VERSION 5.7 ;
  NOWIREEXTENSIONATPIN ON ;
  DIVIDERCHAR "/" ;
  BUSBITCHARS "[]" ;
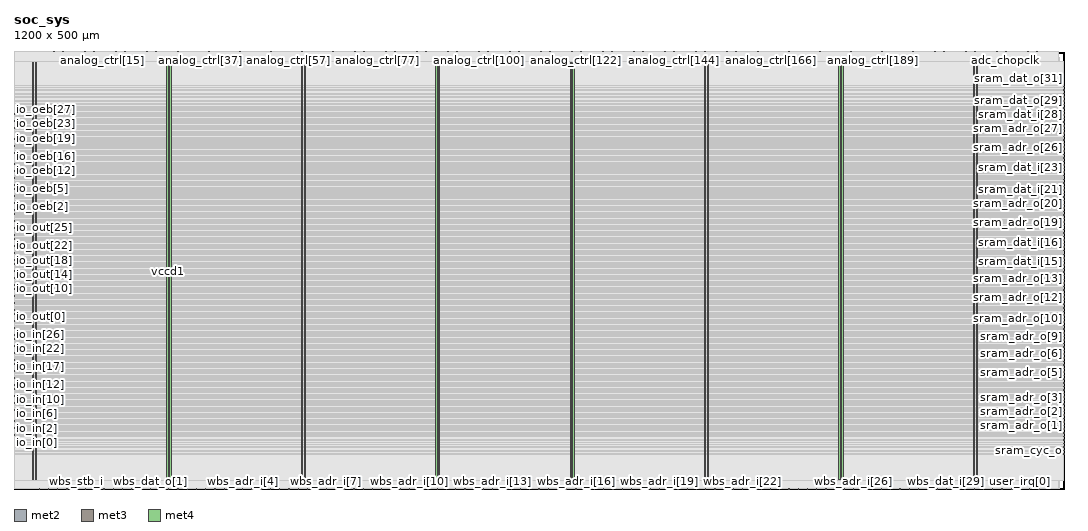
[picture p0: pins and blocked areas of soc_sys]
MACRO soc_sys
  CLASS BLOCK ;
  FOREIGN soc_sys ;
  ORIGIN 0.000 0.000 ;
  SIZE 1200.000 BY 500.000 ;
  PIN adc_chopclk
    DIRECTION INPUT ;
    USE SIGNAL ;
    ANTENNAGATEAREA 0.647700 ;
    ANTENNADIFFAREA 0.434700 ;
    PORT
      LAYER met2 ;
        RECT 1133.530 499.720 1133.810 500.000 ;
    END
  END adc_chopclk
  PIN adc_dout[0]
    DIRECTION INPUT ;
    USE SIGNAL ;
    ANTENNAGATEAREA 0.631200 ;
    ANTENNADIFFAREA 0.434700 ;
    PORT
      LAYER met2 ;
        RECT 1072.810 499.720 1073.090 500.000 ;
    END
  END adc_dout[0]
  PIN adc_dout[1]
    DIRECTION INPUT ;
    USE SIGNAL ;
    ANTENNAGATEAREA 0.593700 ;
    ANTENNADIFFAREA 0.434700 ;
    PORT
      LAYER met2 ;
        RECT 1077.870 499.720 1078.150 500.000 ;
    END
  END adc_dout[1]
  PIN adc_dout[2]
    DIRECTION INPUT ;
    USE SIGNAL ;
    ANTENNAGATEAREA 0.593700 ;
    ANTENNADIFFAREA 0.434700 ;
    PORT
      LAYER met2 ;
        RECT 1082.930 499.720 1083.210 500.000 ;
    END
  END adc_dout[2]
  PIN adc_dout[3]
    DIRECTION INPUT ;
    USE SIGNAL ;
    ANTENNAGATEAREA 0.631200 ;
    ANTENNADIFFAREA 0.434700 ;
    PORT
      LAYER met2 ;
        RECT 1087.990 499.720 1088.270 500.000 ;
    END
  END adc_dout[3]
  PIN adc_dout[4]
    DIRECTION INPUT ;
    USE SIGNAL ;
    ANTENNAGATEAREA 0.631200 ;
    ANTENNADIFFAREA 0.434700 ;
    PORT
      LAYER met2 ;
        RECT 1093.050 499.720 1093.330 500.000 ;
    END
  END adc_dout[4]
  PIN adc_dout[5]
    DIRECTION INPUT ;
    USE SIGNAL ;
    ANTENNAGATEAREA 0.593700 ;
    ANTENNADIFFAREA 0.434700 ;
    PORT
      LAYER met2 ;
        RECT 1098.110 499.720 1098.390 500.000 ;
    END
  END adc_dout[5]
  PIN adc_dout[6]
    DIRECTION INPUT ;
    USE SIGNAL ;
    ANTENNAGATEAREA 0.647700 ;
    ANTENNADIFFAREA 0.434700 ;
    PORT
      LAYER met2 ;
        RECT 1103.170 499.720 1103.450 500.000 ;
    END
  END adc_dout[6]
  PIN adc_dout[7]
    DIRECTION INPUT ;
    USE SIGNAL ;
    ANTENNAGATEAREA 0.647700 ;
    ANTENNADIFFAREA 0.434700 ;
    PORT
      LAYER met2 ;
        RECT 1108.230 499.720 1108.510 500.000 ;
    END
  END adc_dout[7]
  PIN adc_ov_one
    DIRECTION INPUT ;
    USE SIGNAL ;
    ANTENNAGATEAREA 0.631200 ;
    ANTENNADIFFAREA 0.434700 ;
    PORT
      LAYER met2 ;
        RECT 1118.350 499.720 1118.630 500.000 ;
    END
  END adc_ov_one
  PIN adc_ov_zero
    DIRECTION INPUT ;
    USE SIGNAL ;
    ANTENNAGATEAREA 0.647700 ;
    ANTENNADIFFAREA 0.434700 ;
    PORT
      LAYER met2 ;
        RECT 1113.290 499.720 1113.570 500.000 ;
    END
  END adc_ov_zero
  PIN adc_scanout
    DIRECTION INPUT ;
    USE SIGNAL ;
    ANTENNAGATEAREA 0.647700 ;
    ANTENNADIFFAREA 0.434700 ;
    PORT
      LAYER met2 ;
        RECT 1123.410 499.720 1123.690 500.000 ;
    END
  END adc_scanout
  PIN adc_test[0]
    DIRECTION INPUT ;
    USE SIGNAL ;
    ANTENNAGATEAREA 0.647700 ;
    ANTENNADIFFAREA 0.434700 ;
    PORT
      LAYER met2 ;
        RECT 1138.590 499.720 1138.870 500.000 ;
    END
  END adc_test[0]
  PIN adc_test[1]
    DIRECTION INPUT ;
    USE SIGNAL ;
    ANTENNAGATEAREA 0.647700 ;
    ANTENNADIFFAREA 0.434700 ;
    PORT
      LAYER met2 ;
        RECT 1143.650 499.720 1143.930 500.000 ;
    END
  END adc_test[1]
  PIN adc_test[2]
    DIRECTION INPUT ;
    USE SIGNAL ;
    ANTENNAGATEAREA 0.647700 ;
    ANTENNADIFFAREA 0.434700 ;
    PORT
      LAYER met2 ;
        RECT 1148.710 499.720 1148.990 500.000 ;
    END
  END adc_test[2]
  PIN adc_test[3]
    DIRECTION INPUT ;
    USE SIGNAL ;
    ANTENNAGATEAREA 0.647700 ;
    ANTENNADIFFAREA 0.434700 ;
    PORT
      LAYER met2 ;
        RECT 1153.770 499.720 1154.050 500.000 ;
    END
  END adc_test[3]
  PIN adc_test[4]
    DIRECTION INPUT ;
    USE SIGNAL ;
    ANTENNAGATEAREA 0.647700 ;
    ANTENNADIFFAREA 0.434700 ;
    PORT
      LAYER met2 ;
        RECT 1158.830 499.720 1159.110 500.000 ;
    END
  END adc_test[4]
  PIN adc_test[5]
    DIRECTION INPUT ;
    USE SIGNAL ;
    ANTENNAGATEAREA 0.631200 ;
    ANTENNADIFFAREA 0.434700 ;
    PORT
      LAYER met2 ;
        RECT 1163.890 499.720 1164.170 500.000 ;
    END
  END adc_test[5]
  PIN adc_test[6]
    DIRECTION INPUT ;
    USE SIGNAL ;
    ANTENNAGATEAREA 0.631200 ;
    ANTENNADIFFAREA 0.434700 ;
    PORT
      LAYER met2 ;
        RECT 1168.950 499.720 1169.230 500.000 ;
    END
  END adc_test[6]
  PIN adc_test[7]
    DIRECTION INPUT ;
    USE SIGNAL ;
    ANTENNAGATEAREA 0.631200 ;
    ANTENNADIFFAREA 0.434700 ;
    PORT
      LAYER met2 ;
        RECT 1174.010 499.720 1174.290 500.000 ;
    END
  END adc_test[7]
  PIN adc_test_dig
    DIRECTION INPUT ;
    USE SIGNAL ;
    ANTENNAGATEAREA 0.647700 ;
    ANTENNADIFFAREA 0.434700 ;
    PORT
      LAYER met2 ;
        RECT 1128.470 499.720 1128.750 500.000 ;
    END
  END adc_test_dig
  PIN analog_ctrl[0]
    DIRECTION OUTPUT ;
    USE SIGNAL ;
    ANTENNADIFFAREA 2.673000 ;
    PORT
      LAYER met2 ;
        RECT 25.390 499.720 25.670 500.000 ;
    END
  END analog_ctrl[0]
  PIN analog_ctrl[100]
    DIRECTION OUTPUT ;
    USE SIGNAL ;
    ANTENNADIFFAREA 2.673000 ;
    PORT
      LAYER met2 ;
        RECT 531.390 499.720 531.670 500.000 ;
    END
  END analog_ctrl[100]
  PIN analog_ctrl[101]
    DIRECTION OUTPUT ;
    USE SIGNAL ;
    ANTENNADIFFAREA 2.673000 ;
    PORT
      LAYER met2 ;
        RECT 536.450 499.720 536.730 500.000 ;
    END
  END analog_ctrl[101]
  PIN analog_ctrl[102]
    DIRECTION OUTPUT ;
    USE SIGNAL ;
    ANTENNADIFFAREA 2.673000 ;
    PORT
      LAYER met2 ;
        RECT 541.510 499.720 541.790 500.000 ;
    END
  END analog_ctrl[102]
  PIN analog_ctrl[103]
    DIRECTION OUTPUT ;
    USE SIGNAL ;
    ANTENNADIFFAREA 2.673000 ;
    PORT
      LAYER met2 ;
        RECT 546.570 499.720 546.850 500.000 ;
    END
  END analog_ctrl[103]
  PIN analog_ctrl[104]
    DIRECTION OUTPUT ;
    USE SIGNAL ;
    ANTENNADIFFAREA 2.673000 ;
    PORT
      LAYER met2 ;
        RECT 551.630 499.720 551.910 500.000 ;
    END
  END analog_ctrl[104]
  PIN analog_ctrl[105]
    DIRECTION OUTPUT ;
    USE SIGNAL ;
    ANTENNADIFFAREA 2.673000 ;
    PORT
      LAYER met2 ;
        RECT 556.690 499.720 556.970 500.000 ;
    END
  END analog_ctrl[105]
  PIN analog_ctrl[106]
    DIRECTION OUTPUT ;
    USE SIGNAL ;
    ANTENNADIFFAREA 2.673000 ;
    PORT
      LAYER met2 ;
        RECT 561.750 499.720 562.030 500.000 ;
    END
  END analog_ctrl[106]
  PIN analog_ctrl[107]
    DIRECTION OUTPUT ;
    USE SIGNAL ;
    ANTENNADIFFAREA 2.673000 ;
    PORT
      LAYER met2 ;
        RECT 566.810 499.720 567.090 500.000 ;
    END
  END analog_ctrl[107]
  PIN analog_ctrl[108]
    DIRECTION OUTPUT ;
    USE SIGNAL ;
    ANTENNADIFFAREA 2.673000 ;
    PORT
      LAYER met2 ;
        RECT 571.870 499.720 572.150 500.000 ;
    END
  END analog_ctrl[108]
  PIN analog_ctrl[109]
    DIRECTION OUTPUT ;
    USE SIGNAL ;
    ANTENNADIFFAREA 2.673000 ;
    PORT
      LAYER met2 ;
        RECT 576.930 499.720 577.210 500.000 ;
    END
  END analog_ctrl[109]
  PIN analog_ctrl[10]
    DIRECTION OUTPUT ;
    USE SIGNAL ;
    ANTENNADIFFAREA 2.673000 ;
    PORT
      LAYER met2 ;
        RECT 75.990 499.720 76.270 500.000 ;
    END
  END analog_ctrl[10]
  PIN analog_ctrl[110]
    DIRECTION OUTPUT ;
    USE SIGNAL ;
    ANTENNADIFFAREA 2.673000 ;
    PORT
      LAYER met2 ;
        RECT 581.990 499.720 582.270 500.000 ;
    END
  END analog_ctrl[110]
  PIN analog_ctrl[111]
    DIRECTION OUTPUT ;
    USE SIGNAL ;
    ANTENNADIFFAREA 2.673000 ;
    PORT
      LAYER met2 ;
        RECT 587.050 499.720 587.330 500.000 ;
    END
  END analog_ctrl[111]
  PIN analog_ctrl[112]
    DIRECTION OUTPUT ;
    USE SIGNAL ;
    ANTENNADIFFAREA 2.673000 ;
    PORT
      LAYER met2 ;
        RECT 592.110 499.720 592.390 500.000 ;
    END
  END analog_ctrl[112]
  PIN analog_ctrl[113]
    DIRECTION OUTPUT ;
    USE SIGNAL ;
    ANTENNADIFFAREA 2.673000 ;
    PORT
      LAYER met2 ;
        RECT 597.170 499.720 597.450 500.000 ;
    END
  END analog_ctrl[113]
  PIN analog_ctrl[114]
    DIRECTION OUTPUT ;
    USE SIGNAL ;
    ANTENNADIFFAREA 2.673000 ;
    PORT
      LAYER met2 ;
        RECT 602.230 499.720 602.510 500.000 ;
    END
  END analog_ctrl[114]
  PIN analog_ctrl[115]
    DIRECTION OUTPUT ;
    USE SIGNAL ;
    ANTENNADIFFAREA 2.673000 ;
    PORT
      LAYER met2 ;
        RECT 607.290 499.720 607.570 500.000 ;
    END
  END analog_ctrl[115]
  PIN analog_ctrl[116]
    DIRECTION OUTPUT ;
    USE SIGNAL ;
    ANTENNADIFFAREA 2.673000 ;
    PORT
      LAYER met2 ;
        RECT 612.350 499.720 612.630 500.000 ;
    END
  END analog_ctrl[116]
  PIN analog_ctrl[117]
    DIRECTION OUTPUT ;
    USE SIGNAL ;
    ANTENNADIFFAREA 2.673000 ;
    PORT
      LAYER met2 ;
        RECT 617.410 499.720 617.690 500.000 ;
    END
  END analog_ctrl[117]
  PIN analog_ctrl[118]
    DIRECTION OUTPUT ;
    USE SIGNAL ;
    ANTENNADIFFAREA 2.673000 ;
    PORT
      LAYER met2 ;
        RECT 622.470 499.720 622.750 500.000 ;
    END
  END analog_ctrl[118]
  PIN analog_ctrl[119]
    DIRECTION OUTPUT ;
    USE SIGNAL ;
    ANTENNADIFFAREA 2.673000 ;
    PORT
      LAYER met2 ;
        RECT 627.530 499.720 627.810 500.000 ;
    END
  END analog_ctrl[119]
  PIN analog_ctrl[11]
    DIRECTION OUTPUT ;
    USE SIGNAL ;
    ANTENNADIFFAREA 2.673000 ;
    PORT
      LAYER met2 ;
        RECT 81.050 499.720 81.330 500.000 ;
    END
  END analog_ctrl[11]
  PIN analog_ctrl[120]
    DIRECTION OUTPUT ;
    USE SIGNAL ;
    ANTENNADIFFAREA 2.673000 ;
    PORT
      LAYER met2 ;
        RECT 632.590 499.720 632.870 500.000 ;
    END
  END analog_ctrl[120]
  PIN analog_ctrl[121]
    DIRECTION OUTPUT ;
    USE SIGNAL ;
    ANTENNADIFFAREA 2.673000 ;
    PORT
      LAYER met2 ;
        RECT 637.650 499.720 637.930 500.000 ;
    END
  END analog_ctrl[121]
  PIN analog_ctrl[122]
    DIRECTION OUTPUT ;
    USE SIGNAL ;
    ANTENNADIFFAREA 2.673000 ;
    PORT
      LAYER met2 ;
        RECT 642.710 499.720 642.990 500.000 ;
    END
  END analog_ctrl[122]
  PIN analog_ctrl[123]
    DIRECTION OUTPUT ;
    USE SIGNAL ;
    ANTENNADIFFAREA 2.673000 ;
    PORT
      LAYER met2 ;
        RECT 647.770 499.720 648.050 500.000 ;
    END
  END analog_ctrl[123]
  PIN analog_ctrl[124]
    DIRECTION OUTPUT ;
    USE SIGNAL ;
    ANTENNADIFFAREA 2.673000 ;
    PORT
      LAYER met2 ;
        RECT 652.830 499.720 653.110 500.000 ;
    END
  END analog_ctrl[124]
  PIN analog_ctrl[125]
    DIRECTION OUTPUT ;
    USE SIGNAL ;
    ANTENNADIFFAREA 2.673000 ;
    PORT
      LAYER met2 ;
        RECT 657.890 499.720 658.170 500.000 ;
    END
  END analog_ctrl[125]
  PIN analog_ctrl[126]
    DIRECTION OUTPUT ;
    USE SIGNAL ;
    ANTENNADIFFAREA 2.673000 ;
    PORT
      LAYER met2 ;
        RECT 662.950 499.720 663.230 500.000 ;
    END
  END analog_ctrl[126]
  PIN analog_ctrl[127]
    DIRECTION OUTPUT ;
    USE SIGNAL ;
    ANTENNADIFFAREA 2.673000 ;
    PORT
      LAYER met2 ;
        RECT 668.010 499.720 668.290 500.000 ;
    END
  END analog_ctrl[127]
  PIN analog_ctrl[128]
    DIRECTION OUTPUT ;
    USE SIGNAL ;
    ANTENNADIFFAREA 2.673000 ;
    PORT
      LAYER met2 ;
        RECT 673.070 499.720 673.350 500.000 ;
    END
  END analog_ctrl[128]
  PIN analog_ctrl[129]
    DIRECTION OUTPUT ;
    USE SIGNAL ;
    ANTENNADIFFAREA 2.673000 ;
    PORT
      LAYER met2 ;
        RECT 678.130 499.720 678.410 500.000 ;
    END
  END analog_ctrl[129]
  PIN analog_ctrl[12]
    DIRECTION OUTPUT ;
    USE SIGNAL ;
    ANTENNADIFFAREA 2.673000 ;
    PORT
      LAYER met2 ;
        RECT 86.110 499.720 86.390 500.000 ;
    END
  END analog_ctrl[12]
  PIN analog_ctrl[130]
    DIRECTION OUTPUT ;
    USE SIGNAL ;
    ANTENNADIFFAREA 2.673000 ;
    PORT
      LAYER met2 ;
        RECT 683.190 499.720 683.470 500.000 ;
    END
  END analog_ctrl[130]
  PIN analog_ctrl[131]
    DIRECTION OUTPUT ;
    USE SIGNAL ;
    ANTENNADIFFAREA 2.673000 ;
    PORT
      LAYER met2 ;
        RECT 688.250 499.720 688.530 500.000 ;
    END
  END analog_ctrl[131]
  PIN analog_ctrl[132]
    DIRECTION OUTPUT ;
    USE SIGNAL ;
    ANTENNADIFFAREA 2.673000 ;
    PORT
      LAYER met2 ;
        RECT 693.310 499.720 693.590 500.000 ;
    END
  END analog_ctrl[132]
  PIN analog_ctrl[133]
    DIRECTION OUTPUT ;
    USE SIGNAL ;
    ANTENNADIFFAREA 2.673000 ;
    PORT
      LAYER met2 ;
        RECT 698.370 499.720 698.650 500.000 ;
    END
  END analog_ctrl[133]
  PIN analog_ctrl[134]
    DIRECTION OUTPUT ;
    USE SIGNAL ;
    ANTENNADIFFAREA 2.673000 ;
    PORT
      LAYER met2 ;
        RECT 703.430 499.720 703.710 500.000 ;
    END
  END analog_ctrl[134]
  PIN analog_ctrl[135]
    DIRECTION OUTPUT ;
    USE SIGNAL ;
    ANTENNADIFFAREA 2.673000 ;
    PORT
      LAYER met2 ;
        RECT 708.490 499.720 708.770 500.000 ;
    END
  END analog_ctrl[135]
  PIN analog_ctrl[136]
    DIRECTION OUTPUT ;
    USE SIGNAL ;
    ANTENNADIFFAREA 2.673000 ;
    PORT
      LAYER met2 ;
        RECT 713.550 499.720 713.830 500.000 ;
    END
  END analog_ctrl[136]
  PIN analog_ctrl[137]
    DIRECTION OUTPUT ;
    USE SIGNAL ;
    ANTENNADIFFAREA 2.673000 ;
    PORT
      LAYER met2 ;
        RECT 718.610 499.720 718.890 500.000 ;
    END
  END analog_ctrl[137]
  PIN analog_ctrl[138]
    DIRECTION OUTPUT ;
    USE SIGNAL ;
    ANTENNADIFFAREA 2.673000 ;
    PORT
      LAYER met2 ;
        RECT 723.670 499.720 723.950 500.000 ;
    END
  END analog_ctrl[138]
  PIN analog_ctrl[139]
    DIRECTION OUTPUT ;
    USE SIGNAL ;
    ANTENNADIFFAREA 2.673000 ;
    PORT
      LAYER met2 ;
        RECT 728.730 499.720 729.010 500.000 ;
    END
  END analog_ctrl[139]
  PIN analog_ctrl[13]
    DIRECTION OUTPUT ;
    USE SIGNAL ;
    ANTENNADIFFAREA 2.673000 ;
    PORT
      LAYER met2 ;
        RECT 91.170 499.720 91.450 500.000 ;
    END
  END analog_ctrl[13]
  PIN analog_ctrl[140]
    DIRECTION OUTPUT ;
    USE SIGNAL ;
    ANTENNADIFFAREA 2.673000 ;
    PORT
      LAYER met2 ;
        RECT 733.790 499.720 734.070 500.000 ;
    END
  END analog_ctrl[140]
  PIN analog_ctrl[141]
    DIRECTION OUTPUT ;
    USE SIGNAL ;
    ANTENNADIFFAREA 2.673000 ;
    PORT
      LAYER met2 ;
        RECT 738.850 499.720 739.130 500.000 ;
    END
  END analog_ctrl[141]
  PIN analog_ctrl[142]
    DIRECTION OUTPUT ;
    USE SIGNAL ;
    ANTENNADIFFAREA 2.673000 ;
    PORT
      LAYER met2 ;
        RECT 743.910 499.720 744.190 500.000 ;
    END
  END analog_ctrl[142]
  PIN analog_ctrl[143]
    DIRECTION OUTPUT ;
    USE SIGNAL ;
    ANTENNADIFFAREA 2.673000 ;
    PORT
      LAYER met2 ;
        RECT 748.970 499.720 749.250 500.000 ;
    END
  END analog_ctrl[143]
  PIN analog_ctrl[144]
    DIRECTION OUTPUT ;
    USE SIGNAL ;
    ANTENNADIFFAREA 2.673000 ;
    PORT
      LAYER met2 ;
        RECT 754.030 499.720 754.310 500.000 ;
    END
  END analog_ctrl[144]
  PIN analog_ctrl[145]
    DIRECTION OUTPUT ;
    USE SIGNAL ;
    ANTENNADIFFAREA 2.673000 ;
    PORT
      LAYER met2 ;
        RECT 759.090 499.720 759.370 500.000 ;
    END
  END analog_ctrl[145]
  PIN analog_ctrl[146]
    DIRECTION OUTPUT ;
    USE SIGNAL ;
    ANTENNADIFFAREA 2.673000 ;
    PORT
      LAYER met2 ;
        RECT 764.150 499.720 764.430 500.000 ;
    END
  END analog_ctrl[146]
  PIN analog_ctrl[147]
    DIRECTION OUTPUT ;
    USE SIGNAL ;
    ANTENNADIFFAREA 2.673000 ;
    PORT
      LAYER met2 ;
        RECT 769.210 499.720 769.490 500.000 ;
    END
  END analog_ctrl[147]
  PIN analog_ctrl[148]
    DIRECTION OUTPUT ;
    USE SIGNAL ;
    ANTENNADIFFAREA 2.673000 ;
    PORT
      LAYER met2 ;
        RECT 774.270 499.720 774.550 500.000 ;
    END
  END analog_ctrl[148]
  PIN analog_ctrl[149]
    DIRECTION OUTPUT ;
    USE SIGNAL ;
    ANTENNADIFFAREA 2.673000 ;
    PORT
      LAYER met2 ;
        RECT 779.330 499.720 779.610 500.000 ;
    END
  END analog_ctrl[149]
  PIN analog_ctrl[14]
    DIRECTION OUTPUT ;
    USE SIGNAL ;
    ANTENNADIFFAREA 2.673000 ;
    PORT
      LAYER met2 ;
        RECT 96.230 499.720 96.510 500.000 ;
    END
  END analog_ctrl[14]
  PIN analog_ctrl[150]
    DIRECTION OUTPUT ;
    USE SIGNAL ;
    ANTENNADIFFAREA 2.673000 ;
    PORT
      LAYER met2 ;
        RECT 784.390 499.720 784.670 500.000 ;
    END
  END analog_ctrl[150]
  PIN analog_ctrl[151]
    DIRECTION OUTPUT ;
    USE SIGNAL ;
    ANTENNADIFFAREA 2.673000 ;
    PORT
      LAYER met2 ;
        RECT 789.450 499.720 789.730 500.000 ;
    END
  END analog_ctrl[151]
  PIN analog_ctrl[152]
    DIRECTION OUTPUT ;
    USE SIGNAL ;
    ANTENNADIFFAREA 2.673000 ;
    PORT
      LAYER met2 ;
        RECT 794.510 499.720 794.790 500.000 ;
    END
  END analog_ctrl[152]
  PIN analog_ctrl[153]
    DIRECTION OUTPUT ;
    USE SIGNAL ;
    ANTENNADIFFAREA 2.673000 ;
    PORT
      LAYER met2 ;
        RECT 799.570 499.720 799.850 500.000 ;
    END
  END analog_ctrl[153]
  PIN analog_ctrl[154]
    DIRECTION OUTPUT ;
    USE SIGNAL ;
    ANTENNADIFFAREA 2.673000 ;
    PORT
      LAYER met2 ;
        RECT 804.630 499.720 804.910 500.000 ;
    END
  END analog_ctrl[154]
  PIN analog_ctrl[155]
    DIRECTION OUTPUT ;
    USE SIGNAL ;
    ANTENNADIFFAREA 2.673000 ;
    PORT
      LAYER met2 ;
        RECT 809.690 499.720 809.970 500.000 ;
    END
  END analog_ctrl[155]
  PIN analog_ctrl[156]
    DIRECTION OUTPUT ;
    USE SIGNAL ;
    ANTENNADIFFAREA 2.673000 ;
    PORT
      LAYER met2 ;
        RECT 814.750 499.720 815.030 500.000 ;
    END
  END analog_ctrl[156]
  PIN analog_ctrl[157]
    DIRECTION OUTPUT ;
    USE SIGNAL ;
    ANTENNADIFFAREA 2.673000 ;
    PORT
      LAYER met2 ;
        RECT 819.810 499.720 820.090 500.000 ;
    END
  END analog_ctrl[157]
  PIN analog_ctrl[158]
    DIRECTION OUTPUT ;
    USE SIGNAL ;
    ANTENNADIFFAREA 2.673000 ;
    PORT
      LAYER met2 ;
        RECT 824.870 499.720 825.150 500.000 ;
    END
  END analog_ctrl[158]
  PIN analog_ctrl[159]
    DIRECTION OUTPUT ;
    USE SIGNAL ;
    ANTENNADIFFAREA 2.673000 ;
    PORT
      LAYER met2 ;
        RECT 829.930 499.720 830.210 500.000 ;
    END
  END analog_ctrl[159]
  PIN analog_ctrl[15]
    DIRECTION OUTPUT ;
    USE SIGNAL ;
    ANTENNADIFFAREA 2.673000 ;
    PORT
      LAYER met2 ;
        RECT 101.290 499.720 101.570 500.000 ;
    END
  END analog_ctrl[15]
  PIN analog_ctrl[160]
    DIRECTION OUTPUT ;
    USE SIGNAL ;
    ANTENNADIFFAREA 2.673000 ;
    PORT
      LAYER met2 ;
        RECT 834.990 499.720 835.270 500.000 ;
    END
  END analog_ctrl[160]
  PIN analog_ctrl[161]
    DIRECTION OUTPUT ;
    USE SIGNAL ;
    ANTENNADIFFAREA 2.673000 ;
    PORT
      LAYER met2 ;
        RECT 840.050 499.720 840.330 500.000 ;
    END
  END analog_ctrl[161]
  PIN analog_ctrl[162]
    DIRECTION OUTPUT ;
    USE SIGNAL ;
    ANTENNADIFFAREA 2.673000 ;
    PORT
      LAYER met2 ;
        RECT 845.110 499.720 845.390 500.000 ;
    END
  END analog_ctrl[162]
  PIN analog_ctrl[163]
    DIRECTION OUTPUT ;
    USE SIGNAL ;
    ANTENNADIFFAREA 2.673000 ;
    PORT
      LAYER met2 ;
        RECT 850.170 499.720 850.450 500.000 ;
    END
  END analog_ctrl[163]
  PIN analog_ctrl[164]
    DIRECTION OUTPUT ;
    USE SIGNAL ;
    ANTENNADIFFAREA 2.673000 ;
    PORT
      LAYER met2 ;
        RECT 855.230 499.720 855.510 500.000 ;
    END
  END analog_ctrl[164]
  PIN analog_ctrl[165]
    DIRECTION OUTPUT ;
    USE SIGNAL ;
    ANTENNADIFFAREA 2.673000 ;
    PORT
      LAYER met2 ;
        RECT 860.290 499.720 860.570 500.000 ;
    END
  END analog_ctrl[165]
  PIN analog_ctrl[166]
    DIRECTION OUTPUT ;
    USE SIGNAL ;
    ANTENNADIFFAREA 2.673000 ;
    PORT
      LAYER met2 ;
        RECT 865.350 499.720 865.630 500.000 ;
    END
  END analog_ctrl[166]
  PIN analog_ctrl[167]
    DIRECTION OUTPUT ;
    USE SIGNAL ;
    ANTENNADIFFAREA 2.673000 ;
    PORT
      LAYER met2 ;
        RECT 870.410 499.720 870.690 500.000 ;
    END
  END analog_ctrl[167]
  PIN analog_ctrl[168]
    DIRECTION OUTPUT ;
    USE SIGNAL ;
    ANTENNADIFFAREA 2.673000 ;
    PORT
      LAYER met2 ;
        RECT 875.470 499.720 875.750 500.000 ;
    END
  END analog_ctrl[168]
  PIN analog_ctrl[169]
    DIRECTION OUTPUT ;
    USE SIGNAL ;
    ANTENNADIFFAREA 2.673000 ;
    PORT
      LAYER met2 ;
        RECT 880.530 499.720 880.810 500.000 ;
    END
  END analog_ctrl[169]
  PIN analog_ctrl[16]
    DIRECTION OUTPUT ;
    USE SIGNAL ;
    ANTENNADIFFAREA 2.673000 ;
    PORT
      LAYER met2 ;
        RECT 106.350 499.720 106.630 500.000 ;
    END
  END analog_ctrl[16]
  PIN analog_ctrl[170]
    DIRECTION OUTPUT ;
    USE SIGNAL ;
    ANTENNADIFFAREA 2.673000 ;
    PORT
      LAYER met2 ;
        RECT 885.590 499.720 885.870 500.000 ;
    END
  END analog_ctrl[170]
  PIN analog_ctrl[171]
    DIRECTION OUTPUT ;
    USE SIGNAL ;
    ANTENNADIFFAREA 2.673000 ;
    PORT
      LAYER met2 ;
        RECT 890.650 499.720 890.930 500.000 ;
    END
  END analog_ctrl[171]
  PIN analog_ctrl[172]
    DIRECTION OUTPUT ;
    USE SIGNAL ;
    ANTENNADIFFAREA 2.673000 ;
    PORT
      LAYER met2 ;
        RECT 895.710 499.720 895.990 500.000 ;
    END
  END analog_ctrl[172]
  PIN analog_ctrl[173]
    DIRECTION OUTPUT ;
    USE SIGNAL ;
    ANTENNADIFFAREA 2.673000 ;
    PORT
      LAYER met2 ;
        RECT 900.770 499.720 901.050 500.000 ;
    END
  END analog_ctrl[173]
  PIN analog_ctrl[174]
    DIRECTION OUTPUT ;
    USE SIGNAL ;
    ANTENNADIFFAREA 2.673000 ;
    PORT
      LAYER met2 ;
        RECT 905.830 499.720 906.110 500.000 ;
    END
  END analog_ctrl[174]
  PIN analog_ctrl[175]
    DIRECTION OUTPUT ;
    USE SIGNAL ;
    ANTENNADIFFAREA 2.673000 ;
    PORT
      LAYER met2 ;
        RECT 910.890 499.720 911.170 500.000 ;
    END
  END analog_ctrl[175]
  PIN analog_ctrl[176]
    DIRECTION OUTPUT ;
    USE SIGNAL ;
    ANTENNADIFFAREA 2.673000 ;
    PORT
      LAYER met2 ;
        RECT 915.950 499.720 916.230 500.000 ;
    END
  END analog_ctrl[176]
  PIN analog_ctrl[177]
    DIRECTION OUTPUT ;
    USE SIGNAL ;
    ANTENNADIFFAREA 2.673000 ;
    PORT
      LAYER met2 ;
        RECT 921.010 499.720 921.290 500.000 ;
    END
  END analog_ctrl[177]
  PIN analog_ctrl[178]
    DIRECTION OUTPUT ;
    USE SIGNAL ;
    ANTENNADIFFAREA 2.673000 ;
    PORT
      LAYER met2 ;
        RECT 926.070 499.720 926.350 500.000 ;
    END
  END analog_ctrl[178]
  PIN analog_ctrl[179]
    DIRECTION OUTPUT ;
    USE SIGNAL ;
    ANTENNADIFFAREA 2.673000 ;
    PORT
      LAYER met2 ;
        RECT 931.130 499.720 931.410 500.000 ;
    END
  END analog_ctrl[179]
  PIN analog_ctrl[17]
    DIRECTION OUTPUT ;
    USE SIGNAL ;
    ANTENNADIFFAREA 2.673000 ;
    PORT
      LAYER met2 ;
        RECT 111.410 499.720 111.690 500.000 ;
    END
  END analog_ctrl[17]
  PIN analog_ctrl[180]
    DIRECTION OUTPUT ;
    USE SIGNAL ;
    ANTENNADIFFAREA 2.673000 ;
    PORT
      LAYER met2 ;
        RECT 936.190 499.720 936.470 500.000 ;
    END
  END analog_ctrl[180]
  PIN analog_ctrl[181]
    DIRECTION OUTPUT ;
    USE SIGNAL ;
    ANTENNADIFFAREA 2.673000 ;
    PORT
      LAYER met2 ;
        RECT 941.250 499.720 941.530 500.000 ;
    END
  END analog_ctrl[181]
  PIN analog_ctrl[182]
    DIRECTION OUTPUT ;
    USE SIGNAL ;
    ANTENNADIFFAREA 2.673000 ;
    PORT
      LAYER met2 ;
        RECT 946.310 499.720 946.590 500.000 ;
    END
  END analog_ctrl[182]
  PIN analog_ctrl[183]
    DIRECTION OUTPUT ;
    USE SIGNAL ;
    ANTENNADIFFAREA 2.673000 ;
    PORT
      LAYER met2 ;
        RECT 951.370 499.720 951.650 500.000 ;
    END
  END analog_ctrl[183]
  PIN analog_ctrl[184]
    DIRECTION OUTPUT ;
    USE SIGNAL ;
    ANTENNADIFFAREA 2.673000 ;
    PORT
      LAYER met2 ;
        RECT 956.430 499.720 956.710 500.000 ;
    END
  END analog_ctrl[184]
  PIN analog_ctrl[185]
    DIRECTION OUTPUT ;
    USE SIGNAL ;
    ANTENNADIFFAREA 2.673000 ;
    PORT
      LAYER met2 ;
        RECT 961.490 499.720 961.770 500.000 ;
    END
  END analog_ctrl[185]
  PIN analog_ctrl[186]
    DIRECTION OUTPUT ;
    USE SIGNAL ;
    ANTENNADIFFAREA 2.673000 ;
    PORT
      LAYER met2 ;
        RECT 966.550 499.720 966.830 500.000 ;
    END
  END analog_ctrl[186]
  PIN analog_ctrl[187]
    DIRECTION OUTPUT ;
    USE SIGNAL ;
    ANTENNADIFFAREA 2.673000 ;
    PORT
      LAYER met2 ;
        RECT 971.610 499.720 971.890 500.000 ;
    END
  END analog_ctrl[187]
  PIN analog_ctrl[188]
    DIRECTION OUTPUT ;
    USE SIGNAL ;
    ANTENNADIFFAREA 2.673000 ;
    PORT
      LAYER met2 ;
        RECT 976.670 499.720 976.950 500.000 ;
    END
  END analog_ctrl[188]
  PIN analog_ctrl[189]
    DIRECTION OUTPUT ;
    USE SIGNAL ;
    ANTENNADIFFAREA 2.673000 ;
    PORT
      LAYER met2 ;
        RECT 981.730 499.720 982.010 500.000 ;
    END
  END analog_ctrl[189]
  PIN analog_ctrl[18]
    DIRECTION OUTPUT ;
    USE SIGNAL ;
    ANTENNADIFFAREA 2.673000 ;
    PORT
      LAYER met2 ;
        RECT 116.470 499.720 116.750 500.000 ;
    END
  END analog_ctrl[18]
  PIN analog_ctrl[190]
    DIRECTION OUTPUT ;
    USE SIGNAL ;
    ANTENNADIFFAREA 2.673000 ;
    PORT
      LAYER met2 ;
        RECT 986.790 499.720 987.070 500.000 ;
    END
  END analog_ctrl[190]
  PIN analog_ctrl[191]
    DIRECTION OUTPUT ;
    USE SIGNAL ;
    ANTENNADIFFAREA 2.673000 ;
    PORT
      LAYER met2 ;
        RECT 991.850 499.720 992.130 500.000 ;
    END
  END analog_ctrl[191]
  PIN analog_ctrl[192]
    DIRECTION OUTPUT ;
    USE SIGNAL ;
    ANTENNADIFFAREA 2.673000 ;
    PORT
      LAYER met2 ;
        RECT 996.910 499.720 997.190 500.000 ;
    END
  END analog_ctrl[192]
  PIN analog_ctrl[193]
    DIRECTION OUTPUT ;
    USE SIGNAL ;
    ANTENNADIFFAREA 2.673000 ;
    PORT
      LAYER met2 ;
        RECT 1001.970 499.720 1002.250 500.000 ;
    END
  END analog_ctrl[193]
  PIN analog_ctrl[194]
    DIRECTION OUTPUT ;
    USE SIGNAL ;
    ANTENNADIFFAREA 2.673000 ;
    PORT
      LAYER met2 ;
        RECT 1007.030 499.720 1007.310 500.000 ;
    END
  END analog_ctrl[194]
  PIN analog_ctrl[195]
    DIRECTION OUTPUT ;
    USE SIGNAL ;
    ANTENNADIFFAREA 2.673000 ;
    PORT
      LAYER met2 ;
        RECT 1012.090 499.720 1012.370 500.000 ;
    END
  END analog_ctrl[195]
  PIN analog_ctrl[196]
    DIRECTION OUTPUT ;
    USE SIGNAL ;
    ANTENNADIFFAREA 2.673000 ;
    PORT
      LAYER met2 ;
        RECT 1017.150 499.720 1017.430 500.000 ;
    END
  END analog_ctrl[196]
  PIN analog_ctrl[197]
    DIRECTION OUTPUT ;
    USE SIGNAL ;
    ANTENNADIFFAREA 2.673000 ;
    PORT
      LAYER met2 ;
        RECT 1022.210 499.720 1022.490 500.000 ;
    END
  END analog_ctrl[197]
  PIN analog_ctrl[198]
    DIRECTION OUTPUT ;
    USE SIGNAL ;
    ANTENNADIFFAREA 2.673000 ;
    PORT
      LAYER met2 ;
        RECT 1027.270 499.720 1027.550 500.000 ;
    END
  END analog_ctrl[198]
  PIN analog_ctrl[199]
    DIRECTION OUTPUT ;
    USE SIGNAL ;
    ANTENNADIFFAREA 2.673000 ;
    PORT
      LAYER met2 ;
        RECT 1032.330 499.720 1032.610 500.000 ;
    END
  END analog_ctrl[199]
  PIN analog_ctrl[19]
    DIRECTION OUTPUT ;
    USE SIGNAL ;
    ANTENNADIFFAREA 2.673000 ;
    PORT
      LAYER met2 ;
        RECT 121.530 499.720 121.810 500.000 ;
    END
  END analog_ctrl[19]
  PIN analog_ctrl[1]
    DIRECTION OUTPUT ;
    USE SIGNAL ;
    ANTENNADIFFAREA 2.673000 ;
    PORT
      LAYER met2 ;
        RECT 30.450 499.720 30.730 500.000 ;
    END
  END analog_ctrl[1]
  PIN analog_ctrl[200]
    DIRECTION OUTPUT ;
    USE SIGNAL ;
    ANTENNADIFFAREA 2.673000 ;
    PORT
      LAYER met2 ;
        RECT 1037.390 499.720 1037.670 500.000 ;
    END
  END analog_ctrl[200]
  PIN analog_ctrl[201]
    DIRECTION OUTPUT ;
    USE SIGNAL ;
    ANTENNADIFFAREA 2.673000 ;
    PORT
      LAYER met2 ;
        RECT 1042.450 499.720 1042.730 500.000 ;
    END
  END analog_ctrl[201]
  PIN analog_ctrl[202]
    DIRECTION OUTPUT ;
    USE SIGNAL ;
    ANTENNADIFFAREA 2.673000 ;
    PORT
      LAYER met2 ;
        RECT 1047.510 499.720 1047.790 500.000 ;
    END
  END analog_ctrl[202]
  PIN analog_ctrl[203]
    DIRECTION OUTPUT ;
    USE SIGNAL ;
    ANTENNADIFFAREA 2.673000 ;
    PORT
      LAYER met2 ;
        RECT 1052.570 499.720 1052.850 500.000 ;
    END
  END analog_ctrl[203]
  PIN analog_ctrl[204]
    DIRECTION OUTPUT ;
    USE SIGNAL ;
    ANTENNADIFFAREA 2.673000 ;
    PORT
      LAYER met2 ;
        RECT 1057.630 499.720 1057.910 500.000 ;
    END
  END analog_ctrl[204]
  PIN analog_ctrl[205]
    DIRECTION OUTPUT ;
    USE SIGNAL ;
    ANTENNADIFFAREA 2.673000 ;
    PORT
      LAYER met2 ;
        RECT 1062.690 499.720 1062.970 500.000 ;
    END
  END analog_ctrl[205]
  PIN analog_ctrl[206]
    DIRECTION OUTPUT ;
    USE SIGNAL ;
    ANTENNADIFFAREA 2.673000 ;
    PORT
      LAYER met2 ;
        RECT 1067.750 499.720 1068.030 500.000 ;
    END
  END analog_ctrl[206]
  PIN analog_ctrl[20]
    DIRECTION OUTPUT ;
    USE SIGNAL ;
    ANTENNADIFFAREA 2.673000 ;
    PORT
      LAYER met2 ;
        RECT 126.590 499.720 126.870 500.000 ;
    END
  END analog_ctrl[20]
  PIN analog_ctrl[21]
    DIRECTION OUTPUT ;
    USE SIGNAL ;
    ANTENNADIFFAREA 2.673000 ;
    PORT
      LAYER met2 ;
        RECT 131.650 499.720 131.930 500.000 ;
    END
  END analog_ctrl[21]
  PIN analog_ctrl[22]
    DIRECTION OUTPUT ;
    USE SIGNAL ;
    ANTENNADIFFAREA 2.673000 ;
    PORT
      LAYER met2 ;
        RECT 136.710 499.720 136.990 500.000 ;
    END
  END analog_ctrl[22]
  PIN analog_ctrl[23]
    DIRECTION OUTPUT ;
    USE SIGNAL ;
    ANTENNADIFFAREA 2.673000 ;
    PORT
      LAYER met2 ;
        RECT 141.770 499.720 142.050 500.000 ;
    END
  END analog_ctrl[23]
  PIN analog_ctrl[24]
    DIRECTION OUTPUT ;
    USE SIGNAL ;
    ANTENNADIFFAREA 2.673000 ;
    PORT
      LAYER met2 ;
        RECT 146.830 499.720 147.110 500.000 ;
    END
  END analog_ctrl[24]
  PIN analog_ctrl[25]
    DIRECTION OUTPUT ;
    USE SIGNAL ;
    ANTENNADIFFAREA 2.673000 ;
    PORT
      LAYER met2 ;
        RECT 151.890 499.720 152.170 500.000 ;
    END
  END analog_ctrl[25]
  PIN analog_ctrl[26]
    DIRECTION OUTPUT ;
    USE SIGNAL ;
    ANTENNADIFFAREA 2.673000 ;
    PORT
      LAYER met2 ;
        RECT 156.950 499.720 157.230 500.000 ;
    END
  END analog_ctrl[26]
  PIN analog_ctrl[27]
    DIRECTION OUTPUT ;
    USE SIGNAL ;
    ANTENNADIFFAREA 2.673000 ;
    PORT
      LAYER met2 ;
        RECT 162.010 499.720 162.290 500.000 ;
    END
  END analog_ctrl[27]
  PIN analog_ctrl[28]
    DIRECTION OUTPUT ;
    USE SIGNAL ;
    ANTENNADIFFAREA 2.673000 ;
    PORT
      LAYER met2 ;
        RECT 167.070 499.720 167.350 500.000 ;
    END
  END analog_ctrl[28]
  PIN analog_ctrl[29]
    DIRECTION OUTPUT ;
    USE SIGNAL ;
    ANTENNADIFFAREA 2.673000 ;
    PORT
      LAYER met2 ;
        RECT 172.130 499.720 172.410 500.000 ;
    END
  END analog_ctrl[29]
  PIN analog_ctrl[2]
    DIRECTION OUTPUT ;
    USE SIGNAL ;
    ANTENNADIFFAREA 2.673000 ;
    PORT
      LAYER met2 ;
        RECT 35.510 499.720 35.790 500.000 ;
    END
  END analog_ctrl[2]
  PIN analog_ctrl[30]
    DIRECTION OUTPUT ;
    USE SIGNAL ;
    ANTENNADIFFAREA 2.673000 ;
    PORT
      LAYER met2 ;
        RECT 177.190 499.720 177.470 500.000 ;
    END
  END analog_ctrl[30]
  PIN analog_ctrl[31]
    DIRECTION OUTPUT ;
    USE SIGNAL ;
    ANTENNADIFFAREA 2.673000 ;
    PORT
      LAYER met2 ;
        RECT 182.250 499.720 182.530 500.000 ;
    END
  END analog_ctrl[31]
  PIN analog_ctrl[32]
    DIRECTION OUTPUT ;
    USE SIGNAL ;
    ANTENNADIFFAREA 2.673000 ;
    PORT
      LAYER met2 ;
        RECT 187.310 499.720 187.590 500.000 ;
    END
  END analog_ctrl[32]
  PIN analog_ctrl[33]
    DIRECTION OUTPUT ;
    USE SIGNAL ;
    ANTENNADIFFAREA 2.673000 ;
    PORT
      LAYER met2 ;
        RECT 192.370 499.720 192.650 500.000 ;
    END
  END analog_ctrl[33]
  PIN analog_ctrl[34]
    DIRECTION OUTPUT ;
    USE SIGNAL ;
    ANTENNADIFFAREA 2.673000 ;
    PORT
      LAYER met2 ;
        RECT 197.430 499.720 197.710 500.000 ;
    END
  END analog_ctrl[34]
  PIN analog_ctrl[35]
    DIRECTION OUTPUT ;
    USE SIGNAL ;
    ANTENNADIFFAREA 2.673000 ;
    PORT
      LAYER met2 ;
        RECT 202.490 499.720 202.770 500.000 ;
    END
  END analog_ctrl[35]
  PIN analog_ctrl[36]
    DIRECTION OUTPUT ;
    USE SIGNAL ;
    ANTENNADIFFAREA 2.673000 ;
    PORT
      LAYER met2 ;
        RECT 207.550 499.720 207.830 500.000 ;
    END
  END analog_ctrl[36]
  PIN analog_ctrl[37]
    DIRECTION OUTPUT ;
    USE SIGNAL ;
    ANTENNADIFFAREA 2.673000 ;
    PORT
      LAYER met2 ;
        RECT 212.610 499.720 212.890 500.000 ;
    END
  END analog_ctrl[37]
  PIN analog_ctrl[38]
    DIRECTION OUTPUT ;
    USE SIGNAL ;
    ANTENNADIFFAREA 2.673000 ;
    PORT
      LAYER met2 ;
        RECT 217.670 499.720 217.950 500.000 ;
    END
  END analog_ctrl[38]
  PIN analog_ctrl[39]
    DIRECTION OUTPUT ;
    USE SIGNAL ;
    ANTENNADIFFAREA 2.673000 ;
    PORT
      LAYER met2 ;
        RECT 222.730 499.720 223.010 500.000 ;
    END
  END analog_ctrl[39]
  PIN analog_ctrl[3]
    DIRECTION OUTPUT ;
    USE SIGNAL ;
    ANTENNADIFFAREA 2.673000 ;
    PORT
      LAYER met2 ;
        RECT 40.570 499.720 40.850 500.000 ;
    END
  END analog_ctrl[3]
  PIN analog_ctrl[40]
    DIRECTION OUTPUT ;
    USE SIGNAL ;
    ANTENNADIFFAREA 2.673000 ;
    PORT
      LAYER met2 ;
        RECT 227.790 499.720 228.070 500.000 ;
    END
  END analog_ctrl[40]
  PIN analog_ctrl[41]
    DIRECTION OUTPUT ;
    USE SIGNAL ;
    ANTENNADIFFAREA 2.673000 ;
    PORT
      LAYER met2 ;
        RECT 232.850 499.720 233.130 500.000 ;
    END
  END analog_ctrl[41]
  PIN analog_ctrl[42]
    DIRECTION OUTPUT ;
    USE SIGNAL ;
    ANTENNADIFFAREA 2.673000 ;
    PORT
      LAYER met2 ;
        RECT 237.910 499.720 238.190 500.000 ;
    END
  END analog_ctrl[42]
  PIN analog_ctrl[43]
    DIRECTION OUTPUT ;
    USE SIGNAL ;
    ANTENNADIFFAREA 2.673000 ;
    PORT
      LAYER met2 ;
        RECT 242.970 499.720 243.250 500.000 ;
    END
  END analog_ctrl[43]
  PIN analog_ctrl[44]
    DIRECTION OUTPUT ;
    USE SIGNAL ;
    ANTENNADIFFAREA 2.673000 ;
    PORT
      LAYER met2 ;
        RECT 248.030 499.720 248.310 500.000 ;
    END
  END analog_ctrl[44]
  PIN analog_ctrl[45]
    DIRECTION OUTPUT ;
    USE SIGNAL ;
    ANTENNADIFFAREA 2.673000 ;
    PORT
      LAYER met2 ;
        RECT 253.090 499.720 253.370 500.000 ;
    END
  END analog_ctrl[45]
  PIN analog_ctrl[46]
    DIRECTION OUTPUT ;
    USE SIGNAL ;
    ANTENNADIFFAREA 2.673000 ;
    PORT
      LAYER met2 ;
        RECT 258.150 499.720 258.430 500.000 ;
    END
  END analog_ctrl[46]
  PIN analog_ctrl[47]
    DIRECTION OUTPUT ;
    USE SIGNAL ;
    ANTENNADIFFAREA 2.673000 ;
    PORT
      LAYER met2 ;
        RECT 263.210 499.720 263.490 500.000 ;
    END
  END analog_ctrl[47]
  PIN analog_ctrl[48]
    DIRECTION OUTPUT ;
    USE SIGNAL ;
    ANTENNADIFFAREA 2.673000 ;
    PORT
      LAYER met2 ;
        RECT 268.270 499.720 268.550 500.000 ;
    END
  END analog_ctrl[48]
  PIN analog_ctrl[49]
    DIRECTION OUTPUT ;
    USE SIGNAL ;
    ANTENNADIFFAREA 2.673000 ;
    PORT
      LAYER met2 ;
        RECT 273.330 499.720 273.610 500.000 ;
    END
  END analog_ctrl[49]
  PIN analog_ctrl[4]
    DIRECTION OUTPUT ;
    USE SIGNAL ;
    ANTENNADIFFAREA 2.673000 ;
    PORT
      LAYER met2 ;
        RECT 45.630 499.720 45.910 500.000 ;
    END
  END analog_ctrl[4]
  PIN analog_ctrl[50]
    DIRECTION OUTPUT ;
    USE SIGNAL ;
    ANTENNADIFFAREA 2.673000 ;
    PORT
      LAYER met2 ;
        RECT 278.390 499.720 278.670 500.000 ;
    END
  END analog_ctrl[50]
  PIN analog_ctrl[51]
    DIRECTION OUTPUT ;
    USE SIGNAL ;
    ANTENNADIFFAREA 2.673000 ;
    PORT
      LAYER met2 ;
        RECT 283.450 499.720 283.730 500.000 ;
    END
  END analog_ctrl[51]
  PIN analog_ctrl[52]
    DIRECTION OUTPUT ;
    USE SIGNAL ;
    ANTENNADIFFAREA 2.673000 ;
    PORT
      LAYER met2 ;
        RECT 288.510 499.720 288.790 500.000 ;
    END
  END analog_ctrl[52]
  PIN analog_ctrl[53]
    DIRECTION OUTPUT ;
    USE SIGNAL ;
    ANTENNADIFFAREA 2.673000 ;
    PORT
      LAYER met2 ;
        RECT 293.570 499.720 293.850 500.000 ;
    END
  END analog_ctrl[53]
  PIN analog_ctrl[54]
    DIRECTION OUTPUT ;
    USE SIGNAL ;
    ANTENNADIFFAREA 2.673000 ;
    PORT
      LAYER met2 ;
        RECT 298.630 499.720 298.910 500.000 ;
    END
  END analog_ctrl[54]
  PIN analog_ctrl[55]
    DIRECTION OUTPUT ;
    USE SIGNAL ;
    ANTENNADIFFAREA 2.673000 ;
    PORT
      LAYER met2 ;
        RECT 303.690 499.720 303.970 500.000 ;
    END
  END analog_ctrl[55]
  PIN analog_ctrl[56]
    DIRECTION OUTPUT ;
    USE SIGNAL ;
    ANTENNADIFFAREA 2.673000 ;
    PORT
      LAYER met2 ;
        RECT 308.750 499.720 309.030 500.000 ;
    END
  END analog_ctrl[56]
  PIN analog_ctrl[57]
    DIRECTION OUTPUT ;
    USE SIGNAL ;
    ANTENNADIFFAREA 2.673000 ;
    PORT
      LAYER met2 ;
        RECT 313.810 499.720 314.090 500.000 ;
    END
  END analog_ctrl[57]
  PIN analog_ctrl[58]
    DIRECTION OUTPUT ;
    USE SIGNAL ;
    ANTENNADIFFAREA 2.673000 ;
    PORT
      LAYER met2 ;
        RECT 318.870 499.720 319.150 500.000 ;
    END
  END analog_ctrl[58]
  PIN analog_ctrl[59]
    DIRECTION OUTPUT ;
    USE SIGNAL ;
    ANTENNADIFFAREA 2.673000 ;
    PORT
      LAYER met2 ;
        RECT 323.930 499.720 324.210 500.000 ;
    END
  END analog_ctrl[59]
  PIN analog_ctrl[5]
    DIRECTION OUTPUT ;
    USE SIGNAL ;
    ANTENNADIFFAREA 2.673000 ;
    PORT
      LAYER met2 ;
        RECT 50.690 499.720 50.970 500.000 ;
    END
  END analog_ctrl[5]
  PIN analog_ctrl[60]
    DIRECTION OUTPUT ;
    USE SIGNAL ;
    ANTENNADIFFAREA 2.673000 ;
    PORT
      LAYER met2 ;
        RECT 328.990 499.720 329.270 500.000 ;
    END
  END analog_ctrl[60]
  PIN analog_ctrl[61]
    DIRECTION OUTPUT ;
    USE SIGNAL ;
    ANTENNADIFFAREA 2.673000 ;
    PORT
      LAYER met2 ;
        RECT 334.050 499.720 334.330 500.000 ;
    END
  END analog_ctrl[61]
  PIN analog_ctrl[62]
    DIRECTION OUTPUT ;
    USE SIGNAL ;
    ANTENNADIFFAREA 2.673000 ;
    PORT
      LAYER met2 ;
        RECT 339.110 499.720 339.390 500.000 ;
    END
  END analog_ctrl[62]
  PIN analog_ctrl[63]
    DIRECTION OUTPUT ;
    USE SIGNAL ;
    ANTENNADIFFAREA 2.673000 ;
    PORT
      LAYER met2 ;
        RECT 344.170 499.720 344.450 500.000 ;
    END
  END analog_ctrl[63]
  PIN analog_ctrl[64]
    DIRECTION OUTPUT ;
    USE SIGNAL ;
    ANTENNADIFFAREA 2.673000 ;
    PORT
      LAYER met2 ;
        RECT 349.230 499.720 349.510 500.000 ;
    END
  END analog_ctrl[64]
  PIN analog_ctrl[65]
    DIRECTION OUTPUT ;
    USE SIGNAL ;
    ANTENNADIFFAREA 2.673000 ;
    PORT
      LAYER met2 ;
        RECT 354.290 499.720 354.570 500.000 ;
    END
  END analog_ctrl[65]
  PIN analog_ctrl[66]
    DIRECTION OUTPUT ;
    USE SIGNAL ;
    ANTENNADIFFAREA 2.673000 ;
    PORT
      LAYER met2 ;
        RECT 359.350 499.720 359.630 500.000 ;
    END
  END analog_ctrl[66]
  PIN analog_ctrl[67]
    DIRECTION OUTPUT ;
    USE SIGNAL ;
    ANTENNADIFFAREA 2.673000 ;
    PORT
      LAYER met2 ;
        RECT 364.410 499.720 364.690 500.000 ;
    END
  END analog_ctrl[67]
  PIN analog_ctrl[68]
    DIRECTION OUTPUT ;
    USE SIGNAL ;
    ANTENNADIFFAREA 2.673000 ;
    PORT
      LAYER met2 ;
        RECT 369.470 499.720 369.750 500.000 ;
    END
  END analog_ctrl[68]
  PIN analog_ctrl[69]
    DIRECTION OUTPUT ;
    USE SIGNAL ;
    ANTENNADIFFAREA 2.673000 ;
    PORT
      LAYER met2 ;
        RECT 374.530 499.720 374.810 500.000 ;
    END
  END analog_ctrl[69]
  PIN analog_ctrl[6]
    DIRECTION OUTPUT ;
    USE SIGNAL ;
    ANTENNADIFFAREA 2.673000 ;
    PORT
      LAYER met2 ;
        RECT 55.750 499.720 56.030 500.000 ;
    END
  END analog_ctrl[6]
  PIN analog_ctrl[70]
    DIRECTION OUTPUT ;
    USE SIGNAL ;
    ANTENNADIFFAREA 2.673000 ;
    PORT
      LAYER met2 ;
        RECT 379.590 499.720 379.870 500.000 ;
    END
  END analog_ctrl[70]
  PIN analog_ctrl[71]
    DIRECTION OUTPUT ;
    USE SIGNAL ;
    ANTENNADIFFAREA 2.673000 ;
    PORT
      LAYER met2 ;
        RECT 384.650 499.720 384.930 500.000 ;
    END
  END analog_ctrl[71]
  PIN analog_ctrl[72]
    DIRECTION OUTPUT ;
    USE SIGNAL ;
    ANTENNADIFFAREA 2.673000 ;
    PORT
      LAYER met2 ;
        RECT 389.710 499.720 389.990 500.000 ;
    END
  END analog_ctrl[72]
  PIN analog_ctrl[73]
    DIRECTION OUTPUT ;
    USE SIGNAL ;
    ANTENNADIFFAREA 2.673000 ;
    PORT
      LAYER met2 ;
        RECT 394.770 499.720 395.050 500.000 ;
    END
  END analog_ctrl[73]
  PIN analog_ctrl[74]
    DIRECTION OUTPUT ;
    USE SIGNAL ;
    ANTENNADIFFAREA 2.673000 ;
    PORT
      LAYER met2 ;
        RECT 399.830 499.720 400.110 500.000 ;
    END
  END analog_ctrl[74]
  PIN analog_ctrl[75]
    DIRECTION OUTPUT ;
    USE SIGNAL ;
    ANTENNADIFFAREA 2.673000 ;
    PORT
      LAYER met2 ;
        RECT 404.890 499.720 405.170 500.000 ;
    END
  END analog_ctrl[75]
  PIN analog_ctrl[76]
    DIRECTION OUTPUT ;
    USE SIGNAL ;
    ANTENNADIFFAREA 2.673000 ;
    PORT
      LAYER met2 ;
        RECT 409.950 499.720 410.230 500.000 ;
    END
  END analog_ctrl[76]
  PIN analog_ctrl[77]
    DIRECTION OUTPUT ;
    USE SIGNAL ;
    ANTENNADIFFAREA 2.673000 ;
    PORT
      LAYER met2 ;
        RECT 415.010 499.720 415.290 500.000 ;
    END
  END analog_ctrl[77]
  PIN analog_ctrl[78]
    DIRECTION OUTPUT ;
    USE SIGNAL ;
    ANTENNADIFFAREA 2.673000 ;
    PORT
      LAYER met2 ;
        RECT 420.070 499.720 420.350 500.000 ;
    END
  END analog_ctrl[78]
  PIN analog_ctrl[79]
    DIRECTION OUTPUT ;
    USE SIGNAL ;
    ANTENNADIFFAREA 2.673000 ;
    PORT
      LAYER met2 ;
        RECT 425.130 499.720 425.410 500.000 ;
    END
  END analog_ctrl[79]
  PIN analog_ctrl[7]
    DIRECTION OUTPUT ;
    USE SIGNAL ;
    ANTENNADIFFAREA 2.673000 ;
    PORT
      LAYER met2 ;
        RECT 60.810 499.720 61.090 500.000 ;
    END
  END analog_ctrl[7]
  PIN analog_ctrl[80]
    DIRECTION OUTPUT ;
    USE SIGNAL ;
    ANTENNADIFFAREA 2.673000 ;
    PORT
      LAYER met2 ;
        RECT 430.190 499.720 430.470 500.000 ;
    END
  END analog_ctrl[80]
  PIN analog_ctrl[81]
    DIRECTION OUTPUT ;
    USE SIGNAL ;
    ANTENNADIFFAREA 2.673000 ;
    PORT
      LAYER met2 ;
        RECT 435.250 499.720 435.530 500.000 ;
    END
  END analog_ctrl[81]
  PIN analog_ctrl[82]
    DIRECTION OUTPUT ;
    USE SIGNAL ;
    ANTENNADIFFAREA 2.673000 ;
    PORT
      LAYER met2 ;
        RECT 440.310 499.720 440.590 500.000 ;
    END
  END analog_ctrl[82]
  PIN analog_ctrl[83]
    DIRECTION OUTPUT ;
    USE SIGNAL ;
    ANTENNADIFFAREA 2.673000 ;
    PORT
      LAYER met2 ;
        RECT 445.370 499.720 445.650 500.000 ;
    END
  END analog_ctrl[83]
  PIN analog_ctrl[84]
    DIRECTION OUTPUT ;
    USE SIGNAL ;
    ANTENNADIFFAREA 2.673000 ;
    PORT
      LAYER met2 ;
        RECT 450.430 499.720 450.710 500.000 ;
    END
  END analog_ctrl[84]
  PIN analog_ctrl[85]
    DIRECTION OUTPUT ;
    USE SIGNAL ;
    ANTENNADIFFAREA 2.673000 ;
    PORT
      LAYER met2 ;
        RECT 455.490 499.720 455.770 500.000 ;
    END
  END analog_ctrl[85]
  PIN analog_ctrl[86]
    DIRECTION OUTPUT ;
    USE SIGNAL ;
    ANTENNADIFFAREA 2.673000 ;
    PORT
      LAYER met2 ;
        RECT 460.550 499.720 460.830 500.000 ;
    END
  END analog_ctrl[86]
  PIN analog_ctrl[87]
    DIRECTION OUTPUT ;
    USE SIGNAL ;
    ANTENNADIFFAREA 2.673000 ;
    PORT
      LAYER met2 ;
        RECT 465.610 499.720 465.890 500.000 ;
    END
  END analog_ctrl[87]
  PIN analog_ctrl[88]
    DIRECTION OUTPUT ;
    USE SIGNAL ;
    ANTENNADIFFAREA 2.673000 ;
    PORT
      LAYER met2 ;
        RECT 470.670 499.720 470.950 500.000 ;
    END
  END analog_ctrl[88]
  PIN analog_ctrl[89]
    DIRECTION OUTPUT ;
    USE SIGNAL ;
    ANTENNADIFFAREA 2.673000 ;
    PORT
      LAYER met2 ;
        RECT 475.730 499.720 476.010 500.000 ;
    END
  END analog_ctrl[89]
  PIN analog_ctrl[8]
    DIRECTION OUTPUT ;
    USE SIGNAL ;
    ANTENNADIFFAREA 2.673000 ;
    PORT
      LAYER met2 ;
        RECT 65.870 499.720 66.150 500.000 ;
    END
  END analog_ctrl[8]
  PIN analog_ctrl[90]
    DIRECTION OUTPUT ;
    USE SIGNAL ;
    ANTENNADIFFAREA 2.673000 ;
    PORT
      LAYER met2 ;
        RECT 480.790 499.720 481.070 500.000 ;
    END
  END analog_ctrl[90]
  PIN analog_ctrl[91]
    DIRECTION OUTPUT ;
    USE SIGNAL ;
    ANTENNADIFFAREA 2.673000 ;
    PORT
      LAYER met2 ;
        RECT 485.850 499.720 486.130 500.000 ;
    END
  END analog_ctrl[91]
  PIN analog_ctrl[92]
    DIRECTION OUTPUT ;
    USE SIGNAL ;
    ANTENNADIFFAREA 2.673000 ;
    PORT
      LAYER met2 ;
        RECT 490.910 499.720 491.190 500.000 ;
    END
  END analog_ctrl[92]
  PIN analog_ctrl[93]
    DIRECTION OUTPUT ;
    USE SIGNAL ;
    ANTENNADIFFAREA 2.673000 ;
    PORT
      LAYER met2 ;
        RECT 495.970 499.720 496.250 500.000 ;
    END
  END analog_ctrl[93]
  PIN analog_ctrl[94]
    DIRECTION OUTPUT ;
    USE SIGNAL ;
    ANTENNADIFFAREA 2.673000 ;
    PORT
      LAYER met2 ;
        RECT 501.030 499.720 501.310 500.000 ;
    END
  END analog_ctrl[94]
  PIN analog_ctrl[95]
    DIRECTION OUTPUT ;
    USE SIGNAL ;
    ANTENNADIFFAREA 2.673000 ;
    PORT
      LAYER met2 ;
        RECT 506.090 499.720 506.370 500.000 ;
    END
  END analog_ctrl[95]
  PIN analog_ctrl[96]
    DIRECTION OUTPUT ;
    USE SIGNAL ;
    ANTENNADIFFAREA 2.673000 ;
    PORT
      LAYER met2 ;
        RECT 511.150 499.720 511.430 500.000 ;
    END
  END analog_ctrl[96]
  PIN analog_ctrl[97]
    DIRECTION OUTPUT ;
    USE SIGNAL ;
    ANTENNADIFFAREA 2.673000 ;
    PORT
      LAYER met2 ;
        RECT 516.210 499.720 516.490 500.000 ;
    END
  END analog_ctrl[97]
  PIN analog_ctrl[98]
    DIRECTION OUTPUT ;
    USE SIGNAL ;
    ANTENNADIFFAREA 2.673000 ;
    PORT
      LAYER met2 ;
        RECT 521.270 499.720 521.550 500.000 ;
    END
  END analog_ctrl[98]
  PIN analog_ctrl[99]
    DIRECTION OUTPUT ;
    USE SIGNAL ;
    ANTENNADIFFAREA 2.673000 ;
    PORT
      LAYER met2 ;
        RECT 526.330 499.720 526.610 500.000 ;
    END
  END analog_ctrl[99]
  PIN analog_ctrl[9]
    DIRECTION OUTPUT ;
    USE SIGNAL ;
    ANTENNADIFFAREA 2.673000 ;
    PORT
      LAYER met2 ;
        RECT 70.930 499.720 71.210 500.000 ;
    END
  END analog_ctrl[9]
  PIN io_in[0]
    DIRECTION INPUT ;
    USE SIGNAL ;
    PORT
      LAYER met3 ;
        RECT 0.000 61.240 0.600 61.840 ;
    END
  END io_in[0]
  PIN io_in[10]
    DIRECTION INPUT ;
    USE SIGNAL ;
    PORT
      LAYER met3 ;
        RECT 0.000 102.040 0.600 102.640 ;
    END
  END io_in[10]
  PIN io_in[11]
    DIRECTION INPUT ;
    USE SIGNAL ;
    PORT
      LAYER met3 ;
        RECT 0.000 106.120 0.600 106.720 ;
    END
  END io_in[11]
  PIN io_in[12]
    DIRECTION INPUT ;
    USE SIGNAL ;
    PORT
      LAYER met3 ;
        RECT 0.000 110.200 0.600 110.800 ;
    END
  END io_in[12]
  PIN io_in[13]
    DIRECTION INPUT ;
    USE SIGNAL ;
    ANTENNAGATEAREA 0.631200 ;
    ANTENNADIFFAREA 0.434700 ;
    PORT
      LAYER met3 ;
        RECT 0.000 114.280 0.600 114.880 ;
    END
  END io_in[13]
  PIN io_in[14]
    DIRECTION INPUT ;
    USE SIGNAL ;
    ANTENNAGATEAREA 0.631200 ;
    ANTENNADIFFAREA 0.434700 ;
    PORT
      LAYER met3 ;
        RECT 0.000 118.360 0.600 118.960 ;
    END
  END io_in[14]
  PIN io_in[15]
    DIRECTION INPUT ;
    USE SIGNAL ;
    PORT
      LAYER met3 ;
        RECT 0.000 122.440 0.600 123.040 ;
    END
  END io_in[15]
  PIN io_in[16]
    DIRECTION INPUT ;
    USE SIGNAL ;
    ANTENNAGATEAREA 0.647700 ;
    ANTENNADIFFAREA 0.434700 ;
    PORT
      LAYER met3 ;
        RECT 0.000 126.520 0.600 127.120 ;
    END
  END io_in[16]
  PIN io_in[17]
    DIRECTION INPUT ;
    USE SIGNAL ;
    PORT
      LAYER met3 ;
        RECT 0.000 130.600 0.600 131.200 ;
    END
  END io_in[17]
  PIN io_in[18]
    DIRECTION INPUT ;
    USE SIGNAL ;
    PORT
      LAYER met3 ;
        RECT 0.000 134.680 0.600 135.280 ;
    END
  END io_in[18]
  PIN io_in[19]
    DIRECTION INPUT ;
    USE SIGNAL ;
    PORT
      LAYER met3 ;
        RECT 0.000 138.760 0.600 139.360 ;
    END
  END io_in[19]
  PIN io_in[1]
    DIRECTION INPUT ;
    USE SIGNAL ;
    PORT
      LAYER met3 ;
        RECT 0.000 65.320 0.600 65.920 ;
    END
  END io_in[1]
  PIN io_in[20]
    DIRECTION INPUT ;
    USE SIGNAL ;
    PORT
      LAYER met3 ;
        RECT 0.000 142.840 0.600 143.440 ;
    END
  END io_in[20]
  PIN io_in[21]
    DIRECTION INPUT ;
    USE SIGNAL ;
    PORT
      LAYER met3 ;
        RECT 0.000 146.920 0.600 147.520 ;
    END
  END io_in[21]
  PIN io_in[22]
    DIRECTION INPUT ;
    USE SIGNAL ;
    PORT
      LAYER met3 ;
        RECT 0.000 151.000 0.600 151.600 ;
    END
  END io_in[22]
  PIN io_in[23]
    DIRECTION INPUT ;
    USE SIGNAL ;
    PORT
      LAYER met3 ;
        RECT 0.000 155.080 0.600 155.680 ;
    END
  END io_in[23]
  PIN io_in[24]
    DIRECTION INPUT ;
    USE SIGNAL ;
    PORT
      LAYER met3 ;
        RECT 0.000 159.160 0.600 159.760 ;
    END
  END io_in[24]
  PIN io_in[25]
    DIRECTION INPUT ;
    USE SIGNAL ;
    PORT
      LAYER met3 ;
        RECT 0.000 163.240 0.600 163.840 ;
    END
  END io_in[25]
  PIN io_in[26]
    DIRECTION INPUT ;
    USE SIGNAL ;
    PORT
      LAYER met3 ;
        RECT 0.000 167.320 0.600 167.920 ;
    END
  END io_in[26]
  PIN io_in[27]
    DIRECTION INPUT ;
    USE SIGNAL ;
    PORT
      LAYER met3 ;
        RECT 0.000 171.400 0.600 172.000 ;
    END
  END io_in[27]
  PIN io_in[28]
    DIRECTION INPUT ;
    USE SIGNAL ;
    ANTENNAGATEAREA 0.647700 ;
    ANTENNADIFFAREA 0.434700 ;
    PORT
      LAYER met3 ;
        RECT 0.000 175.480 0.600 176.080 ;
    END
  END io_in[28]
  PIN io_in[29]
    DIRECTION INPUT ;
    USE SIGNAL ;
    ANTENNAGATEAREA 0.593700 ;
    ANTENNADIFFAREA 0.434700 ;
    PORT
      LAYER met3 ;
        RECT 0.000 179.560 0.600 180.160 ;
    END
  END io_in[29]
  PIN io_in[2]
    DIRECTION INPUT ;
    USE SIGNAL ;
    PORT
      LAYER met3 ;
        RECT 0.000 69.400 0.600 70.000 ;
    END
  END io_in[2]
  PIN io_in[30]
    DIRECTION INPUT ;
    USE SIGNAL ;
    ANTENNAGATEAREA 0.593700 ;
    ANTENNADIFFAREA 0.434700 ;
    PORT
      LAYER met3 ;
        RECT 0.000 183.640 0.600 184.240 ;
    END
  END io_in[30]
  PIN io_in[3]
    DIRECTION INPUT ;
    USE SIGNAL ;
    PORT
      LAYER met3 ;
        RECT 0.000 73.480 0.600 74.080 ;
    END
  END io_in[3]
  PIN io_in[4]
    DIRECTION INPUT ;
    USE SIGNAL ;
    PORT
      LAYER met3 ;
        RECT 0.000 77.560 0.600 78.160 ;
    END
  END io_in[4]
  PIN io_in[5]
    DIRECTION INPUT ;
    USE SIGNAL ;
    PORT
      LAYER met3 ;
        RECT 0.000 81.640 0.600 82.240 ;
    END
  END io_in[5]
  PIN io_in[6]
    DIRECTION INPUT ;
    USE SIGNAL ;
    PORT
      LAYER met3 ;
        RECT 0.000 85.720 0.600 86.320 ;
    END
  END io_in[6]
  PIN io_in[7]
    DIRECTION INPUT ;
    USE SIGNAL ;
    PORT
      LAYER met3 ;
        RECT 0.000 89.800 0.600 90.400 ;
    END
  END io_in[7]
  PIN io_in[8]
    DIRECTION INPUT ;
    USE SIGNAL ;
    PORT
      LAYER met3 ;
        RECT 0.000 93.880 0.600 94.480 ;
    END
  END io_in[8]
  PIN io_in[9]
    DIRECTION INPUT ;
    USE SIGNAL ;
    PORT
      LAYER met3 ;
        RECT 0.000 97.960 0.600 98.560 ;
    END
  END io_in[9]
  PIN io_oeb[0]
    DIRECTION OUTPUT ;
    USE SIGNAL ;
    PORT
      LAYER met3 ;
        RECT 0.000 314.200 0.600 314.800 ;
    END
  END io_oeb[0]
  PIN io_oeb[10]
    DIRECTION OUTPUT ;
    USE SIGNAL ;
    PORT
      LAYER met3 ;
        RECT 0.000 355.000 0.600 355.600 ;
    END
  END io_oeb[10]
  PIN io_oeb[11]
    DIRECTION OUTPUT ;
    USE SIGNAL ;
    PORT
      LAYER met3 ;
        RECT 0.000 359.080 0.600 359.680 ;
    END
  END io_oeb[11]
  PIN io_oeb[12]
    DIRECTION OUTPUT ;
    USE SIGNAL ;
    PORT
      LAYER met3 ;
        RECT 0.000 363.160 0.600 363.760 ;
    END
  END io_oeb[12]
  PIN io_oeb[13]
    DIRECTION OUTPUT ;
    USE SIGNAL ;
    ANTENNADIFFAREA 2.673000 ;
    PORT
      LAYER met3 ;
        RECT 0.000 367.240 0.600 367.840 ;
    END
  END io_oeb[13]
  PIN io_oeb[14]
    DIRECTION OUTPUT ;
    USE SIGNAL ;
    ANTENNADIFFAREA 2.673000 ;
    PORT
      LAYER met3 ;
        RECT 0.000 371.320 0.600 371.920 ;
    END
  END io_oeb[14]
  PIN io_oeb[15]
    DIRECTION OUTPUT ;
    USE SIGNAL ;
    PORT
      LAYER met3 ;
        RECT 0.000 375.400 0.600 376.000 ;
    END
  END io_oeb[15]
  PIN io_oeb[16]
    DIRECTION OUTPUT ;
    USE SIGNAL ;
    PORT
      LAYER met3 ;
        RECT 0.000 379.480 0.600 380.080 ;
    END
  END io_oeb[16]
  PIN io_oeb[17]
    DIRECTION OUTPUT ;
    USE SIGNAL ;
    PORT
      LAYER met3 ;
        RECT 0.000 383.560 0.600 384.160 ;
    END
  END io_oeb[17]
  PIN io_oeb[18]
    DIRECTION OUTPUT ;
    USE SIGNAL ;
    PORT
      LAYER met3 ;
        RECT 0.000 387.640 0.600 388.240 ;
    END
  END io_oeb[18]
  PIN io_oeb[19]
    DIRECTION OUTPUT ;
    USE SIGNAL ;
    PORT
      LAYER met3 ;
        RECT 0.000 391.720 0.600 392.320 ;
    END
  END io_oeb[19]
  PIN io_oeb[1]
    DIRECTION OUTPUT ;
    USE SIGNAL ;
    PORT
      LAYER met3 ;
        RECT 0.000 318.280 0.600 318.880 ;
    END
  END io_oeb[1]
  PIN io_oeb[20]
    DIRECTION OUTPUT ;
    USE SIGNAL ;
    PORT
      LAYER met3 ;
        RECT 0.000 395.800 0.600 396.400 ;
    END
  END io_oeb[20]
  PIN io_oeb[21]
    DIRECTION OUTPUT ;
    USE SIGNAL ;
    PORT
      LAYER met3 ;
        RECT 0.000 399.880 0.600 400.480 ;
    END
  END io_oeb[21]
  PIN io_oeb[22]
    DIRECTION OUTPUT ;
    USE SIGNAL ;
    PORT
      LAYER met3 ;
        RECT 0.000 403.960 0.600 404.560 ;
    END
  END io_oeb[22]
  PIN io_oeb[23]
    DIRECTION OUTPUT ;
    USE SIGNAL ;
    PORT
      LAYER met3 ;
        RECT 0.000 408.040 0.600 408.640 ;
    END
  END io_oeb[23]
  PIN io_oeb[24]
    DIRECTION OUTPUT ;
    USE SIGNAL ;
    PORT
      LAYER met3 ;
        RECT 0.000 412.120 0.600 412.720 ;
    END
  END io_oeb[24]
  PIN io_oeb[25]
    DIRECTION OUTPUT ;
    USE SIGNAL ;
    PORT
      LAYER met3 ;
        RECT 0.000 416.200 0.600 416.800 ;
    END
  END io_oeb[25]
  PIN io_oeb[26]
    DIRECTION OUTPUT ;
    USE SIGNAL ;
    PORT
      LAYER met3 ;
        RECT 0.000 420.280 0.600 420.880 ;
    END
  END io_oeb[26]
  PIN io_oeb[27]
    DIRECTION OUTPUT ;
    USE SIGNAL ;
    PORT
      LAYER met3 ;
        RECT 0.000 424.360 0.600 424.960 ;
    END
  END io_oeb[27]
  PIN io_oeb[28]
    DIRECTION OUTPUT ;
    USE SIGNAL ;
    ANTENNADIFFAREA 2.673000 ;
    PORT
      LAYER met3 ;
        RECT 0.000 428.440 0.600 429.040 ;
    END
  END io_oeb[28]
  PIN io_oeb[29]
    DIRECTION OUTPUT ;
    USE SIGNAL ;
    ANTENNADIFFAREA 2.673000 ;
    PORT
      LAYER met3 ;
        RECT 0.000 432.520 0.600 433.120 ;
    END
  END io_oeb[29]
  PIN io_oeb[2]
    DIRECTION OUTPUT ;
    USE SIGNAL ;
    PORT
      LAYER met3 ;
        RECT 0.000 322.360 0.600 322.960 ;
    END
  END io_oeb[2]
  PIN io_oeb[30]
    DIRECTION OUTPUT ;
    USE SIGNAL ;
    ANTENNADIFFAREA 2.673000 ;
    PORT
      LAYER met3 ;
        RECT 0.000 436.600 0.600 437.200 ;
    END
  END io_oeb[30]
  PIN io_oeb[3]
    DIRECTION OUTPUT ;
    USE SIGNAL ;
    PORT
      LAYER met3 ;
        RECT 0.000 326.440 0.600 327.040 ;
    END
  END io_oeb[3]
  PIN io_oeb[4]
    DIRECTION OUTPUT ;
    USE SIGNAL ;
    PORT
      LAYER met3 ;
        RECT 0.000 330.520 0.600 331.120 ;
    END
  END io_oeb[4]
  PIN io_oeb[5]
    DIRECTION OUTPUT ;
    USE SIGNAL ;
    PORT
      LAYER met3 ;
        RECT 0.000 334.600 0.600 335.200 ;
    END
  END io_oeb[5]
  PIN io_oeb[6]
    DIRECTION OUTPUT ;
    USE SIGNAL ;
    PORT
      LAYER met3 ;
        RECT 0.000 338.680 0.600 339.280 ;
    END
  END io_oeb[6]
  PIN io_oeb[7]
    DIRECTION OUTPUT ;
    USE SIGNAL ;
    PORT
      LAYER met3 ;
        RECT 0.000 342.760 0.600 343.360 ;
    END
  END io_oeb[7]
  PIN io_oeb[8]
    DIRECTION OUTPUT ;
    USE SIGNAL ;
    PORT
      LAYER met3 ;
        RECT 0.000 346.840 0.600 347.440 ;
    END
  END io_oeb[8]
  PIN io_oeb[9]
    DIRECTION OUTPUT ;
    USE SIGNAL ;
    PORT
      LAYER met3 ;
        RECT 0.000 350.920 0.600 351.520 ;
    END
  END io_oeb[9]
  PIN io_out[0]
    DIRECTION OUTPUT ;
    USE SIGNAL ;
    PORT
      LAYER met3 ;
        RECT 0.000 187.720 0.600 188.320 ;
    END
  END io_out[0]
  PIN io_out[10]
    DIRECTION OUTPUT ;
    USE SIGNAL ;
    ANTENNADIFFAREA 2.673000 ;
    PORT
      LAYER met3 ;
        RECT 0.000 228.520 0.600 229.120 ;
    END
  END io_out[10]
  PIN io_out[11]
    DIRECTION OUTPUT ;
    USE SIGNAL ;
    PORT
      LAYER met3 ;
        RECT 0.000 232.600 0.600 233.200 ;
    END
  END io_out[11]
  PIN io_out[12]
    DIRECTION OUTPUT ;
    USE SIGNAL ;
    ANTENNADIFFAREA 2.673000 ;
    PORT
      LAYER met3 ;
        RECT 0.000 236.680 0.600 237.280 ;
    END
  END io_out[12]
  PIN io_out[13]
    DIRECTION OUTPUT ;
    USE SIGNAL ;
    ANTENNADIFFAREA 2.673000 ;
    PORT
      LAYER met3 ;
        RECT 0.000 240.760 0.600 241.360 ;
    END
  END io_out[13]
  PIN io_out[14]
    DIRECTION OUTPUT ;
    USE SIGNAL ;
    ANTENNADIFFAREA 2.673000 ;
    PORT
      LAYER met3 ;
        RECT 0.000 244.840 0.600 245.440 ;
    END
  END io_out[14]
  PIN io_out[15]
    DIRECTION OUTPUT ;
    USE SIGNAL ;
    ANTENNADIFFAREA 2.673000 ;
    PORT
      LAYER met3 ;
        RECT 0.000 248.920 0.600 249.520 ;
    END
  END io_out[15]
  PIN io_out[16]
    DIRECTION OUTPUT ;
    USE SIGNAL ;
    PORT
      LAYER met3 ;
        RECT 0.000 253.000 0.600 253.600 ;
    END
  END io_out[16]
  PIN io_out[17]
    DIRECTION OUTPUT ;
    USE SIGNAL ;
    ANTENNADIFFAREA 2.673000 ;
    PORT
      LAYER met3 ;
        RECT 0.000 257.080 0.600 257.680 ;
    END
  END io_out[17]
  PIN io_out[18]
    DIRECTION OUTPUT ;
    USE SIGNAL ;
    ANTENNADIFFAREA 2.673000 ;
    PORT
      LAYER met3 ;
        RECT 0.000 261.160 0.600 261.760 ;
    END
  END io_out[18]
  PIN io_out[19]
    DIRECTION OUTPUT ;
    USE SIGNAL ;
    ANTENNADIFFAREA 2.673000 ;
    PORT
      LAYER met3 ;
        RECT 0.000 265.240 0.600 265.840 ;
    END
  END io_out[19]
  PIN io_out[1]
    DIRECTION OUTPUT ;
    USE SIGNAL ;
    PORT
      LAYER met3 ;
        RECT 0.000 191.800 0.600 192.400 ;
    END
  END io_out[1]
  PIN io_out[20]
    DIRECTION OUTPUT ;
    USE SIGNAL ;
    PORT
      LAYER met3 ;
        RECT 0.000 269.320 0.600 269.920 ;
    END
  END io_out[20]
  PIN io_out[21]
    DIRECTION OUTPUT ;
    USE SIGNAL ;
    PORT
      LAYER met3 ;
        RECT 0.000 273.400 0.600 274.000 ;
    END
  END io_out[21]
  PIN io_out[22]
    DIRECTION OUTPUT ;
    USE SIGNAL ;
    PORT
      LAYER met3 ;
        RECT 0.000 277.480 0.600 278.080 ;
    END
  END io_out[22]
  PIN io_out[23]
    DIRECTION OUTPUT ;
    USE SIGNAL ;
    ANTENNADIFFAREA 2.673000 ;
    PORT
      LAYER met3 ;
        RECT 0.000 281.560 0.600 282.160 ;
    END
  END io_out[23]
  PIN io_out[24]
    DIRECTION OUTPUT ;
    USE SIGNAL ;
    PORT
      LAYER met3 ;
        RECT 0.000 285.640 0.600 286.240 ;
    END
  END io_out[24]
  PIN io_out[25]
    DIRECTION OUTPUT ;
    USE SIGNAL ;
    PORT
      LAYER met3 ;
        RECT 0.000 289.720 0.600 290.320 ;
    END
  END io_out[25]
  PIN io_out[26]
    DIRECTION OUTPUT ;
    USE SIGNAL ;
    PORT
      LAYER met3 ;
        RECT 0.000 293.800 0.600 294.400 ;
    END
  END io_out[26]
  PIN io_out[27]
    DIRECTION OUTPUT ;
    USE SIGNAL ;
    PORT
      LAYER met3 ;
        RECT 0.000 297.880 0.600 298.480 ;
    END
  END io_out[27]
  PIN io_out[28]
    DIRECTION OUTPUT ;
    USE SIGNAL ;
    ANTENNADIFFAREA 2.673000 ;
    PORT
      LAYER met3 ;
        RECT 0.000 301.960 0.600 302.560 ;
    END
  END io_out[28]
  PIN io_out[29]
    DIRECTION OUTPUT ;
    USE SIGNAL ;
    ANTENNADIFFAREA 2.673000 ;
    PORT
      LAYER met3 ;
        RECT 0.000 306.040 0.600 306.640 ;
    END
  END io_out[29]
  PIN io_out[2]
    DIRECTION OUTPUT ;
    USE SIGNAL ;
    PORT
      LAYER met3 ;
        RECT 0.000 195.880 0.600 196.480 ;
    END
  END io_out[2]
  PIN io_out[30]
    DIRECTION OUTPUT ;
    USE SIGNAL ;
    ANTENNADIFFAREA 2.673000 ;
    PORT
      LAYER met3 ;
        RECT 0.000 310.120 0.600 310.720 ;
    END
  END io_out[30]
  PIN io_out[3]
    DIRECTION OUTPUT ;
    USE SIGNAL ;
    PORT
      LAYER met3 ;
        RECT 0.000 199.960 0.600 200.560 ;
    END
  END io_out[3]
  PIN io_out[4]
    DIRECTION OUTPUT ;
    USE SIGNAL ;
    PORT
      LAYER met3 ;
        RECT 0.000 204.040 0.600 204.640 ;
    END
  END io_out[4]
  PIN io_out[5]
    DIRECTION OUTPUT ;
    USE SIGNAL ;
    PORT
      LAYER met3 ;
        RECT 0.000 208.120 0.600 208.720 ;
    END
  END io_out[5]
  PIN io_out[6]
    DIRECTION OUTPUT ;
    USE SIGNAL ;
    PORT
      LAYER met3 ;
        RECT 0.000 212.200 0.600 212.800 ;
    END
  END io_out[6]
  PIN io_out[7]
    DIRECTION OUTPUT ;
    USE SIGNAL ;
    PORT
      LAYER met3 ;
        RECT 0.000 216.280 0.600 216.880 ;
    END
  END io_out[7]
  PIN io_out[8]
    DIRECTION OUTPUT ;
    USE SIGNAL ;
    PORT
      LAYER met3 ;
        RECT 0.000 220.360 0.600 220.960 ;
    END
  END io_out[8]
  PIN io_out[9]
    DIRECTION OUTPUT ;
    USE SIGNAL ;
    ANTENNADIFFAREA 2.673000 ;
    PORT
      LAYER met3 ;
        RECT 0.000 224.440 0.600 225.040 ;
    END
  END io_out[9]
  PIN sram_ack_i
    DIRECTION INPUT ;
    USE SIGNAL ;
    ANTENNAGATEAREA 0.647700 ;
    ANTENNADIFFAREA 0.434700 ;
    PORT
      LAYER met3 ;
        RECT 1199.400 39.480 1200.000 40.080 ;
    END
  END sram_ack_i
  PIN sram_adr_o[0]
    DIRECTION OUTPUT ;
    USE SIGNAL ;
    ANTENNADIFFAREA 2.673000 ;
    PORT
      LAYER met3 ;
        RECT 1199.400 55.800 1200.000 56.400 ;
    END
  END sram_adr_o[0]
  PIN sram_adr_o[10]
    DIRECTION OUTPUT ;
    USE SIGNAL ;
    ANTENNADIFFAREA 2.673000 ;
    PORT
      LAYER met3 ;
        RECT 1199.400 194.520 1200.000 195.120 ;
    END
  END sram_adr_o[10]
  PIN sram_adr_o[11]
    DIRECTION OUTPUT ;
    USE SIGNAL ;
    ANTENNADIFFAREA 2.673000 ;
    PORT
      LAYER met3 ;
        RECT 1199.400 206.760 1200.000 207.360 ;
    END
  END sram_adr_o[11]
  PIN sram_adr_o[12]
    DIRECTION OUTPUT ;
    USE SIGNAL ;
    ANTENNADIFFAREA 2.673000 ;
    PORT
      LAYER met3 ;
        RECT 1199.400 219.000 1200.000 219.600 ;
    END
  END sram_adr_o[12]
  PIN sram_adr_o[13]
    DIRECTION OUTPUT ;
    USE SIGNAL ;
    ANTENNADIFFAREA 2.673000 ;
    PORT
      LAYER met3 ;
        RECT 1199.400 231.240 1200.000 231.840 ;
    END
  END sram_adr_o[13]
  PIN sram_adr_o[14]
    DIRECTION OUTPUT ;
    USE SIGNAL ;
    ANTENNADIFFAREA 2.673000 ;
    PORT
      LAYER met3 ;
        RECT 1199.400 243.480 1200.000 244.080 ;
    END
  END sram_adr_o[14]
  PIN sram_adr_o[15]
    DIRECTION OUTPUT ;
    USE SIGNAL ;
    ANTENNADIFFAREA 2.673000 ;
    PORT
      LAYER met3 ;
        RECT 1199.400 255.720 1200.000 256.320 ;
    END
  END sram_adr_o[15]
  PIN sram_adr_o[16]
    DIRECTION OUTPUT ;
    USE SIGNAL ;
    ANTENNADIFFAREA 2.673000 ;
    PORT
      LAYER met3 ;
        RECT 1199.400 267.960 1200.000 268.560 ;
    END
  END sram_adr_o[16]
  PIN sram_adr_o[17]
    DIRECTION OUTPUT ;
    USE SIGNAL ;
    ANTENNADIFFAREA 2.673000 ;
    PORT
      LAYER met3 ;
        RECT 1199.400 280.200 1200.000 280.800 ;
    END
  END sram_adr_o[17]
  PIN sram_adr_o[18]
    DIRECTION OUTPUT ;
    USE SIGNAL ;
    ANTENNADIFFAREA 2.673000 ;
    PORT
      LAYER met3 ;
        RECT 1199.400 292.440 1200.000 293.040 ;
    END
  END sram_adr_o[18]
  PIN sram_adr_o[19]
    DIRECTION OUTPUT ;
    USE SIGNAL ;
    ANTENNADIFFAREA 2.673000 ;
    PORT
      LAYER met3 ;
        RECT 1199.400 304.680 1200.000 305.280 ;
    END
  END sram_adr_o[19]
  PIN sram_adr_o[1]
    DIRECTION OUTPUT ;
    USE SIGNAL ;
    ANTENNADIFFAREA 2.673000 ;
    PORT
      LAYER met3 ;
        RECT 1199.400 72.120 1200.000 72.720 ;
    END
  END sram_adr_o[1]
  PIN sram_adr_o[20]
    DIRECTION OUTPUT ;
    USE SIGNAL ;
    ANTENNADIFFAREA 2.673000 ;
    PORT
      LAYER met3 ;
        RECT 1199.400 316.920 1200.000 317.520 ;
    END
  END sram_adr_o[20]
  PIN sram_adr_o[21]
    DIRECTION OUTPUT ;
    USE SIGNAL ;
    ANTENNADIFFAREA 2.673000 ;
    PORT
      LAYER met3 ;
        RECT 1199.400 329.160 1200.000 329.760 ;
    END
  END sram_adr_o[21]
  PIN sram_adr_o[22]
    DIRECTION OUTPUT ;
    USE SIGNAL ;
    ANTENNADIFFAREA 2.673000 ;
    PORT
      LAYER met3 ;
        RECT 1199.400 341.400 1200.000 342.000 ;
    END
  END sram_adr_o[22]
  PIN sram_adr_o[23]
    DIRECTION OUTPUT ;
    USE SIGNAL ;
    ANTENNADIFFAREA 2.673000 ;
    PORT
      LAYER met3 ;
        RECT 1199.400 353.640 1200.000 354.240 ;
    END
  END sram_adr_o[23]
  PIN sram_adr_o[24]
    DIRECTION OUTPUT ;
    USE SIGNAL ;
    ANTENNADIFFAREA 2.673000 ;
    PORT
      LAYER met3 ;
        RECT 1199.400 365.880 1200.000 366.480 ;
    END
  END sram_adr_o[24]
  PIN sram_adr_o[25]
    DIRECTION OUTPUT ;
    USE SIGNAL ;
    ANTENNADIFFAREA 2.673000 ;
    PORT
      LAYER met3 ;
        RECT 1199.400 378.120 1200.000 378.720 ;
    END
  END sram_adr_o[25]
  PIN sram_adr_o[26]
    DIRECTION OUTPUT ;
    USE SIGNAL ;
    ANTENNADIFFAREA 2.673000 ;
    PORT
      LAYER met3 ;
        RECT 1199.400 390.360 1200.000 390.960 ;
    END
  END sram_adr_o[26]
  PIN sram_adr_o[27]
    DIRECTION OUTPUT ;
    USE SIGNAL ;
    ANTENNADIFFAREA 2.673000 ;
    PORT
      LAYER met3 ;
        RECT 1199.400 402.600 1200.000 403.200 ;
    END
  END sram_adr_o[27]
  PIN sram_adr_o[28]
    DIRECTION OUTPUT ;
    USE SIGNAL ;
    ANTENNADIFFAREA 2.673000 ;
    PORT
      LAYER met3 ;
        RECT 1199.400 414.840 1200.000 415.440 ;
    END
  END sram_adr_o[28]
  PIN sram_adr_o[29]
    DIRECTION OUTPUT ;
    USE SIGNAL ;
    ANTENNADIFFAREA 2.673000 ;
    PORT
      LAYER met3 ;
        RECT 1199.400 427.080 1200.000 427.680 ;
    END
  END sram_adr_o[29]
  PIN sram_adr_o[2]
    DIRECTION OUTPUT ;
    USE SIGNAL ;
    ANTENNADIFFAREA 2.673000 ;
    PORT
      LAYER met3 ;
        RECT 1199.400 88.440 1200.000 89.040 ;
    END
  END sram_adr_o[2]
  PIN sram_adr_o[30]
    DIRECTION OUTPUT ;
    USE SIGNAL ;
    ANTENNADIFFAREA 2.673000 ;
    PORT
      LAYER met3 ;
        RECT 1199.400 439.320 1200.000 439.920 ;
    END
  END sram_adr_o[30]
  PIN sram_adr_o[31]
    DIRECTION OUTPUT ;
    USE SIGNAL ;
    ANTENNADIFFAREA 2.673000 ;
    PORT
      LAYER met3 ;
        RECT 1199.400 451.560 1200.000 452.160 ;
    END
  END sram_adr_o[31]
  PIN sram_adr_o[3]
    DIRECTION OUTPUT ;
    USE SIGNAL ;
    ANTENNADIFFAREA 2.673000 ;
    PORT
      LAYER met3 ;
        RECT 1199.400 104.760 1200.000 105.360 ;
    END
  END sram_adr_o[3]
  PIN sram_adr_o[4]
    DIRECTION OUTPUT ;
    USE SIGNAL ;
    ANTENNADIFFAREA 2.673000 ;
    PORT
      LAYER met3 ;
        RECT 1199.400 121.080 1200.000 121.680 ;
    END
  END sram_adr_o[4]
  PIN sram_adr_o[5]
    DIRECTION OUTPUT ;
    USE SIGNAL ;
    ANTENNADIFFAREA 2.673000 ;
    PORT
      LAYER met3 ;
        RECT 1199.400 133.320 1200.000 133.920 ;
    END
  END sram_adr_o[5]
  PIN sram_adr_o[6]
    DIRECTION OUTPUT ;
    USE SIGNAL ;
    ANTENNADIFFAREA 2.673000 ;
    PORT
      LAYER met3 ;
        RECT 1199.400 145.560 1200.000 146.160 ;
    END
  END sram_adr_o[6]
  PIN sram_adr_o[7]
    DIRECTION OUTPUT ;
    USE SIGNAL ;
    ANTENNADIFFAREA 2.673000 ;
    PORT
      LAYER met3 ;
        RECT 1199.400 157.800 1200.000 158.400 ;
    END
  END sram_adr_o[7]
  PIN sram_adr_o[8]
    DIRECTION OUTPUT ;
    USE SIGNAL ;
    ANTENNADIFFAREA 2.673000 ;
    PORT
      LAYER met3 ;
        RECT 1199.400 170.040 1200.000 170.640 ;
    END
  END sram_adr_o[8]
  PIN sram_adr_o[9]
    DIRECTION OUTPUT ;
    USE SIGNAL ;
    ANTENNADIFFAREA 2.673000 ;
    PORT
      LAYER met3 ;
        RECT 1199.400 182.280 1200.000 182.880 ;
    END
  END sram_adr_o[9]
  PIN sram_cyc_o
    DIRECTION OUTPUT ;
    USE SIGNAL ;
    ANTENNADIFFAREA 2.673000 ;
    PORT
      LAYER met3 ;
        RECT 1199.400 43.560 1200.000 44.160 ;
    END
  END sram_cyc_o
  PIN sram_dat_i[0]
    DIRECTION INPUT ;
    USE SIGNAL ;
    ANTENNAGATEAREA 0.647700 ;
    ANTENNADIFFAREA 0.434700 ;
    PORT
      LAYER met3 ;
        RECT 1199.400 59.880 1200.000 60.480 ;
    END
  END sram_dat_i[0]
  PIN sram_dat_i[10]
    DIRECTION INPUT ;
    USE SIGNAL ;
    ANTENNAGATEAREA 0.647700 ;
    ANTENNADIFFAREA 0.434700 ;
    PORT
      LAYER met3 ;
        RECT 1199.400 198.600 1200.000 199.200 ;
    END
  END sram_dat_i[10]
  PIN sram_dat_i[11]
    DIRECTION INPUT ;
    USE SIGNAL ;
    ANTENNAGATEAREA 0.647700 ;
    ANTENNADIFFAREA 0.434700 ;
    PORT
      LAYER met3 ;
        RECT 1199.400 210.840 1200.000 211.440 ;
    END
  END sram_dat_i[11]
  PIN sram_dat_i[12]
    DIRECTION INPUT ;
    USE SIGNAL ;
    ANTENNAGATEAREA 0.647700 ;
    ANTENNADIFFAREA 0.434700 ;
    PORT
      LAYER met3 ;
        RECT 1199.400 223.080 1200.000 223.680 ;
    END
  END sram_dat_i[12]
  PIN sram_dat_i[13]
    DIRECTION INPUT ;
    USE SIGNAL ;
    ANTENNAGATEAREA 0.647700 ;
    ANTENNADIFFAREA 0.434700 ;
    PORT
      LAYER met3 ;
        RECT 1199.400 235.320 1200.000 235.920 ;
    END
  END sram_dat_i[13]
  PIN sram_dat_i[14]
    DIRECTION INPUT ;
    USE SIGNAL ;
    ANTENNAGATEAREA 0.647700 ;
    ANTENNADIFFAREA 0.434700 ;
    PORT
      LAYER met3 ;
        RECT 1199.400 247.560 1200.000 248.160 ;
    END
  END sram_dat_i[14]
  PIN sram_dat_i[15]
    DIRECTION INPUT ;
    USE SIGNAL ;
    ANTENNAGATEAREA 0.647700 ;
    ANTENNADIFFAREA 0.434700 ;
    PORT
      LAYER met3 ;
        RECT 1199.400 259.800 1200.000 260.400 ;
    END
  END sram_dat_i[15]
  PIN sram_dat_i[16]
    DIRECTION INPUT ;
    USE SIGNAL ;
    ANTENNAGATEAREA 0.647700 ;
    ANTENNADIFFAREA 0.434700 ;
    PORT
      LAYER met3 ;
        RECT 1199.400 272.040 1200.000 272.640 ;
    END
  END sram_dat_i[16]
  PIN sram_dat_i[17]
    DIRECTION INPUT ;
    USE SIGNAL ;
    ANTENNAGATEAREA 0.647700 ;
    ANTENNADIFFAREA 0.434700 ;
    PORT
      LAYER met3 ;
        RECT 1199.400 284.280 1200.000 284.880 ;
    END
  END sram_dat_i[17]
  PIN sram_dat_i[18]
    DIRECTION INPUT ;
    USE SIGNAL ;
    ANTENNAGATEAREA 0.647700 ;
    ANTENNADIFFAREA 0.434700 ;
    PORT
      LAYER met3 ;
        RECT 1199.400 296.520 1200.000 297.120 ;
    END
  END sram_dat_i[18]
  PIN sram_dat_i[19]
    DIRECTION INPUT ;
    USE SIGNAL ;
    ANTENNAGATEAREA 0.647700 ;
    ANTENNADIFFAREA 0.434700 ;
    PORT
      LAYER met3 ;
        RECT 1199.400 308.760 1200.000 309.360 ;
    END
  END sram_dat_i[19]
  PIN sram_dat_i[1]
    DIRECTION INPUT ;
    USE SIGNAL ;
    ANTENNAGATEAREA 0.647700 ;
    ANTENNADIFFAREA 0.434700 ;
    PORT
      LAYER met3 ;
        RECT 1199.400 76.200 1200.000 76.800 ;
    END
  END sram_dat_i[1]
  PIN sram_dat_i[20]
    DIRECTION INPUT ;
    USE SIGNAL ;
    ANTENNAGATEAREA 0.647700 ;
    ANTENNADIFFAREA 0.434700 ;
    PORT
      LAYER met3 ;
        RECT 1199.400 321.000 1200.000 321.600 ;
    END
  END sram_dat_i[20]
  PIN sram_dat_i[21]
    DIRECTION INPUT ;
    USE SIGNAL ;
    ANTENNAGATEAREA 0.647700 ;
    ANTENNADIFFAREA 0.434700 ;
    PORT
      LAYER met3 ;
        RECT 1199.400 333.240 1200.000 333.840 ;
    END
  END sram_dat_i[21]
  PIN sram_dat_i[22]
    DIRECTION INPUT ;
    USE SIGNAL ;
    ANTENNAGATEAREA 0.647700 ;
    ANTENNADIFFAREA 0.434700 ;
    PORT
      LAYER met3 ;
        RECT 1199.400 345.480 1200.000 346.080 ;
    END
  END sram_dat_i[22]
  PIN sram_dat_i[23]
    DIRECTION INPUT ;
    USE SIGNAL ;
    ANTENNAGATEAREA 0.647700 ;
    ANTENNADIFFAREA 0.434700 ;
    PORT
      LAYER met3 ;
        RECT 1199.400 357.720 1200.000 358.320 ;
    END
  END sram_dat_i[23]
  PIN sram_dat_i[24]
    DIRECTION INPUT ;
    USE SIGNAL ;
    ANTENNAGATEAREA 0.647700 ;
    ANTENNADIFFAREA 0.434700 ;
    PORT
      LAYER met3 ;
        RECT 1199.400 369.960 1200.000 370.560 ;
    END
  END sram_dat_i[24]
  PIN sram_dat_i[25]
    DIRECTION INPUT ;
    USE SIGNAL ;
    ANTENNAGATEAREA 0.647700 ;
    ANTENNADIFFAREA 0.434700 ;
    PORT
      LAYER met3 ;
        RECT 1199.400 382.200 1200.000 382.800 ;
    END
  END sram_dat_i[25]
  PIN sram_dat_i[26]
    DIRECTION INPUT ;
    USE SIGNAL ;
    ANTENNAGATEAREA 0.647700 ;
    ANTENNADIFFAREA 0.434700 ;
    PORT
      LAYER met3 ;
        RECT 1199.400 394.440 1200.000 395.040 ;
    END
  END sram_dat_i[26]
  PIN sram_dat_i[27]
    DIRECTION INPUT ;
    USE SIGNAL ;
    ANTENNAGATEAREA 0.647700 ;
    ANTENNADIFFAREA 0.434700 ;
    PORT
      LAYER met3 ;
        RECT 1199.400 406.680 1200.000 407.280 ;
    END
  END sram_dat_i[27]
  PIN sram_dat_i[28]
    DIRECTION INPUT ;
    USE SIGNAL ;
    ANTENNAGATEAREA 0.647700 ;
    ANTENNADIFFAREA 0.434700 ;
    PORT
      LAYER met3 ;
        RECT 1199.400 418.920 1200.000 419.520 ;
    END
  END sram_dat_i[28]
  PIN sram_dat_i[29]
    DIRECTION INPUT ;
    USE SIGNAL ;
    ANTENNAGATEAREA 0.647700 ;
    ANTENNADIFFAREA 0.434700 ;
    PORT
      LAYER met3 ;
        RECT 1199.400 431.160 1200.000 431.760 ;
    END
  END sram_dat_i[29]
  PIN sram_dat_i[2]
    DIRECTION INPUT ;
    USE SIGNAL ;
    ANTENNAGATEAREA 0.647700 ;
    ANTENNADIFFAREA 0.434700 ;
    PORT
      LAYER met3 ;
        RECT 1199.400 92.520 1200.000 93.120 ;
    END
  END sram_dat_i[2]
  PIN sram_dat_i[30]
    DIRECTION INPUT ;
    USE SIGNAL ;
    ANTENNAGATEAREA 0.647700 ;
    ANTENNADIFFAREA 0.434700 ;
    PORT
      LAYER met3 ;
        RECT 1199.400 443.400 1200.000 444.000 ;
    END
  END sram_dat_i[30]
  PIN sram_dat_i[31]
    DIRECTION INPUT ;
    USE SIGNAL ;
    ANTENNAGATEAREA 0.647700 ;
    ANTENNADIFFAREA 0.434700 ;
    PORT
      LAYER met3 ;
        RECT 1199.400 455.640 1200.000 456.240 ;
    END
  END sram_dat_i[31]
  PIN sram_dat_i[3]
    DIRECTION INPUT ;
    USE SIGNAL ;
    ANTENNAGATEAREA 0.647700 ;
    ANTENNADIFFAREA 0.434700 ;
    PORT
      LAYER met3 ;
        RECT 1199.400 108.840 1200.000 109.440 ;
    END
  END sram_dat_i[3]
  PIN sram_dat_i[4]
    DIRECTION INPUT ;
    USE SIGNAL ;
    ANTENNAGATEAREA 0.647700 ;
    ANTENNADIFFAREA 0.434700 ;
    PORT
      LAYER met3 ;
        RECT 1199.400 125.160 1200.000 125.760 ;
    END
  END sram_dat_i[4]
  PIN sram_dat_i[5]
    DIRECTION INPUT ;
    USE SIGNAL ;
    ANTENNAGATEAREA 0.647700 ;
    ANTENNADIFFAREA 0.434700 ;
    PORT
      LAYER met3 ;
        RECT 1199.400 137.400 1200.000 138.000 ;
    END
  END sram_dat_i[5]
  PIN sram_dat_i[6]
    DIRECTION INPUT ;
    USE SIGNAL ;
    ANTENNAGATEAREA 0.647700 ;
    ANTENNADIFFAREA 0.434700 ;
    PORT
      LAYER met3 ;
        RECT 1199.400 149.640 1200.000 150.240 ;
    END
  END sram_dat_i[6]
  PIN sram_dat_i[7]
    DIRECTION INPUT ;
    USE SIGNAL ;
    ANTENNAGATEAREA 0.647700 ;
    ANTENNADIFFAREA 0.434700 ;
    PORT
      LAYER met3 ;
        RECT 1199.400 161.880 1200.000 162.480 ;
    END
  END sram_dat_i[7]
  PIN sram_dat_i[8]
    DIRECTION INPUT ;
    USE SIGNAL ;
    ANTENNAGATEAREA 0.647700 ;
    ANTENNADIFFAREA 0.434700 ;
    PORT
      LAYER met3 ;
        RECT 1199.400 174.120 1200.000 174.720 ;
    END
  END sram_dat_i[8]
  PIN sram_dat_i[9]
    DIRECTION INPUT ;
    USE SIGNAL ;
    ANTENNAGATEAREA 0.647700 ;
    ANTENNADIFFAREA 0.434700 ;
    PORT
      LAYER met3 ;
        RECT 1199.400 186.360 1200.000 186.960 ;
    END
  END sram_dat_i[9]
  PIN sram_dat_o[0]
    DIRECTION OUTPUT ;
    USE SIGNAL ;
    ANTENNADIFFAREA 2.673000 ;
    PORT
      LAYER met3 ;
        RECT 1199.400 63.960 1200.000 64.560 ;
    END
  END sram_dat_o[0]
  PIN sram_dat_o[10]
    DIRECTION OUTPUT ;
    USE SIGNAL ;
    ANTENNADIFFAREA 2.673000 ;
    PORT
      LAYER met3 ;
        RECT 1199.400 202.680 1200.000 203.280 ;
    END
  END sram_dat_o[10]
  PIN sram_dat_o[11]
    DIRECTION OUTPUT ;
    USE SIGNAL ;
    ANTENNADIFFAREA 2.673000 ;
    PORT
      LAYER met3 ;
        RECT 1199.400 214.920 1200.000 215.520 ;
    END
  END sram_dat_o[11]
  PIN sram_dat_o[12]
    DIRECTION OUTPUT ;
    USE SIGNAL ;
    ANTENNADIFFAREA 2.673000 ;
    PORT
      LAYER met3 ;
        RECT 1199.400 227.160 1200.000 227.760 ;
    END
  END sram_dat_o[12]
  PIN sram_dat_o[13]
    DIRECTION OUTPUT ;
    USE SIGNAL ;
    ANTENNADIFFAREA 2.673000 ;
    PORT
      LAYER met3 ;
        RECT 1199.400 239.400 1200.000 240.000 ;
    END
  END sram_dat_o[13]
  PIN sram_dat_o[14]
    DIRECTION OUTPUT ;
    USE SIGNAL ;
    ANTENNADIFFAREA 2.673000 ;
    PORT
      LAYER met3 ;
        RECT 1199.400 251.640 1200.000 252.240 ;
    END
  END sram_dat_o[14]
  PIN sram_dat_o[15]
    DIRECTION OUTPUT ;
    USE SIGNAL ;
    ANTENNADIFFAREA 2.673000 ;
    PORT
      LAYER met3 ;
        RECT 1199.400 263.880 1200.000 264.480 ;
    END
  END sram_dat_o[15]
  PIN sram_dat_o[16]
    DIRECTION OUTPUT ;
    USE SIGNAL ;
    ANTENNADIFFAREA 2.673000 ;
    PORT
      LAYER met3 ;
        RECT 1199.400 276.120 1200.000 276.720 ;
    END
  END sram_dat_o[16]
  PIN sram_dat_o[17]
    DIRECTION OUTPUT ;
    USE SIGNAL ;
    ANTENNADIFFAREA 2.673000 ;
    PORT
      LAYER met3 ;
        RECT 1199.400 288.360 1200.000 288.960 ;
    END
  END sram_dat_o[17]
  PIN sram_dat_o[18]
    DIRECTION OUTPUT ;
    USE SIGNAL ;
    ANTENNADIFFAREA 2.673000 ;
    PORT
      LAYER met3 ;
        RECT 1199.400 300.600 1200.000 301.200 ;
    END
  END sram_dat_o[18]
  PIN sram_dat_o[19]
    DIRECTION OUTPUT ;
    USE SIGNAL ;
    ANTENNADIFFAREA 2.673000 ;
    PORT
      LAYER met3 ;
        RECT 1199.400 312.840 1200.000 313.440 ;
    END
  END sram_dat_o[19]
  PIN sram_dat_o[1]
    DIRECTION OUTPUT ;
    USE SIGNAL ;
    ANTENNADIFFAREA 2.673000 ;
    PORT
      LAYER met3 ;
        RECT 1199.400 80.280 1200.000 80.880 ;
    END
  END sram_dat_o[1]
  PIN sram_dat_o[20]
    DIRECTION OUTPUT ;
    USE SIGNAL ;
    ANTENNADIFFAREA 2.673000 ;
    PORT
      LAYER met3 ;
        RECT 1199.400 325.080 1200.000 325.680 ;
    END
  END sram_dat_o[20]
  PIN sram_dat_o[21]
    DIRECTION OUTPUT ;
    USE SIGNAL ;
    ANTENNADIFFAREA 2.673000 ;
    PORT
      LAYER met3 ;
        RECT 1199.400 337.320 1200.000 337.920 ;
    END
  END sram_dat_o[21]
  PIN sram_dat_o[22]
    DIRECTION OUTPUT ;
    USE SIGNAL ;
    ANTENNADIFFAREA 2.673000 ;
    PORT
      LAYER met3 ;
        RECT 1199.400 349.560 1200.000 350.160 ;
    END
  END sram_dat_o[22]
  PIN sram_dat_o[23]
    DIRECTION OUTPUT ;
    USE SIGNAL ;
    ANTENNADIFFAREA 2.673000 ;
    PORT
      LAYER met3 ;
        RECT 1199.400 361.800 1200.000 362.400 ;
    END
  END sram_dat_o[23]
  PIN sram_dat_o[24]
    DIRECTION OUTPUT ;
    USE SIGNAL ;
    ANTENNADIFFAREA 2.673000 ;
    PORT
      LAYER met3 ;
        RECT 1199.400 374.040 1200.000 374.640 ;
    END
  END sram_dat_o[24]
  PIN sram_dat_o[25]
    DIRECTION OUTPUT ;
    USE SIGNAL ;
    ANTENNADIFFAREA 2.673000 ;
    PORT
      LAYER met3 ;
        RECT 1199.400 386.280 1200.000 386.880 ;
    END
  END sram_dat_o[25]
  PIN sram_dat_o[26]
    DIRECTION OUTPUT ;
    USE SIGNAL ;
    ANTENNADIFFAREA 2.673000 ;
    PORT
      LAYER met3 ;
        RECT 1199.400 398.520 1200.000 399.120 ;
    END
  END sram_dat_o[26]
  PIN sram_dat_o[27]
    DIRECTION OUTPUT ;
    USE SIGNAL ;
    ANTENNADIFFAREA 2.673000 ;
    PORT
      LAYER met3 ;
        RECT 1199.400 410.760 1200.000 411.360 ;
    END
  END sram_dat_o[27]
  PIN sram_dat_o[28]
    DIRECTION OUTPUT ;
    USE SIGNAL ;
    ANTENNADIFFAREA 2.673000 ;
    PORT
      LAYER met3 ;
        RECT 1199.400 423.000 1200.000 423.600 ;
    END
  END sram_dat_o[28]
  PIN sram_dat_o[29]
    DIRECTION OUTPUT ;
    USE SIGNAL ;
    ANTENNADIFFAREA 2.673000 ;
    PORT
      LAYER met3 ;
        RECT 1199.400 435.240 1200.000 435.840 ;
    END
  END sram_dat_o[29]
  PIN sram_dat_o[2]
    DIRECTION OUTPUT ;
    USE SIGNAL ;
    ANTENNADIFFAREA 2.673000 ;
    PORT
      LAYER met3 ;
        RECT 1199.400 96.600 1200.000 97.200 ;
    END
  END sram_dat_o[2]
  PIN sram_dat_o[30]
    DIRECTION OUTPUT ;
    USE SIGNAL ;
    ANTENNADIFFAREA 2.673000 ;
    PORT
      LAYER met3 ;
        RECT 1199.400 447.480 1200.000 448.080 ;
    END
  END sram_dat_o[30]
  PIN sram_dat_o[31]
    DIRECTION OUTPUT ;
    USE SIGNAL ;
    ANTENNADIFFAREA 2.673000 ;
    PORT
      LAYER met3 ;
        RECT 1199.400 459.720 1200.000 460.320 ;
    END
  END sram_dat_o[31]
  PIN sram_dat_o[3]
    DIRECTION OUTPUT ;
    USE SIGNAL ;
    ANTENNADIFFAREA 2.673000 ;
    PORT
      LAYER met3 ;
        RECT 1199.400 112.920 1200.000 113.520 ;
    END
  END sram_dat_o[3]
  PIN sram_dat_o[4]
    DIRECTION OUTPUT ;
    USE SIGNAL ;
    ANTENNADIFFAREA 2.673000 ;
    PORT
      LAYER met3 ;
        RECT 1199.400 129.240 1200.000 129.840 ;
    END
  END sram_dat_o[4]
  PIN sram_dat_o[5]
    DIRECTION OUTPUT ;
    USE SIGNAL ;
    ANTENNADIFFAREA 2.673000 ;
    PORT
      LAYER met3 ;
        RECT 1199.400 141.480 1200.000 142.080 ;
    END
  END sram_dat_o[5]
  PIN sram_dat_o[6]
    DIRECTION OUTPUT ;
    USE SIGNAL ;
    ANTENNADIFFAREA 2.673000 ;
    PORT
      LAYER met3 ;
        RECT 1199.400 153.720 1200.000 154.320 ;
    END
  END sram_dat_o[6]
  PIN sram_dat_o[7]
    DIRECTION OUTPUT ;
    USE SIGNAL ;
    ANTENNADIFFAREA 2.673000 ;
    PORT
      LAYER met3 ;
        RECT 1199.400 165.960 1200.000 166.560 ;
    END
  END sram_dat_o[7]
  PIN sram_dat_o[8]
    DIRECTION OUTPUT ;
    USE SIGNAL ;
    ANTENNADIFFAREA 2.673000 ;
    PORT
      LAYER met3 ;
        RECT 1199.400 178.200 1200.000 178.800 ;
    END
  END sram_dat_o[8]
  PIN sram_dat_o[9]
    DIRECTION OUTPUT ;
    USE SIGNAL ;
    ANTENNADIFFAREA 2.673000 ;
    PORT
      LAYER met3 ;
        RECT 1199.400 190.440 1200.000 191.040 ;
    END
  END sram_dat_o[9]
  PIN sram_sel_o[0]
    DIRECTION OUTPUT ;
    USE SIGNAL ;
    PORT
      LAYER met3 ;
        RECT 1199.400 68.040 1200.000 68.640 ;
    END
  END sram_sel_o[0]
  PIN sram_sel_o[1]
    DIRECTION OUTPUT ;
    USE SIGNAL ;
    PORT
      LAYER met3 ;
        RECT 1199.400 84.360 1200.000 84.960 ;
    END
  END sram_sel_o[1]
  PIN sram_sel_o[2]
    DIRECTION OUTPUT ;
    USE SIGNAL ;
    PORT
      LAYER met3 ;
        RECT 1199.400 100.680 1200.000 101.280 ;
    END
  END sram_sel_o[2]
  PIN sram_sel_o[3]
    DIRECTION OUTPUT ;
    USE SIGNAL ;
    PORT
      LAYER met3 ;
        RECT 1199.400 117.000 1200.000 117.600 ;
    END
  END sram_sel_o[3]
  PIN sram_stb_o
    DIRECTION OUTPUT ;
    USE SIGNAL ;
    ANTENNADIFFAREA 2.673000 ;
    PORT
      LAYER met3 ;
        RECT 1199.400 47.640 1200.000 48.240 ;
    END
  END sram_stb_o
  PIN sram_we_o
    DIRECTION OUTPUT ;
    USE SIGNAL ;
    ANTENNADIFFAREA 2.673000 ;
    PORT
      LAYER met3 ;
        RECT 1199.400 51.720 1200.000 52.320 ;
    END
  END sram_we_o
  PIN user_irq[0]
    DIRECTION OUTPUT ;
    USE SIGNAL ;
    ANTENNADIFFAREA 2.673000 ;
    PORT
      LAYER met2 ;
        RECT 1150.090 0.000 1150.370 0.280 ;
    END
  END user_irq[0]
  PIN user_irq[1]
    DIRECTION OUTPUT ;
    USE SIGNAL ;
    ANTENNADIFFAREA 2.673000 ;
    PORT
      LAYER met2 ;
        RECT 1160.670 0.000 1160.950 0.280 ;
    END
  END user_irq[1]
  PIN user_irq[2]
    DIRECTION OUTPUT ;
    USE SIGNAL ;
    ANTENNADIFFAREA 2.673000 ;
    PORT
      LAYER met2 ;
        RECT 1171.250 0.000 1171.530 0.280 ;
    END
  END user_irq[2]
  PIN vccd1
    DIRECTION INOUT ;
    USE POWER ;
    PORT
      LAYER met4 ;
        RECT 21.040 10.640 22.640 487.120 ;
    END
    PORT
      LAYER met4 ;
        RECT 174.640 10.640 176.240 487.120 ;
    END
    PORT
      LAYER met4 ;
        RECT 328.240 10.640 329.840 487.120 ;
    END
    PORT
      LAYER met4 ;
        RECT 481.840 10.640 483.440 487.120 ;
    END
    PORT
      LAYER met4 ;
        RECT 635.440 10.640 637.040 487.120 ;
    END
    PORT
      LAYER met4 ;
        RECT 789.040 10.640 790.640 487.120 ;
    END
    PORT
      LAYER met4 ;
        RECT 942.640 10.640 944.240 487.120 ;
    END
    PORT
      LAYER met4 ;
        RECT 1096.240 10.640 1097.840 487.120 ;
    END
  END vccd1
  PIN vssd1
    DIRECTION INOUT ;
    USE GROUND ;
    PORT
      LAYER met4 ;
        RECT 24.340 10.640 25.940 487.120 ;
    END
    PORT
      LAYER met4 ;
        RECT 177.940 10.640 179.540 487.120 ;
    END
    PORT
      LAYER met4 ;
        RECT 331.540 10.640 333.140 487.120 ;
    END
    PORT
      LAYER met4 ;
        RECT 485.140 10.640 486.740 487.120 ;
    END
    PORT
      LAYER met4 ;
        RECT 638.740 10.640 640.340 487.120 ;
    END
    PORT
      LAYER met4 ;
        RECT 792.340 10.640 793.940 487.120 ;
    END
    PORT
      LAYER met4 ;
        RECT 945.940 10.640 947.540 487.120 ;
    END
    PORT
      LAYER met4 ;
        RECT 1099.540 10.640 1101.140 487.120 ;
    END
  END vssd1
  PIN wb_clk_i
    DIRECTION INPUT ;
    USE SIGNAL ;
    ANTENNAGATEAREA 1.286700 ;
    ANTENNADIFFAREA 0.434700 ;
    PORT
      LAYER met2 ;
        RECT 28.610 0.000 28.890 0.280 ;
    END
  END wb_clk_i
  PIN wb_rst_i
    DIRECTION INPUT ;
    USE SIGNAL ;
    ANTENNAGATEAREA 0.647700 ;
    ANTENNADIFFAREA 0.434700 ;
    PORT
      LAYER met2 ;
        RECT 39.190 0.000 39.470 0.280 ;
    END
  END wb_rst_i
  PIN wbs_ack_o
    DIRECTION OUTPUT ;
    USE SIGNAL ;
    ANTENNADIFFAREA 2.673000 ;
    PORT
      LAYER met2 ;
        RECT 49.770 0.000 50.050 0.280 ;
    END
  END wbs_ack_o
  PIN wbs_adr_i[0]
    DIRECTION INPUT ;
    USE SIGNAL ;
    ANTENNAGATEAREA 0.593700 ;
    ANTENNADIFFAREA 0.434700 ;
    PORT
      LAYER met2 ;
        RECT 92.090 0.000 92.370 0.280 ;
    END
  END wbs_adr_i[0]
  PIN wbs_adr_i[10]
    DIRECTION INPUT ;
    USE SIGNAL ;
    ANTENNAGATEAREA 0.631200 ;
    ANTENNADIFFAREA 0.434700 ;
    PORT
      LAYER met2 ;
        RECT 451.810 0.000 452.090 0.280 ;
    END
  END wbs_adr_i[10]
  PIN wbs_adr_i[11]
    DIRECTION INPUT ;
    USE SIGNAL ;
    ANTENNAGATEAREA 0.631200 ;
    ANTENNADIFFAREA 0.434700 ;
    PORT
      LAYER met2 ;
        RECT 483.550 0.000 483.830 0.280 ;
    END
  END wbs_adr_i[11]
  PIN wbs_adr_i[12]
    DIRECTION INPUT ;
    USE SIGNAL ;
    ANTENNAGATEAREA 0.560700 ;
    ANTENNADIFFAREA 0.434700 ;
    PORT
      LAYER met2 ;
        RECT 515.290 0.000 515.570 0.280 ;
    END
  END wbs_adr_i[12]
  PIN wbs_adr_i[13]
    DIRECTION INPUT ;
    USE SIGNAL ;
    ANTENNAGATEAREA 0.560700 ;
    ANTENNADIFFAREA 0.434700 ;
    PORT
      LAYER met2 ;
        RECT 547.030 0.000 547.310 0.280 ;
    END
  END wbs_adr_i[13]
  PIN wbs_adr_i[14]
    DIRECTION INPUT ;
    USE SIGNAL ;
    ANTENNAGATEAREA 0.560700 ;
    ANTENNADIFFAREA 0.434700 ;
    PORT
      LAYER met2 ;
        RECT 578.770 0.000 579.050 0.280 ;
    END
  END wbs_adr_i[14]
  PIN wbs_adr_i[15]
    DIRECTION INPUT ;
    USE SIGNAL ;
    ANTENNAGATEAREA 0.560700 ;
    ANTENNADIFFAREA 0.434700 ;
    PORT
      LAYER met2 ;
        RECT 610.510 0.000 610.790 0.280 ;
    END
  END wbs_adr_i[15]
  PIN wbs_adr_i[16]
    DIRECTION INPUT ;
    USE SIGNAL ;
    ANTENNAGATEAREA 0.560700 ;
    ANTENNADIFFAREA 0.434700 ;
    PORT
      LAYER met2 ;
        RECT 642.250 0.000 642.530 0.280 ;
    END
  END wbs_adr_i[16]
  PIN wbs_adr_i[17]
    DIRECTION INPUT ;
    USE SIGNAL ;
    ANTENNAGATEAREA 0.631200 ;
    ANTENNADIFFAREA 0.434700 ;
    PORT
      LAYER met2 ;
        RECT 673.990 0.000 674.270 0.280 ;
    END
  END wbs_adr_i[17]
  PIN wbs_adr_i[18]
    DIRECTION INPUT ;
    USE SIGNAL ;
    ANTENNAGATEAREA 0.560700 ;
    ANTENNADIFFAREA 0.434700 ;
    PORT
      LAYER met2 ;
        RECT 705.730 0.000 706.010 0.280 ;
    END
  END wbs_adr_i[18]
  PIN wbs_adr_i[19]
    DIRECTION INPUT ;
    USE SIGNAL ;
    ANTENNAGATEAREA 0.631200 ;
    ANTENNADIFFAREA 0.434700 ;
    PORT
      LAYER met2 ;
        RECT 737.470 0.000 737.750 0.280 ;
    END
  END wbs_adr_i[19]
  PIN wbs_adr_i[1]
    DIRECTION INPUT ;
    USE SIGNAL ;
    ANTENNAGATEAREA 0.560700 ;
    ANTENNADIFFAREA 0.434700 ;
    PORT
      LAYER met2 ;
        RECT 134.410 0.000 134.690 0.280 ;
    END
  END wbs_adr_i[1]
  PIN wbs_adr_i[20]
    DIRECTION INPUT ;
    USE SIGNAL ;
    ANTENNAGATEAREA 0.560700 ;
    ANTENNADIFFAREA 0.434700 ;
    PORT
      LAYER met2 ;
        RECT 769.210 0.000 769.490 0.280 ;
    END
  END wbs_adr_i[20]
  PIN wbs_adr_i[21]
    DIRECTION INPUT ;
    USE SIGNAL ;
    ANTENNAGATEAREA 0.631200 ;
    ANTENNADIFFAREA 0.434700 ;
    PORT
      LAYER met2 ;
        RECT 800.950 0.000 801.230 0.280 ;
    END
  END wbs_adr_i[21]
  PIN wbs_adr_i[22]
    DIRECTION INPUT ;
    USE SIGNAL ;
    ANTENNAGATEAREA 0.631200 ;
    ANTENNADIFFAREA 0.434700 ;
    PORT
      LAYER met2 ;
        RECT 832.690 0.000 832.970 0.280 ;
    END
  END wbs_adr_i[22]
  PIN wbs_adr_i[23]
    DIRECTION INPUT ;
    USE SIGNAL ;
    ANTENNAGATEAREA 0.560700 ;
    ANTENNADIFFAREA 0.434700 ;
    PORT
      LAYER met2 ;
        RECT 864.430 0.000 864.710 0.280 ;
    END
  END wbs_adr_i[23]
  PIN wbs_adr_i[24]
    DIRECTION INPUT ;
    USE SIGNAL ;
    ANTENNAGATEAREA 0.631200 ;
    ANTENNADIFFAREA 0.434700 ;
    PORT
      LAYER met2 ;
        RECT 896.170 0.000 896.450 0.280 ;
    END
  END wbs_adr_i[24]
  PIN wbs_adr_i[25]
    DIRECTION INPUT ;
    USE SIGNAL ;
    ANTENNAGATEAREA 0.631200 ;
    ANTENNADIFFAREA 0.434700 ;
    PORT
      LAYER met2 ;
        RECT 927.910 0.000 928.190 0.280 ;
    END
  END wbs_adr_i[25]
  PIN wbs_adr_i[26]
    DIRECTION INPUT ;
    USE SIGNAL ;
    ANTENNAGATEAREA 0.560700 ;
    ANTENNADIFFAREA 0.434700 ;
    PORT
      LAYER met2 ;
        RECT 959.650 0.000 959.930 0.280 ;
    END
  END wbs_adr_i[26]
  PIN wbs_adr_i[27]
    DIRECTION INPUT ;
    USE SIGNAL ;
    ANTENNAGATEAREA 0.560700 ;
    ANTENNADIFFAREA 0.434700 ;
    PORT
      LAYER met2 ;
        RECT 991.390 0.000 991.670 0.280 ;
    END
  END wbs_adr_i[27]
  PIN wbs_adr_i[28]
    DIRECTION INPUT ;
    USE SIGNAL ;
    ANTENNAGATEAREA 0.647700 ;
    ANTENNADIFFAREA 0.434700 ;
    PORT
      LAYER met2 ;
        RECT 1023.130 0.000 1023.410 0.280 ;
    END
  END wbs_adr_i[28]
  PIN wbs_adr_i[29]
    DIRECTION INPUT ;
    USE SIGNAL ;
    ANTENNAGATEAREA 0.647700 ;
    ANTENNADIFFAREA 0.434700 ;
    PORT
      LAYER met2 ;
        RECT 1054.870 0.000 1055.150 0.280 ;
    END
  END wbs_adr_i[29]
  PIN wbs_adr_i[2]
    DIRECTION INPUT ;
    USE SIGNAL ;
    ANTENNAGATEAREA 0.560700 ;
    ANTENNADIFFAREA 0.434700 ;
    PORT
      LAYER met2 ;
        RECT 176.730 0.000 177.010 0.280 ;
    END
  END wbs_adr_i[2]
  PIN wbs_adr_i[30]
    DIRECTION INPUT ;
    USE SIGNAL ;
    ANTENNAGATEAREA 0.647700 ;
    ANTENNADIFFAREA 0.434700 ;
    PORT
      LAYER met2 ;
        RECT 1086.610 0.000 1086.890 0.280 ;
    END
  END wbs_adr_i[30]
  PIN wbs_adr_i[31]
    DIRECTION INPUT ;
    USE SIGNAL ;
    ANTENNAGATEAREA 0.647700 ;
    ANTENNADIFFAREA 0.434700 ;
    PORT
      LAYER met2 ;
        RECT 1118.350 0.000 1118.630 0.280 ;
    END
  END wbs_adr_i[31]
  PIN wbs_adr_i[3]
    DIRECTION INPUT ;
    USE SIGNAL ;
    ANTENNAGATEAREA 0.560700 ;
    ANTENNADIFFAREA 0.434700 ;
    PORT
      LAYER met2 ;
        RECT 219.050 0.000 219.330 0.280 ;
    END
  END wbs_adr_i[3]
  PIN wbs_adr_i[4]
    DIRECTION INPUT ;
    USE SIGNAL ;
    ANTENNAGATEAREA 0.560700 ;
    ANTENNADIFFAREA 0.434700 ;
    PORT
      LAYER met2 ;
        RECT 261.370 0.000 261.650 0.280 ;
    END
  END wbs_adr_i[4]
  PIN wbs_adr_i[5]
    DIRECTION INPUT ;
    USE SIGNAL ;
    ANTENNAGATEAREA 0.560700 ;
    ANTENNADIFFAREA 0.434700 ;
    PORT
      LAYER met2 ;
        RECT 293.110 0.000 293.390 0.280 ;
    END
  END wbs_adr_i[5]
  PIN wbs_adr_i[6]
    DIRECTION INPUT ;
    USE SIGNAL ;
    ANTENNAGATEAREA 0.631200 ;
    ANTENNADIFFAREA 0.434700 ;
    PORT
      LAYER met2 ;
        RECT 324.850 0.000 325.130 0.280 ;
    END
  END wbs_adr_i[6]
  PIN wbs_adr_i[7]
    DIRECTION INPUT ;
    USE SIGNAL ;
    ANTENNAGATEAREA 0.631200 ;
    ANTENNADIFFAREA 0.434700 ;
    PORT
      LAYER met2 ;
        RECT 356.590 0.000 356.870 0.280 ;
    END
  END wbs_adr_i[7]
  PIN wbs_adr_i[8]
    DIRECTION INPUT ;
    USE SIGNAL ;
    ANTENNAGATEAREA 0.631200 ;
    ANTENNADIFFAREA 0.434700 ;
    PORT
      LAYER met2 ;
        RECT 388.330 0.000 388.610 0.280 ;
    END
  END wbs_adr_i[8]
  PIN wbs_adr_i[9]
    DIRECTION INPUT ;
    USE SIGNAL ;
    ANTENNAGATEAREA 0.631200 ;
    ANTENNADIFFAREA 0.434700 ;
    PORT
      LAYER met2 ;
        RECT 420.070 0.000 420.350 0.280 ;
    END
  END wbs_adr_i[9]
  PIN wbs_cyc_i
    DIRECTION INPUT ;
    USE SIGNAL ;
    ANTENNAGATEAREA 0.560700 ;
    ANTENNADIFFAREA 0.434700 ;
    PORT
      LAYER met2 ;
        RECT 60.350 0.000 60.630 0.280 ;
    END
  END wbs_cyc_i
  PIN wbs_dat_i[0]
    DIRECTION INPUT ;
    USE SIGNAL ;
    ANTENNAGATEAREA 0.560700 ;
    ANTENNADIFFAREA 0.434700 ;
    PORT
      LAYER met2 ;
        RECT 102.670 0.000 102.950 0.280 ;
    END
  END wbs_dat_i[0]
  PIN wbs_dat_i[10]
    DIRECTION INPUT ;
    USE SIGNAL ;
    ANTENNAGATEAREA 0.560700 ;
    ANTENNADIFFAREA 0.434700 ;
    PORT
      LAYER met2 ;
        RECT 462.390 0.000 462.670 0.280 ;
    END
  END wbs_dat_i[10]
  PIN wbs_dat_i[11]
    DIRECTION INPUT ;
    USE SIGNAL ;
    ANTENNAGATEAREA 0.560700 ;
    ANTENNADIFFAREA 0.434700 ;
    PORT
      LAYER met2 ;
        RECT 494.130 0.000 494.410 0.280 ;
    END
  END wbs_dat_i[11]
  PIN wbs_dat_i[12]
    DIRECTION INPUT ;
    USE SIGNAL ;
    ANTENNAGATEAREA 0.560700 ;
    ANTENNADIFFAREA 0.434700 ;
    PORT
      LAYER met2 ;
        RECT 525.870 0.000 526.150 0.280 ;
    END
  END wbs_dat_i[12]
  PIN wbs_dat_i[13]
    DIRECTION INPUT ;
    USE SIGNAL ;
    ANTENNAGATEAREA 0.560700 ;
    ANTENNADIFFAREA 0.434700 ;
    PORT
      LAYER met2 ;
        RECT 557.610 0.000 557.890 0.280 ;
    END
  END wbs_dat_i[13]
  PIN wbs_dat_i[14]
    DIRECTION INPUT ;
    USE SIGNAL ;
    ANTENNAGATEAREA 0.560700 ;
    ANTENNADIFFAREA 0.434700 ;
    PORT
      LAYER met2 ;
        RECT 589.350 0.000 589.630 0.280 ;
    END
  END wbs_dat_i[14]
  PIN wbs_dat_i[15]
    DIRECTION INPUT ;
    USE SIGNAL ;
    ANTENNAGATEAREA 0.560700 ;
    ANTENNADIFFAREA 0.434700 ;
    PORT
      LAYER met2 ;
        RECT 621.090 0.000 621.370 0.280 ;
    END
  END wbs_dat_i[15]
  PIN wbs_dat_i[16]
    DIRECTION INPUT ;
    USE SIGNAL ;
    ANTENNAGATEAREA 0.560700 ;
    ANTENNADIFFAREA 0.434700 ;
    PORT
      LAYER met2 ;
        RECT 652.830 0.000 653.110 0.280 ;
    END
  END wbs_dat_i[16]
  PIN wbs_dat_i[17]
    DIRECTION INPUT ;
    USE SIGNAL ;
    ANTENNAGATEAREA 0.560700 ;
    ANTENNADIFFAREA 0.434700 ;
    PORT
      LAYER met2 ;
        RECT 684.570 0.000 684.850 0.280 ;
    END
  END wbs_dat_i[17]
  PIN wbs_dat_i[18]
    DIRECTION INPUT ;
    USE SIGNAL ;
    ANTENNAGATEAREA 0.560700 ;
    ANTENNADIFFAREA 0.434700 ;
    PORT
      LAYER met2 ;
        RECT 716.310 0.000 716.590 0.280 ;
    END
  END wbs_dat_i[18]
  PIN wbs_dat_i[19]
    DIRECTION INPUT ;
    USE SIGNAL ;
    ANTENNAGATEAREA 0.560700 ;
    ANTENNADIFFAREA 0.434700 ;
    PORT
      LAYER met2 ;
        RECT 748.050 0.000 748.330 0.280 ;
    END
  END wbs_dat_i[19]
  PIN wbs_dat_i[1]
    DIRECTION INPUT ;
    USE SIGNAL ;
    ANTENNAGATEAREA 0.560700 ;
    ANTENNADIFFAREA 0.434700 ;
    PORT
      LAYER met2 ;
        RECT 144.990 0.000 145.270 0.280 ;
    END
  END wbs_dat_i[1]
  PIN wbs_dat_i[20]
    DIRECTION INPUT ;
    USE SIGNAL ;
    ANTENNAGATEAREA 0.560700 ;
    ANTENNADIFFAREA 0.434700 ;
    PORT
      LAYER met2 ;
        RECT 779.790 0.000 780.070 0.280 ;
    END
  END wbs_dat_i[20]
  PIN wbs_dat_i[21]
    DIRECTION INPUT ;
    USE SIGNAL ;
    ANTENNAGATEAREA 0.560700 ;
    ANTENNADIFFAREA 0.434700 ;
    PORT
      LAYER met2 ;
        RECT 811.530 0.000 811.810 0.280 ;
    END
  END wbs_dat_i[21]
  PIN wbs_dat_i[22]
    DIRECTION INPUT ;
    USE SIGNAL ;
    ANTENNAGATEAREA 0.560700 ;
    ANTENNADIFFAREA 0.434700 ;
    PORT
      LAYER met2 ;
        RECT 843.270 0.000 843.550 0.280 ;
    END
  END wbs_dat_i[22]
  PIN wbs_dat_i[23]
    DIRECTION INPUT ;
    USE SIGNAL ;
    ANTENNAGATEAREA 0.560700 ;
    ANTENNADIFFAREA 0.434700 ;
    PORT
      LAYER met2 ;
        RECT 875.010 0.000 875.290 0.280 ;
    END
  END wbs_dat_i[23]
  PIN wbs_dat_i[24]
    DIRECTION INPUT ;
    USE SIGNAL ;
    ANTENNAGATEAREA 0.560700 ;
    ANTENNADIFFAREA 0.434700 ;
    PORT
      LAYER met2 ;
        RECT 906.750 0.000 907.030 0.280 ;
    END
  END wbs_dat_i[24]
  PIN wbs_dat_i[25]
    DIRECTION INPUT ;
    USE SIGNAL ;
    ANTENNAGATEAREA 0.560700 ;
    ANTENNADIFFAREA 0.434700 ;
    PORT
      LAYER met2 ;
        RECT 938.490 0.000 938.770 0.280 ;
    END
  END wbs_dat_i[25]
  PIN wbs_dat_i[26]
    DIRECTION INPUT ;
    USE SIGNAL ;
    ANTENNAGATEAREA 0.560700 ;
    ANTENNADIFFAREA 0.434700 ;
    PORT
      LAYER met2 ;
        RECT 970.230 0.000 970.510 0.280 ;
    END
  END wbs_dat_i[26]
  PIN wbs_dat_i[27]
    DIRECTION INPUT ;
    USE SIGNAL ;
    ANTENNAGATEAREA 0.560700 ;
    ANTENNADIFFAREA 0.434700 ;
    PORT
      LAYER met2 ;
        RECT 1001.970 0.000 1002.250 0.280 ;
    END
  END wbs_dat_i[27]
  PIN wbs_dat_i[28]
    DIRECTION INPUT ;
    USE SIGNAL ;
    ANTENNAGATEAREA 0.560700 ;
    ANTENNADIFFAREA 0.434700 ;
    PORT
      LAYER met2 ;
        RECT 1033.710 0.000 1033.990 0.280 ;
    END
  END wbs_dat_i[28]
  PIN wbs_dat_i[29]
    DIRECTION INPUT ;
    USE SIGNAL ;
    ANTENNAGATEAREA 0.560700 ;
    ANTENNADIFFAREA 0.434700 ;
    PORT
      LAYER met2 ;
        RECT 1065.450 0.000 1065.730 0.280 ;
    END
  END wbs_dat_i[29]
  PIN wbs_dat_i[2]
    DIRECTION INPUT ;
    USE SIGNAL ;
    ANTENNAGATEAREA 0.560700 ;
    ANTENNADIFFAREA 0.434700 ;
    PORT
      LAYER met2 ;
        RECT 187.310 0.000 187.590 0.280 ;
    END
  END wbs_dat_i[2]
  PIN wbs_dat_i[30]
    DIRECTION INPUT ;
    USE SIGNAL ;
    ANTENNAGATEAREA 0.560700 ;
    ANTENNADIFFAREA 0.434700 ;
    PORT
      LAYER met2 ;
        RECT 1097.190 0.000 1097.470 0.280 ;
    END
  END wbs_dat_i[30]
  PIN wbs_dat_i[31]
    DIRECTION INPUT ;
    USE SIGNAL ;
    ANTENNAGATEAREA 0.560700 ;
    ANTENNADIFFAREA 0.434700 ;
    PORT
      LAYER met2 ;
        RECT 1128.930 0.000 1129.210 0.280 ;
    END
  END wbs_dat_i[31]
  PIN wbs_dat_i[3]
    DIRECTION INPUT ;
    USE SIGNAL ;
    ANTENNAGATEAREA 0.560700 ;
    ANTENNADIFFAREA 0.434700 ;
    PORT
      LAYER met2 ;
        RECT 229.630 0.000 229.910 0.280 ;
    END
  END wbs_dat_i[3]
  PIN wbs_dat_i[4]
    DIRECTION INPUT ;
    USE SIGNAL ;
    ANTENNAGATEAREA 0.560700 ;
    ANTENNADIFFAREA 0.434700 ;
    PORT
      LAYER met2 ;
        RECT 271.950 0.000 272.230 0.280 ;
    END
  END wbs_dat_i[4]
  PIN wbs_dat_i[5]
    DIRECTION INPUT ;
    USE SIGNAL ;
    ANTENNAGATEAREA 0.560700 ;
    ANTENNADIFFAREA 0.434700 ;
    PORT
      LAYER met2 ;
        RECT 303.690 0.000 303.970 0.280 ;
    END
  END wbs_dat_i[5]
  PIN wbs_dat_i[6]
    DIRECTION INPUT ;
    USE SIGNAL ;
    ANTENNAGATEAREA 0.560700 ;
    ANTENNADIFFAREA 0.434700 ;
    PORT
      LAYER met2 ;
        RECT 335.430 0.000 335.710 0.280 ;
    END
  END wbs_dat_i[6]
  PIN wbs_dat_i[7]
    DIRECTION INPUT ;
    USE SIGNAL ;
    ANTENNAGATEAREA 0.560700 ;
    ANTENNADIFFAREA 0.434700 ;
    PORT
      LAYER met2 ;
        RECT 367.170 0.000 367.450 0.280 ;
    END
  END wbs_dat_i[7]
  PIN wbs_dat_i[8]
    DIRECTION INPUT ;
    USE SIGNAL ;
    ANTENNAGATEAREA 0.560700 ;
    ANTENNADIFFAREA 0.434700 ;
    PORT
      LAYER met2 ;
        RECT 398.910 0.000 399.190 0.280 ;
    END
  END wbs_dat_i[8]
  PIN wbs_dat_i[9]
    DIRECTION INPUT ;
    USE SIGNAL ;
    ANTENNAGATEAREA 0.560700 ;
    ANTENNADIFFAREA 0.434700 ;
    PORT
      LAYER met2 ;
        RECT 430.650 0.000 430.930 0.280 ;
    END
  END wbs_dat_i[9]
  PIN wbs_dat_o[0]
    DIRECTION OUTPUT ;
    USE SIGNAL ;
    ANTENNADIFFAREA 2.673000 ;
    PORT
      LAYER met2 ;
        RECT 113.250 0.000 113.530 0.280 ;
    END
  END wbs_dat_o[0]
  PIN wbs_dat_o[10]
    DIRECTION OUTPUT ;
    USE SIGNAL ;
    ANTENNADIFFAREA 2.673000 ;
    PORT
      LAYER met2 ;
        RECT 472.970 0.000 473.250 0.280 ;
    END
  END wbs_dat_o[10]
  PIN wbs_dat_o[11]
    DIRECTION OUTPUT ;
    USE SIGNAL ;
    ANTENNADIFFAREA 2.673000 ;
    PORT
      LAYER met2 ;
        RECT 504.710 0.000 504.990 0.280 ;
    END
  END wbs_dat_o[11]
  PIN wbs_dat_o[12]
    DIRECTION OUTPUT ;
    USE SIGNAL ;
    ANTENNADIFFAREA 2.673000 ;
    PORT
      LAYER met2 ;
        RECT 536.450 0.000 536.730 0.280 ;
    END
  END wbs_dat_o[12]
  PIN wbs_dat_o[13]
    DIRECTION OUTPUT ;
    USE SIGNAL ;
    ANTENNADIFFAREA 2.673000 ;
    PORT
      LAYER met2 ;
        RECT 568.190 0.000 568.470 0.280 ;
    END
  END wbs_dat_o[13]
  PIN wbs_dat_o[14]
    DIRECTION OUTPUT ;
    USE SIGNAL ;
    ANTENNADIFFAREA 2.673000 ;
    PORT
      LAYER met2 ;
        RECT 599.930 0.000 600.210 0.280 ;
    END
  END wbs_dat_o[14]
  PIN wbs_dat_o[15]
    DIRECTION OUTPUT ;
    USE SIGNAL ;
    ANTENNADIFFAREA 2.673000 ;
    PORT
      LAYER met2 ;
        RECT 631.670 0.000 631.950 0.280 ;
    END
  END wbs_dat_o[15]
  PIN wbs_dat_o[16]
    DIRECTION OUTPUT ;
    USE SIGNAL ;
    ANTENNADIFFAREA 2.673000 ;
    PORT
      LAYER met2 ;
        RECT 663.410 0.000 663.690 0.280 ;
    END
  END wbs_dat_o[16]
  PIN wbs_dat_o[17]
    DIRECTION OUTPUT ;
    USE SIGNAL ;
    ANTENNADIFFAREA 2.673000 ;
    PORT
      LAYER met2 ;
        RECT 695.150 0.000 695.430 0.280 ;
    END
  END wbs_dat_o[17]
  PIN wbs_dat_o[18]
    DIRECTION OUTPUT ;
    USE SIGNAL ;
    ANTENNADIFFAREA 2.673000 ;
    PORT
      LAYER met2 ;
        RECT 726.890 0.000 727.170 0.280 ;
    END
  END wbs_dat_o[18]
  PIN wbs_dat_o[19]
    DIRECTION OUTPUT ;
    USE SIGNAL ;
    ANTENNADIFFAREA 2.673000 ;
    PORT
      LAYER met2 ;
        RECT 758.630 0.000 758.910 0.280 ;
    END
  END wbs_dat_o[19]
  PIN wbs_dat_o[1]
    DIRECTION OUTPUT ;
    USE SIGNAL ;
    ANTENNADIFFAREA 2.673000 ;
    PORT
      LAYER met2 ;
        RECT 155.570 0.000 155.850 0.280 ;
    END
  END wbs_dat_o[1]
  PIN wbs_dat_o[20]
    DIRECTION OUTPUT ;
    USE SIGNAL ;
    ANTENNADIFFAREA 2.673000 ;
    PORT
      LAYER met2 ;
        RECT 790.370 0.000 790.650 0.280 ;
    END
  END wbs_dat_o[20]
  PIN wbs_dat_o[21]
    DIRECTION OUTPUT ;
    USE SIGNAL ;
    ANTENNADIFFAREA 2.673000 ;
    PORT
      LAYER met2 ;
        RECT 822.110 0.000 822.390 0.280 ;
    END
  END wbs_dat_o[21]
  PIN wbs_dat_o[22]
    DIRECTION OUTPUT ;
    USE SIGNAL ;
    ANTENNADIFFAREA 2.673000 ;
    PORT
      LAYER met2 ;
        RECT 853.850 0.000 854.130 0.280 ;
    END
  END wbs_dat_o[22]
  PIN wbs_dat_o[23]
    DIRECTION OUTPUT ;
    USE SIGNAL ;
    ANTENNADIFFAREA 2.673000 ;
    PORT
      LAYER met2 ;
        RECT 885.590 0.000 885.870 0.280 ;
    END
  END wbs_dat_o[23]
  PIN wbs_dat_o[24]
    DIRECTION OUTPUT ;
    USE SIGNAL ;
    ANTENNADIFFAREA 2.673000 ;
    PORT
      LAYER met2 ;
        RECT 917.330 0.000 917.610 0.280 ;
    END
  END wbs_dat_o[24]
  PIN wbs_dat_o[25]
    DIRECTION OUTPUT ;
    USE SIGNAL ;
    ANTENNADIFFAREA 2.673000 ;
    PORT
      LAYER met2 ;
        RECT 949.070 0.000 949.350 0.280 ;
    END
  END wbs_dat_o[25]
  PIN wbs_dat_o[26]
    DIRECTION OUTPUT ;
    USE SIGNAL ;
    ANTENNADIFFAREA 2.673000 ;
    PORT
      LAYER met2 ;
        RECT 980.810 0.000 981.090 0.280 ;
    END
  END wbs_dat_o[26]
  PIN wbs_dat_o[27]
    DIRECTION OUTPUT ;
    USE SIGNAL ;
    ANTENNADIFFAREA 2.673000 ;
    PORT
      LAYER met2 ;
        RECT 1012.550 0.000 1012.830 0.280 ;
    END
  END wbs_dat_o[27]
  PIN wbs_dat_o[28]
    DIRECTION OUTPUT ;
    USE SIGNAL ;
    ANTENNADIFFAREA 2.673000 ;
    PORT
      LAYER met2 ;
        RECT 1044.290 0.000 1044.570 0.280 ;
    END
  END wbs_dat_o[28]
  PIN wbs_dat_o[29]
    DIRECTION OUTPUT ;
    USE SIGNAL ;
    ANTENNADIFFAREA 2.673000 ;
    PORT
      LAYER met2 ;
        RECT 1076.030 0.000 1076.310 0.280 ;
    END
  END wbs_dat_o[29]
  PIN wbs_dat_o[2]
    DIRECTION OUTPUT ;
    USE SIGNAL ;
    ANTENNADIFFAREA 2.673000 ;
    PORT
      LAYER met2 ;
        RECT 197.890 0.000 198.170 0.280 ;
    END
  END wbs_dat_o[2]
  PIN wbs_dat_o[30]
    DIRECTION OUTPUT ;
    USE SIGNAL ;
    ANTENNADIFFAREA 2.673000 ;
    PORT
      LAYER met2 ;
        RECT 1107.770 0.000 1108.050 0.280 ;
    END
  END wbs_dat_o[30]
  PIN wbs_dat_o[31]
    DIRECTION OUTPUT ;
    USE SIGNAL ;
    ANTENNADIFFAREA 2.673000 ;
    PORT
      LAYER met2 ;
        RECT 1139.510 0.000 1139.790 0.280 ;
    END
  END wbs_dat_o[31]
  PIN wbs_dat_o[3]
    DIRECTION OUTPUT ;
    USE SIGNAL ;
    ANTENNADIFFAREA 2.673000 ;
    PORT
      LAYER met2 ;
        RECT 240.210 0.000 240.490 0.280 ;
    END
  END wbs_dat_o[3]
  PIN wbs_dat_o[4]
    DIRECTION OUTPUT ;
    USE SIGNAL ;
    ANTENNADIFFAREA 2.673000 ;
    PORT
      LAYER met2 ;
        RECT 282.530 0.000 282.810 0.280 ;
    END
  END wbs_dat_o[4]
  PIN wbs_dat_o[5]
    DIRECTION OUTPUT ;
    USE SIGNAL ;
    ANTENNADIFFAREA 2.673000 ;
    PORT
      LAYER met2 ;
        RECT 314.270 0.000 314.550 0.280 ;
    END
  END wbs_dat_o[5]
  PIN wbs_dat_o[6]
    DIRECTION OUTPUT ;
    USE SIGNAL ;
    ANTENNADIFFAREA 2.673000 ;
    PORT
      LAYER met2 ;
        RECT 346.010 0.000 346.290 0.280 ;
    END
  END wbs_dat_o[6]
  PIN wbs_dat_o[7]
    DIRECTION OUTPUT ;
    USE SIGNAL ;
    ANTENNADIFFAREA 2.673000 ;
    PORT
      LAYER met2 ;
        RECT 377.750 0.000 378.030 0.280 ;
    END
  END wbs_dat_o[7]
  PIN wbs_dat_o[8]
    DIRECTION OUTPUT ;
    USE SIGNAL ;
    ANTENNADIFFAREA 2.673000 ;
    PORT
      LAYER met2 ;
        RECT 409.490 0.000 409.770 0.280 ;
    END
  END wbs_dat_o[8]
  PIN wbs_dat_o[9]
    DIRECTION OUTPUT ;
    USE SIGNAL ;
    ANTENNADIFFAREA 2.673000 ;
    PORT
      LAYER met2 ;
        RECT 441.230 0.000 441.510 0.280 ;
    END
  END wbs_dat_o[9]
  PIN wbs_sel_i[0]
    DIRECTION INPUT ;
    USE SIGNAL ;
    ANTENNAGATEAREA 0.560700 ;
    ANTENNADIFFAREA 0.434700 ;
    PORT
      LAYER met2 ;
        RECT 123.830 0.000 124.110 0.280 ;
    END
  END wbs_sel_i[0]
  PIN wbs_sel_i[1]
    DIRECTION INPUT ;
    USE SIGNAL ;
    ANTENNAGATEAREA 0.560700 ;
    ANTENNADIFFAREA 0.434700 ;
    PORT
      LAYER met2 ;
        RECT 166.150 0.000 166.430 0.280 ;
    END
  END wbs_sel_i[1]
  PIN wbs_sel_i[2]
    DIRECTION INPUT ;
    USE SIGNAL ;
    PORT
      LAYER met2 ;
        RECT 208.470 0.000 208.750 0.280 ;
    END
  END wbs_sel_i[2]
  PIN wbs_sel_i[3]
    DIRECTION INPUT ;
    USE SIGNAL ;
    PORT
      LAYER met2 ;
        RECT 250.790 0.000 251.070 0.280 ;
    END
  END wbs_sel_i[3]
  PIN wbs_stb_i
    DIRECTION INPUT ;
    USE SIGNAL ;
    ANTENNAGATEAREA 0.593700 ;
    ANTENNADIFFAREA 0.434700 ;
    PORT
      LAYER met2 ;
        RECT 70.930 0.000 71.210 0.280 ;
    END
  END wbs_stb_i
  PIN wbs_we_i
    DIRECTION INPUT ;
    USE SIGNAL ;
    ANTENNAGATEAREA 0.560700 ;
    ANTENNADIFFAREA 0.434700 ;
    PORT
      LAYER met2 ;
        RECT 81.510 0.000 81.790 0.280 ;
    END
  END wbs_we_i
  OBS
      LAYER nwell ;
        RECT 5.330 10.760 1194.350 487.070 ;
      LAYER li1 ;
        RECT 5.520 10.795 1194.160 486.965 ;
      LAYER met1 ;
        RECT 0.990 0.040 1194.460 492.620 ;
      LAYER met2 ;
        RECT 1.010 499.440 25.110 499.930 ;
        RECT 25.950 499.440 30.170 499.930 ;
        RECT 31.010 499.440 35.230 499.930 ;
        RECT 36.070 499.440 40.290 499.930 ;
        RECT 41.130 499.440 45.350 499.930 ;
        RECT 46.190 499.440 50.410 499.930 ;
        RECT 51.250 499.440 55.470 499.930 ;
        RECT 56.310 499.440 60.530 499.930 ;
        RECT 61.370 499.440 65.590 499.930 ;
        RECT 66.430 499.440 70.650 499.930 ;
        RECT 71.490 499.440 75.710 499.930 ;
        RECT 76.550 499.440 80.770 499.930 ;
        RECT 81.610 499.440 85.830 499.930 ;
        RECT 86.670 499.440 90.890 499.930 ;
        RECT 91.730 499.440 95.950 499.930 ;
        RECT 96.790 499.440 101.010 499.930 ;
        RECT 101.850 499.440 106.070 499.930 ;
        RECT 106.910 499.440 111.130 499.930 ;
        RECT 111.970 499.440 116.190 499.930 ;
        RECT 117.030 499.440 121.250 499.930 ;
        RECT 122.090 499.440 126.310 499.930 ;
        RECT 127.150 499.440 131.370 499.930 ;
        RECT 132.210 499.440 136.430 499.930 ;
        RECT 137.270 499.440 141.490 499.930 ;
        RECT 142.330 499.440 146.550 499.930 ;
        RECT 147.390 499.440 151.610 499.930 ;
        RECT 152.450 499.440 156.670 499.930 ;
        RECT 157.510 499.440 161.730 499.930 ;
        RECT 162.570 499.440 166.790 499.930 ;
        RECT 167.630 499.440 171.850 499.930 ;
        RECT 172.690 499.440 176.910 499.930 ;
        RECT 177.750 499.440 181.970 499.930 ;
        RECT 182.810 499.440 187.030 499.930 ;
        RECT 187.870 499.440 192.090 499.930 ;
        RECT 192.930 499.440 197.150 499.930 ;
        RECT 197.990 499.440 202.210 499.930 ;
        RECT 203.050 499.440 207.270 499.930 ;
        RECT 208.110 499.440 212.330 499.930 ;
        RECT 213.170 499.440 217.390 499.930 ;
        RECT 218.230 499.440 222.450 499.930 ;
        RECT 223.290 499.440 227.510 499.930 ;
        RECT 228.350 499.440 232.570 499.930 ;
        RECT 233.410 499.440 237.630 499.930 ;
        RECT 238.470 499.440 242.690 499.930 ;
        RECT 243.530 499.440 247.750 499.930 ;
        RECT 248.590 499.440 252.810 499.930 ;
        RECT 253.650 499.440 257.870 499.930 ;
        RECT 258.710 499.440 262.930 499.930 ;
        RECT 263.770 499.440 267.990 499.930 ;
        RECT 268.830 499.440 273.050 499.930 ;
        RECT 273.890 499.440 278.110 499.930 ;
        RECT 278.950 499.440 283.170 499.930 ;
        RECT 284.010 499.440 288.230 499.930 ;
        RECT 289.070 499.440 293.290 499.930 ;
        RECT 294.130 499.440 298.350 499.930 ;
        RECT 299.190 499.440 303.410 499.930 ;
        RECT 304.250 499.440 308.470 499.930 ;
        RECT 309.310 499.440 313.530 499.930 ;
        RECT 314.370 499.440 318.590 499.930 ;
        RECT 319.430 499.440 323.650 499.930 ;
        RECT 324.490 499.440 328.710 499.930 ;
        RECT 329.550 499.440 333.770 499.930 ;
        RECT 334.610 499.440 338.830 499.930 ;
        RECT 339.670 499.440 343.890 499.930 ;
        RECT 344.730 499.440 348.950 499.930 ;
        RECT 349.790 499.440 354.010 499.930 ;
        RECT 354.850 499.440 359.070 499.930 ;
        RECT 359.910 499.440 364.130 499.930 ;
        RECT 364.970 499.440 369.190 499.930 ;
        RECT 370.030 499.440 374.250 499.930 ;
        RECT 375.090 499.440 379.310 499.930 ;
        RECT 380.150 499.440 384.370 499.930 ;
        RECT 385.210 499.440 389.430 499.930 ;
        RECT 390.270 499.440 394.490 499.930 ;
        RECT 395.330 499.440 399.550 499.930 ;
        RECT 400.390 499.440 404.610 499.930 ;
        RECT 405.450 499.440 409.670 499.930 ;
        RECT 410.510 499.440 414.730 499.930 ;
        RECT 415.570 499.440 419.790 499.930 ;
        RECT 420.630 499.440 424.850 499.930 ;
        RECT 425.690 499.440 429.910 499.930 ;
        RECT 430.750 499.440 434.970 499.930 ;
        RECT 435.810 499.440 440.030 499.930 ;
        RECT 440.870 499.440 445.090 499.930 ;
        RECT 445.930 499.440 450.150 499.930 ;
        RECT 450.990 499.440 455.210 499.930 ;
        RECT 456.050 499.440 460.270 499.930 ;
        RECT 461.110 499.440 465.330 499.930 ;
        RECT 466.170 499.440 470.390 499.930 ;
        RECT 471.230 499.440 475.450 499.930 ;
        RECT 476.290 499.440 480.510 499.930 ;
        RECT 481.350 499.440 485.570 499.930 ;
        RECT 486.410 499.440 490.630 499.930 ;
        RECT 491.470 499.440 495.690 499.930 ;
        RECT 496.530 499.440 500.750 499.930 ;
        RECT 501.590 499.440 505.810 499.930 ;
        RECT 506.650 499.440 510.870 499.930 ;
        RECT 511.710 499.440 515.930 499.930 ;
        RECT 516.770 499.440 520.990 499.930 ;
        RECT 521.830 499.440 526.050 499.930 ;
        RECT 526.890 499.440 531.110 499.930 ;
        RECT 531.950 499.440 536.170 499.930 ;
        RECT 537.010 499.440 541.230 499.930 ;
        RECT 542.070 499.440 546.290 499.930 ;
        RECT 547.130 499.440 551.350 499.930 ;
        RECT 552.190 499.440 556.410 499.930 ;
        RECT 557.250 499.440 561.470 499.930 ;
        RECT 562.310 499.440 566.530 499.930 ;
        RECT 567.370 499.440 571.590 499.930 ;
        RECT 572.430 499.440 576.650 499.930 ;
        RECT 577.490 499.440 581.710 499.930 ;
        RECT 582.550 499.440 586.770 499.930 ;
        RECT 587.610 499.440 591.830 499.930 ;
        RECT 592.670 499.440 596.890 499.930 ;
        RECT 597.730 499.440 601.950 499.930 ;
        RECT 602.790 499.440 607.010 499.930 ;
        RECT 607.850 499.440 612.070 499.930 ;
        RECT 612.910 499.440 617.130 499.930 ;
        RECT 617.970 499.440 622.190 499.930 ;
        RECT 623.030 499.440 627.250 499.930 ;
        RECT 628.090 499.440 632.310 499.930 ;
        RECT 633.150 499.440 637.370 499.930 ;
        RECT 638.210 499.440 642.430 499.930 ;
        RECT 643.270 499.440 647.490 499.930 ;
        RECT 648.330 499.440 652.550 499.930 ;
        RECT 653.390 499.440 657.610 499.930 ;
        RECT 658.450 499.440 662.670 499.930 ;
        RECT 663.510 499.440 667.730 499.930 ;
        RECT 668.570 499.440 672.790 499.930 ;
        RECT 673.630 499.440 677.850 499.930 ;
        RECT 678.690 499.440 682.910 499.930 ;
        RECT 683.750 499.440 687.970 499.930 ;
        RECT 688.810 499.440 693.030 499.930 ;
        RECT 693.870 499.440 698.090 499.930 ;
        RECT 698.930 499.440 703.150 499.930 ;
        RECT 703.990 499.440 708.210 499.930 ;
        RECT 709.050 499.440 713.270 499.930 ;
        RECT 714.110 499.440 718.330 499.930 ;
        RECT 719.170 499.440 723.390 499.930 ;
        RECT 724.230 499.440 728.450 499.930 ;
        RECT 729.290 499.440 733.510 499.930 ;
        RECT 734.350 499.440 738.570 499.930 ;
        RECT 739.410 499.440 743.630 499.930 ;
        RECT 744.470 499.440 748.690 499.930 ;
        RECT 749.530 499.440 753.750 499.930 ;
        RECT 754.590 499.440 758.810 499.930 ;
        RECT 759.650 499.440 763.870 499.930 ;
        RECT 764.710 499.440 768.930 499.930 ;
        RECT 769.770 499.440 773.990 499.930 ;
        RECT 774.830 499.440 779.050 499.930 ;
        RECT 779.890 499.440 784.110 499.930 ;
        RECT 784.950 499.440 789.170 499.930 ;
        RECT 790.010 499.440 794.230 499.930 ;
        RECT 795.070 499.440 799.290 499.930 ;
        RECT 800.130 499.440 804.350 499.930 ;
        RECT 805.190 499.440 809.410 499.930 ;
        RECT 810.250 499.440 814.470 499.930 ;
        RECT 815.310 499.440 819.530 499.930 ;
        RECT 820.370 499.440 824.590 499.930 ;
        RECT 825.430 499.440 829.650 499.930 ;
        RECT 830.490 499.440 834.710 499.930 ;
        RECT 835.550 499.440 839.770 499.930 ;
        RECT 840.610 499.440 844.830 499.930 ;
        RECT 845.670 499.440 849.890 499.930 ;
        RECT 850.730 499.440 854.950 499.930 ;
        RECT 855.790 499.440 860.010 499.930 ;
        RECT 860.850 499.440 865.070 499.930 ;
        RECT 865.910 499.440 870.130 499.930 ;
        RECT 870.970 499.440 875.190 499.930 ;
        RECT 876.030 499.440 880.250 499.930 ;
        RECT 881.090 499.440 885.310 499.930 ;
        RECT 886.150 499.440 890.370 499.930 ;
        RECT 891.210 499.440 895.430 499.930 ;
        RECT 896.270 499.440 900.490 499.930 ;
        RECT 901.330 499.440 905.550 499.930 ;
        RECT 906.390 499.440 910.610 499.930 ;
        RECT 911.450 499.440 915.670 499.930 ;
        RECT 916.510 499.440 920.730 499.930 ;
        RECT 921.570 499.440 925.790 499.930 ;
        RECT 926.630 499.440 930.850 499.930 ;
        RECT 931.690 499.440 935.910 499.930 ;
        RECT 936.750 499.440 940.970 499.930 ;
        RECT 941.810 499.440 946.030 499.930 ;
        RECT 946.870 499.440 951.090 499.930 ;
        RECT 951.930 499.440 956.150 499.930 ;
        RECT 956.990 499.440 961.210 499.930 ;
        RECT 962.050 499.440 966.270 499.930 ;
        RECT 967.110 499.440 971.330 499.930 ;
        RECT 972.170 499.440 976.390 499.930 ;
        RECT 977.230 499.440 981.450 499.930 ;
        RECT 982.290 499.440 986.510 499.930 ;
        RECT 987.350 499.440 991.570 499.930 ;
        RECT 992.410 499.440 996.630 499.930 ;
        RECT 997.470 499.440 1001.690 499.930 ;
        RECT 1002.530 499.440 1006.750 499.930 ;
        RECT 1007.590 499.440 1011.810 499.930 ;
        RECT 1012.650 499.440 1016.870 499.930 ;
        RECT 1017.710 499.440 1021.930 499.930 ;
        RECT 1022.770 499.440 1026.990 499.930 ;
        RECT 1027.830 499.440 1032.050 499.930 ;
        RECT 1032.890 499.440 1037.110 499.930 ;
        RECT 1037.950 499.440 1042.170 499.930 ;
        RECT 1043.010 499.440 1047.230 499.930 ;
        RECT 1048.070 499.440 1052.290 499.930 ;
        RECT 1053.130 499.440 1057.350 499.930 ;
        RECT 1058.190 499.440 1062.410 499.930 ;
        RECT 1063.250 499.440 1067.470 499.930 ;
        RECT 1068.310 499.440 1072.530 499.930 ;
        RECT 1073.370 499.440 1077.590 499.930 ;
        RECT 1078.430 499.440 1082.650 499.930 ;
        RECT 1083.490 499.440 1087.710 499.930 ;
        RECT 1088.550 499.440 1092.770 499.930 ;
        RECT 1093.610 499.440 1097.830 499.930 ;
        RECT 1098.670 499.440 1102.890 499.930 ;
        RECT 1103.730 499.440 1107.950 499.930 ;
        RECT 1108.790 499.440 1113.010 499.930 ;
        RECT 1113.850 499.440 1118.070 499.930 ;
        RECT 1118.910 499.440 1123.130 499.930 ;
        RECT 1123.970 499.440 1128.190 499.930 ;
        RECT 1129.030 499.440 1133.250 499.930 ;
        RECT 1134.090 499.440 1138.310 499.930 ;
        RECT 1139.150 499.440 1143.370 499.930 ;
        RECT 1144.210 499.440 1148.430 499.930 ;
        RECT 1149.270 499.440 1153.490 499.930 ;
        RECT 1154.330 499.440 1158.550 499.930 ;
        RECT 1159.390 499.440 1163.610 499.930 ;
        RECT 1164.450 499.440 1168.670 499.930 ;
        RECT 1169.510 499.440 1173.730 499.930 ;
        RECT 1174.570 499.440 1193.150 499.930 ;
        RECT 1.010 0.560 1193.150 499.440 ;
        RECT 1.010 0.010 28.330 0.560 ;
        RECT 29.170 0.010 38.910 0.560 ;
        RECT 39.750 0.010 49.490 0.560 ;
        RECT 50.330 0.010 60.070 0.560 ;
        RECT 60.910 0.010 70.650 0.560 ;
        RECT 71.490 0.010 81.230 0.560 ;
        RECT 82.070 0.010 91.810 0.560 ;
        RECT 92.650 0.010 102.390 0.560 ;
        RECT 103.230 0.010 112.970 0.560 ;
        RECT 113.810 0.010 123.550 0.560 ;
        RECT 124.390 0.010 134.130 0.560 ;
        RECT 134.970 0.010 144.710 0.560 ;
        RECT 145.550 0.010 155.290 0.560 ;
        RECT 156.130 0.010 165.870 0.560 ;
        RECT 166.710 0.010 176.450 0.560 ;
        RECT 177.290 0.010 187.030 0.560 ;
        RECT 187.870 0.010 197.610 0.560 ;
        RECT 198.450 0.010 208.190 0.560 ;
        RECT 209.030 0.010 218.770 0.560 ;
        RECT 219.610 0.010 229.350 0.560 ;
        RECT 230.190 0.010 239.930 0.560 ;
        RECT 240.770 0.010 250.510 0.560 ;
        RECT 251.350 0.010 261.090 0.560 ;
        RECT 261.930 0.010 271.670 0.560 ;
        RECT 272.510 0.010 282.250 0.560 ;
        RECT 283.090 0.010 292.830 0.560 ;
        RECT 293.670 0.010 303.410 0.560 ;
        RECT 304.250 0.010 313.990 0.560 ;
        RECT 314.830 0.010 324.570 0.560 ;
        RECT 325.410 0.010 335.150 0.560 ;
        RECT 335.990 0.010 345.730 0.560 ;
        RECT 346.570 0.010 356.310 0.560 ;
        RECT 357.150 0.010 366.890 0.560 ;
        RECT 367.730 0.010 377.470 0.560 ;
        RECT 378.310 0.010 388.050 0.560 ;
        RECT 388.890 0.010 398.630 0.560 ;
        RECT 399.470 0.010 409.210 0.560 ;
        RECT 410.050 0.010 419.790 0.560 ;
        RECT 420.630 0.010 430.370 0.560 ;
        RECT 431.210 0.010 440.950 0.560 ;
        RECT 441.790 0.010 451.530 0.560 ;
        RECT 452.370 0.010 462.110 0.560 ;
        RECT 462.950 0.010 472.690 0.560 ;
        RECT 473.530 0.010 483.270 0.560 ;
        RECT 484.110 0.010 493.850 0.560 ;
        RECT 494.690 0.010 504.430 0.560 ;
        RECT 505.270 0.010 515.010 0.560 ;
        RECT 515.850 0.010 525.590 0.560 ;
        RECT 526.430 0.010 536.170 0.560 ;
        RECT 537.010 0.010 546.750 0.560 ;
        RECT 547.590 0.010 557.330 0.560 ;
        RECT 558.170 0.010 567.910 0.560 ;
        RECT 568.750 0.010 578.490 0.560 ;
        RECT 579.330 0.010 589.070 0.560 ;
        RECT 589.910 0.010 599.650 0.560 ;
        RECT 600.490 0.010 610.230 0.560 ;
        RECT 611.070 0.010 620.810 0.560 ;
        RECT 621.650 0.010 631.390 0.560 ;
        RECT 632.230 0.010 641.970 0.560 ;
        RECT 642.810 0.010 652.550 0.560 ;
        RECT 653.390 0.010 663.130 0.560 ;
        RECT 663.970 0.010 673.710 0.560 ;
        RECT 674.550 0.010 684.290 0.560 ;
        RECT 685.130 0.010 694.870 0.560 ;
        RECT 695.710 0.010 705.450 0.560 ;
        RECT 706.290 0.010 716.030 0.560 ;
        RECT 716.870 0.010 726.610 0.560 ;
        RECT 727.450 0.010 737.190 0.560 ;
        RECT 738.030 0.010 747.770 0.560 ;
        RECT 748.610 0.010 758.350 0.560 ;
        RECT 759.190 0.010 768.930 0.560 ;
        RECT 769.770 0.010 779.510 0.560 ;
        RECT 780.350 0.010 790.090 0.560 ;
        RECT 790.930 0.010 800.670 0.560 ;
        RECT 801.510 0.010 811.250 0.560 ;
        RECT 812.090 0.010 821.830 0.560 ;
        RECT 822.670 0.010 832.410 0.560 ;
        RECT 833.250 0.010 842.990 0.560 ;
        RECT 843.830 0.010 853.570 0.560 ;
        RECT 854.410 0.010 864.150 0.560 ;
        RECT 864.990 0.010 874.730 0.560 ;
        RECT 875.570 0.010 885.310 0.560 ;
        RECT 886.150 0.010 895.890 0.560 ;
        RECT 896.730 0.010 906.470 0.560 ;
        RECT 907.310 0.010 917.050 0.560 ;
        RECT 917.890 0.010 927.630 0.560 ;
        RECT 928.470 0.010 938.210 0.560 ;
        RECT 939.050 0.010 948.790 0.560 ;
        RECT 949.630 0.010 959.370 0.560 ;
        RECT 960.210 0.010 969.950 0.560 ;
        RECT 970.790 0.010 980.530 0.560 ;
        RECT 981.370 0.010 991.110 0.560 ;
        RECT 991.950 0.010 1001.690 0.560 ;
        RECT 1002.530 0.010 1012.270 0.560 ;
        RECT 1013.110 0.010 1022.850 0.560 ;
        RECT 1023.690 0.010 1033.430 0.560 ;
        RECT 1034.270 0.010 1044.010 0.560 ;
        RECT 1044.850 0.010 1054.590 0.560 ;
        RECT 1055.430 0.010 1065.170 0.560 ;
        RECT 1066.010 0.010 1075.750 0.560 ;
        RECT 1076.590 0.010 1086.330 0.560 ;
        RECT 1087.170 0.010 1096.910 0.560 ;
        RECT 1097.750 0.010 1107.490 0.560 ;
        RECT 1108.330 0.010 1118.070 0.560 ;
        RECT 1118.910 0.010 1128.650 0.560 ;
        RECT 1129.490 0.010 1139.230 0.560 ;
        RECT 1140.070 0.010 1149.810 0.560 ;
        RECT 1150.650 0.010 1160.390 0.560 ;
        RECT 1161.230 0.010 1170.970 0.560 ;
        RECT 1171.810 0.010 1193.150 0.560 ;
      LAYER met3 ;
        RECT 0.600 460.720 1199.400 488.745 ;
        RECT 0.600 459.320 1199.000 460.720 ;
        RECT 0.600 456.640 1199.400 459.320 ;
        RECT 0.600 455.240 1199.000 456.640 ;
        RECT 0.600 452.560 1199.400 455.240 ;
        RECT 0.600 451.160 1199.000 452.560 ;
        RECT 0.600 448.480 1199.400 451.160 ;
        RECT 0.600 447.080 1199.000 448.480 ;
        RECT 0.600 444.400 1199.400 447.080 ;
        RECT 0.600 443.000 1199.000 444.400 ;
        RECT 0.600 440.320 1199.400 443.000 ;
        RECT 0.600 438.920 1199.000 440.320 ;
        RECT 0.600 437.600 1199.400 438.920 ;
        RECT 1.000 436.240 1199.400 437.600 ;
        RECT 1.000 436.200 1199.000 436.240 ;
        RECT 0.600 434.840 1199.000 436.200 ;
        RECT 0.600 433.520 1199.400 434.840 ;
        RECT 1.000 432.160 1199.400 433.520 ;
        RECT 1.000 432.120 1199.000 432.160 ;
        RECT 0.600 430.760 1199.000 432.120 ;
        RECT 0.600 429.440 1199.400 430.760 ;
        RECT 1.000 428.080 1199.400 429.440 ;
        RECT 1.000 428.040 1199.000 428.080 ;
        RECT 0.600 426.680 1199.000 428.040 ;
        RECT 0.600 425.360 1199.400 426.680 ;
        RECT 1.000 424.000 1199.400 425.360 ;
        RECT 1.000 423.960 1199.000 424.000 ;
        RECT 0.600 422.600 1199.000 423.960 ;
        RECT 0.600 421.280 1199.400 422.600 ;
        RECT 1.000 419.920 1199.400 421.280 ;
        RECT 1.000 419.880 1199.000 419.920 ;
        RECT 0.600 418.520 1199.000 419.880 ;
        RECT 0.600 417.200 1199.400 418.520 ;
        RECT 1.000 415.840 1199.400 417.200 ;
        RECT 1.000 415.800 1199.000 415.840 ;
        RECT 0.600 414.440 1199.000 415.800 ;
        RECT 0.600 413.120 1199.400 414.440 ;
        RECT 1.000 411.760 1199.400 413.120 ;
        RECT 1.000 411.720 1199.000 411.760 ;
        RECT 0.600 410.360 1199.000 411.720 ;
        RECT 0.600 409.040 1199.400 410.360 ;
        RECT 1.000 407.680 1199.400 409.040 ;
        RECT 1.000 407.640 1199.000 407.680 ;
        RECT 0.600 406.280 1199.000 407.640 ;
        RECT 0.600 404.960 1199.400 406.280 ;
        RECT 1.000 403.600 1199.400 404.960 ;
        RECT 1.000 403.560 1199.000 403.600 ;
        RECT 0.600 402.200 1199.000 403.560 ;
        RECT 0.600 400.880 1199.400 402.200 ;
        RECT 1.000 399.520 1199.400 400.880 ;
        RECT 1.000 399.480 1199.000 399.520 ;
        RECT 0.600 398.120 1199.000 399.480 ;
        RECT 0.600 396.800 1199.400 398.120 ;
        RECT 1.000 395.440 1199.400 396.800 ;
        RECT 1.000 395.400 1199.000 395.440 ;
        RECT 0.600 394.040 1199.000 395.400 ;
        RECT 0.600 392.720 1199.400 394.040 ;
        RECT 1.000 391.360 1199.400 392.720 ;
        RECT 1.000 391.320 1199.000 391.360 ;
        RECT 0.600 389.960 1199.000 391.320 ;
        RECT 0.600 388.640 1199.400 389.960 ;
        RECT 1.000 387.280 1199.400 388.640 ;
        RECT 1.000 387.240 1199.000 387.280 ;
        RECT 0.600 385.880 1199.000 387.240 ;
        RECT 0.600 384.560 1199.400 385.880 ;
        RECT 1.000 383.200 1199.400 384.560 ;
        RECT 1.000 383.160 1199.000 383.200 ;
        RECT 0.600 381.800 1199.000 383.160 ;
        RECT 0.600 380.480 1199.400 381.800 ;
        RECT 1.000 379.120 1199.400 380.480 ;
        RECT 1.000 379.080 1199.000 379.120 ;
        RECT 0.600 377.720 1199.000 379.080 ;
        RECT 0.600 376.400 1199.400 377.720 ;
        RECT 1.000 375.040 1199.400 376.400 ;
        RECT 1.000 375.000 1199.000 375.040 ;
        RECT 0.600 373.640 1199.000 375.000 ;
        RECT 0.600 372.320 1199.400 373.640 ;
        RECT 1.000 370.960 1199.400 372.320 ;
        RECT 1.000 370.920 1199.000 370.960 ;
        RECT 0.600 369.560 1199.000 370.920 ;
        RECT 0.600 368.240 1199.400 369.560 ;
        RECT 1.000 366.880 1199.400 368.240 ;
        RECT 1.000 366.840 1199.000 366.880 ;
        RECT 0.600 365.480 1199.000 366.840 ;
        RECT 0.600 364.160 1199.400 365.480 ;
        RECT 1.000 362.800 1199.400 364.160 ;
        RECT 1.000 362.760 1199.000 362.800 ;
        RECT 0.600 361.400 1199.000 362.760 ;
        RECT 0.600 360.080 1199.400 361.400 ;
        RECT 1.000 358.720 1199.400 360.080 ;
        RECT 1.000 358.680 1199.000 358.720 ;
        RECT 0.600 357.320 1199.000 358.680 ;
        RECT 0.600 356.000 1199.400 357.320 ;
        RECT 1.000 354.640 1199.400 356.000 ;
        RECT 1.000 354.600 1199.000 354.640 ;
        RECT 0.600 353.240 1199.000 354.600 ;
        RECT 0.600 351.920 1199.400 353.240 ;
        RECT 1.000 350.560 1199.400 351.920 ;
        RECT 1.000 350.520 1199.000 350.560 ;
        RECT 0.600 349.160 1199.000 350.520 ;
        RECT 0.600 347.840 1199.400 349.160 ;
        RECT 1.000 346.480 1199.400 347.840 ;
        RECT 1.000 346.440 1199.000 346.480 ;
        RECT 0.600 345.080 1199.000 346.440 ;
        RECT 0.600 343.760 1199.400 345.080 ;
        RECT 1.000 342.400 1199.400 343.760 ;
        RECT 1.000 342.360 1199.000 342.400 ;
        RECT 0.600 341.000 1199.000 342.360 ;
        RECT 0.600 339.680 1199.400 341.000 ;
        RECT 1.000 338.320 1199.400 339.680 ;
        RECT 1.000 338.280 1199.000 338.320 ;
        RECT 0.600 336.920 1199.000 338.280 ;
        RECT 0.600 335.600 1199.400 336.920 ;
        RECT 1.000 334.240 1199.400 335.600 ;
        RECT 1.000 334.200 1199.000 334.240 ;
        RECT 0.600 332.840 1199.000 334.200 ;
        RECT 0.600 331.520 1199.400 332.840 ;
        RECT 1.000 330.160 1199.400 331.520 ;
        RECT 1.000 330.120 1199.000 330.160 ;
        RECT 0.600 328.760 1199.000 330.120 ;
        RECT 0.600 327.440 1199.400 328.760 ;
        RECT 1.000 326.080 1199.400 327.440 ;
        RECT 1.000 326.040 1199.000 326.080 ;
        RECT 0.600 324.680 1199.000 326.040 ;
        RECT 0.600 323.360 1199.400 324.680 ;
        RECT 1.000 322.000 1199.400 323.360 ;
        RECT 1.000 321.960 1199.000 322.000 ;
        RECT 0.600 320.600 1199.000 321.960 ;
        RECT 0.600 319.280 1199.400 320.600 ;
        RECT 1.000 317.920 1199.400 319.280 ;
        RECT 1.000 317.880 1199.000 317.920 ;
        RECT 0.600 316.520 1199.000 317.880 ;
        RECT 0.600 315.200 1199.400 316.520 ;
        RECT 1.000 313.840 1199.400 315.200 ;
        RECT 1.000 313.800 1199.000 313.840 ;
        RECT 0.600 312.440 1199.000 313.800 ;
        RECT 0.600 311.120 1199.400 312.440 ;
        RECT 1.000 309.760 1199.400 311.120 ;
        RECT 1.000 309.720 1199.000 309.760 ;
        RECT 0.600 308.360 1199.000 309.720 ;
        RECT 0.600 307.040 1199.400 308.360 ;
        RECT 1.000 305.680 1199.400 307.040 ;
        RECT 1.000 305.640 1199.000 305.680 ;
        RECT 0.600 304.280 1199.000 305.640 ;
        RECT 0.600 302.960 1199.400 304.280 ;
        RECT 1.000 301.600 1199.400 302.960 ;
        RECT 1.000 301.560 1199.000 301.600 ;
        RECT 0.600 300.200 1199.000 301.560 ;
        RECT 0.600 298.880 1199.400 300.200 ;
        RECT 1.000 297.520 1199.400 298.880 ;
        RECT 1.000 297.480 1199.000 297.520 ;
        RECT 0.600 296.120 1199.000 297.480 ;
        RECT 0.600 294.800 1199.400 296.120 ;
        RECT 1.000 293.440 1199.400 294.800 ;
        RECT 1.000 293.400 1199.000 293.440 ;
        RECT 0.600 292.040 1199.000 293.400 ;
        RECT 0.600 290.720 1199.400 292.040 ;
        RECT 1.000 289.360 1199.400 290.720 ;
        RECT 1.000 289.320 1199.000 289.360 ;
        RECT 0.600 287.960 1199.000 289.320 ;
        RECT 0.600 286.640 1199.400 287.960 ;
        RECT 1.000 285.280 1199.400 286.640 ;
        RECT 1.000 285.240 1199.000 285.280 ;
        RECT 0.600 283.880 1199.000 285.240 ;
        RECT 0.600 282.560 1199.400 283.880 ;
        RECT 1.000 281.200 1199.400 282.560 ;
        RECT 1.000 281.160 1199.000 281.200 ;
        RECT 0.600 279.800 1199.000 281.160 ;
        RECT 0.600 278.480 1199.400 279.800 ;
        RECT 1.000 277.120 1199.400 278.480 ;
        RECT 1.000 277.080 1199.000 277.120 ;
        RECT 0.600 275.720 1199.000 277.080 ;
        RECT 0.600 274.400 1199.400 275.720 ;
        RECT 1.000 273.040 1199.400 274.400 ;
        RECT 1.000 273.000 1199.000 273.040 ;
        RECT 0.600 271.640 1199.000 273.000 ;
        RECT 0.600 270.320 1199.400 271.640 ;
        RECT 1.000 268.960 1199.400 270.320 ;
        RECT 1.000 268.920 1199.000 268.960 ;
        RECT 0.600 267.560 1199.000 268.920 ;
        RECT 0.600 266.240 1199.400 267.560 ;
        RECT 1.000 264.880 1199.400 266.240 ;
        RECT 1.000 264.840 1199.000 264.880 ;
        RECT 0.600 263.480 1199.000 264.840 ;
        RECT 0.600 262.160 1199.400 263.480 ;
        RECT 1.000 260.800 1199.400 262.160 ;
        RECT 1.000 260.760 1199.000 260.800 ;
        RECT 0.600 259.400 1199.000 260.760 ;
        RECT 0.600 258.080 1199.400 259.400 ;
        RECT 1.000 256.720 1199.400 258.080 ;
        RECT 1.000 256.680 1199.000 256.720 ;
        RECT 0.600 255.320 1199.000 256.680 ;
        RECT 0.600 254.000 1199.400 255.320 ;
        RECT 1.000 252.640 1199.400 254.000 ;
        RECT 1.000 252.600 1199.000 252.640 ;
        RECT 0.600 251.240 1199.000 252.600 ;
        RECT 0.600 249.920 1199.400 251.240 ;
        RECT 1.000 248.560 1199.400 249.920 ;
        RECT 1.000 248.520 1199.000 248.560 ;
        RECT 0.600 247.160 1199.000 248.520 ;
        RECT 0.600 245.840 1199.400 247.160 ;
        RECT 1.000 244.480 1199.400 245.840 ;
        RECT 1.000 244.440 1199.000 244.480 ;
        RECT 0.600 243.080 1199.000 244.440 ;
        RECT 0.600 241.760 1199.400 243.080 ;
        RECT 1.000 240.400 1199.400 241.760 ;
        RECT 1.000 240.360 1199.000 240.400 ;
        RECT 0.600 239.000 1199.000 240.360 ;
        RECT 0.600 237.680 1199.400 239.000 ;
        RECT 1.000 236.320 1199.400 237.680 ;
        RECT 1.000 236.280 1199.000 236.320 ;
        RECT 0.600 234.920 1199.000 236.280 ;
        RECT 0.600 233.600 1199.400 234.920 ;
        RECT 1.000 232.240 1199.400 233.600 ;
        RECT 1.000 232.200 1199.000 232.240 ;
        RECT 0.600 230.840 1199.000 232.200 ;
        RECT 0.600 229.520 1199.400 230.840 ;
        RECT 1.000 228.160 1199.400 229.520 ;
        RECT 1.000 228.120 1199.000 228.160 ;
        RECT 0.600 226.760 1199.000 228.120 ;
        RECT 0.600 225.440 1199.400 226.760 ;
        RECT 1.000 224.080 1199.400 225.440 ;
        RECT 1.000 224.040 1199.000 224.080 ;
        RECT 0.600 222.680 1199.000 224.040 ;
        RECT 0.600 221.360 1199.400 222.680 ;
        RECT 1.000 220.000 1199.400 221.360 ;
        RECT 1.000 219.960 1199.000 220.000 ;
        RECT 0.600 218.600 1199.000 219.960 ;
        RECT 0.600 217.280 1199.400 218.600 ;
        RECT 1.000 215.920 1199.400 217.280 ;
        RECT 1.000 215.880 1199.000 215.920 ;
        RECT 0.600 214.520 1199.000 215.880 ;
        RECT 0.600 213.200 1199.400 214.520 ;
        RECT 1.000 211.840 1199.400 213.200 ;
        RECT 1.000 211.800 1199.000 211.840 ;
        RECT 0.600 210.440 1199.000 211.800 ;
        RECT 0.600 209.120 1199.400 210.440 ;
        RECT 1.000 207.760 1199.400 209.120 ;
        RECT 1.000 207.720 1199.000 207.760 ;
        RECT 0.600 206.360 1199.000 207.720 ;
        RECT 0.600 205.040 1199.400 206.360 ;
        RECT 1.000 203.680 1199.400 205.040 ;
        RECT 1.000 203.640 1199.000 203.680 ;
        RECT 0.600 202.280 1199.000 203.640 ;
        RECT 0.600 200.960 1199.400 202.280 ;
        RECT 1.000 199.600 1199.400 200.960 ;
        RECT 1.000 199.560 1199.000 199.600 ;
        RECT 0.600 198.200 1199.000 199.560 ;
        RECT 0.600 196.880 1199.400 198.200 ;
        RECT 1.000 195.520 1199.400 196.880 ;
        RECT 1.000 195.480 1199.000 195.520 ;
        RECT 0.600 194.120 1199.000 195.480 ;
        RECT 0.600 192.800 1199.400 194.120 ;
        RECT 1.000 191.440 1199.400 192.800 ;
        RECT 1.000 191.400 1199.000 191.440 ;
        RECT 0.600 190.040 1199.000 191.400 ;
        RECT 0.600 188.720 1199.400 190.040 ;
        RECT 1.000 187.360 1199.400 188.720 ;
        RECT 1.000 187.320 1199.000 187.360 ;
        RECT 0.600 185.960 1199.000 187.320 ;
        RECT 0.600 184.640 1199.400 185.960 ;
        RECT 1.000 183.280 1199.400 184.640 ;
        RECT 1.000 183.240 1199.000 183.280 ;
        RECT 0.600 181.880 1199.000 183.240 ;
        RECT 0.600 180.560 1199.400 181.880 ;
        RECT 1.000 179.200 1199.400 180.560 ;
        RECT 1.000 179.160 1199.000 179.200 ;
        RECT 0.600 177.800 1199.000 179.160 ;
        RECT 0.600 176.480 1199.400 177.800 ;
        RECT 1.000 175.120 1199.400 176.480 ;
        RECT 1.000 175.080 1199.000 175.120 ;
        RECT 0.600 173.720 1199.000 175.080 ;
        RECT 0.600 172.400 1199.400 173.720 ;
        RECT 1.000 171.040 1199.400 172.400 ;
        RECT 1.000 171.000 1199.000 171.040 ;
        RECT 0.600 169.640 1199.000 171.000 ;
        RECT 0.600 168.320 1199.400 169.640 ;
        RECT 1.000 166.960 1199.400 168.320 ;
        RECT 1.000 166.920 1199.000 166.960 ;
        RECT 0.600 165.560 1199.000 166.920 ;
        RECT 0.600 164.240 1199.400 165.560 ;
        RECT 1.000 162.880 1199.400 164.240 ;
        RECT 1.000 162.840 1199.000 162.880 ;
        RECT 0.600 161.480 1199.000 162.840 ;
        RECT 0.600 160.160 1199.400 161.480 ;
        RECT 1.000 158.800 1199.400 160.160 ;
        RECT 1.000 158.760 1199.000 158.800 ;
        RECT 0.600 157.400 1199.000 158.760 ;
        RECT 0.600 156.080 1199.400 157.400 ;
        RECT 1.000 154.720 1199.400 156.080 ;
        RECT 1.000 154.680 1199.000 154.720 ;
        RECT 0.600 153.320 1199.000 154.680 ;
        RECT 0.600 152.000 1199.400 153.320 ;
        RECT 1.000 150.640 1199.400 152.000 ;
        RECT 1.000 150.600 1199.000 150.640 ;
        RECT 0.600 149.240 1199.000 150.600 ;
        RECT 0.600 147.920 1199.400 149.240 ;
        RECT 1.000 146.560 1199.400 147.920 ;
        RECT 1.000 146.520 1199.000 146.560 ;
        RECT 0.600 145.160 1199.000 146.520 ;
        RECT 0.600 143.840 1199.400 145.160 ;
        RECT 1.000 142.480 1199.400 143.840 ;
        RECT 1.000 142.440 1199.000 142.480 ;
        RECT 0.600 141.080 1199.000 142.440 ;
        RECT 0.600 139.760 1199.400 141.080 ;
        RECT 1.000 138.400 1199.400 139.760 ;
        RECT 1.000 138.360 1199.000 138.400 ;
        RECT 0.600 137.000 1199.000 138.360 ;
        RECT 0.600 135.680 1199.400 137.000 ;
        RECT 1.000 134.320 1199.400 135.680 ;
        RECT 1.000 134.280 1199.000 134.320 ;
        RECT 0.600 132.920 1199.000 134.280 ;
        RECT 0.600 131.600 1199.400 132.920 ;
        RECT 1.000 130.240 1199.400 131.600 ;
        RECT 1.000 130.200 1199.000 130.240 ;
        RECT 0.600 128.840 1199.000 130.200 ;
        RECT 0.600 127.520 1199.400 128.840 ;
        RECT 1.000 126.160 1199.400 127.520 ;
        RECT 1.000 126.120 1199.000 126.160 ;
        RECT 0.600 124.760 1199.000 126.120 ;
        RECT 0.600 123.440 1199.400 124.760 ;
        RECT 1.000 122.080 1199.400 123.440 ;
        RECT 1.000 122.040 1199.000 122.080 ;
        RECT 0.600 120.680 1199.000 122.040 ;
        RECT 0.600 119.360 1199.400 120.680 ;
        RECT 1.000 118.000 1199.400 119.360 ;
        RECT 1.000 117.960 1199.000 118.000 ;
        RECT 0.600 116.600 1199.000 117.960 ;
        RECT 0.600 115.280 1199.400 116.600 ;
        RECT 1.000 113.920 1199.400 115.280 ;
        RECT 1.000 113.880 1199.000 113.920 ;
        RECT 0.600 112.520 1199.000 113.880 ;
        RECT 0.600 111.200 1199.400 112.520 ;
        RECT 1.000 109.840 1199.400 111.200 ;
        RECT 1.000 109.800 1199.000 109.840 ;
        RECT 0.600 108.440 1199.000 109.800 ;
        RECT 0.600 107.120 1199.400 108.440 ;
        RECT 1.000 105.760 1199.400 107.120 ;
        RECT 1.000 105.720 1199.000 105.760 ;
        RECT 0.600 104.360 1199.000 105.720 ;
        RECT 0.600 103.040 1199.400 104.360 ;
        RECT 1.000 101.680 1199.400 103.040 ;
        RECT 1.000 101.640 1199.000 101.680 ;
        RECT 0.600 100.280 1199.000 101.640 ;
        RECT 0.600 98.960 1199.400 100.280 ;
        RECT 1.000 97.600 1199.400 98.960 ;
        RECT 1.000 97.560 1199.000 97.600 ;
        RECT 0.600 96.200 1199.000 97.560 ;
        RECT 0.600 94.880 1199.400 96.200 ;
        RECT 1.000 93.520 1199.400 94.880 ;
        RECT 1.000 93.480 1199.000 93.520 ;
        RECT 0.600 92.120 1199.000 93.480 ;
        RECT 0.600 90.800 1199.400 92.120 ;
        RECT 1.000 89.440 1199.400 90.800 ;
        RECT 1.000 89.400 1199.000 89.440 ;
        RECT 0.600 88.040 1199.000 89.400 ;
        RECT 0.600 86.720 1199.400 88.040 ;
        RECT 1.000 85.360 1199.400 86.720 ;
        RECT 1.000 85.320 1199.000 85.360 ;
        RECT 0.600 83.960 1199.000 85.320 ;
        RECT 0.600 82.640 1199.400 83.960 ;
        RECT 1.000 81.280 1199.400 82.640 ;
        RECT 1.000 81.240 1199.000 81.280 ;
        RECT 0.600 79.880 1199.000 81.240 ;
        RECT 0.600 78.560 1199.400 79.880 ;
        RECT 1.000 77.200 1199.400 78.560 ;
        RECT 1.000 77.160 1199.000 77.200 ;
        RECT 0.600 75.800 1199.000 77.160 ;
        RECT 0.600 74.480 1199.400 75.800 ;
        RECT 1.000 73.120 1199.400 74.480 ;
        RECT 1.000 73.080 1199.000 73.120 ;
        RECT 0.600 71.720 1199.000 73.080 ;
        RECT 0.600 70.400 1199.400 71.720 ;
        RECT 1.000 69.040 1199.400 70.400 ;
        RECT 1.000 69.000 1199.000 69.040 ;
        RECT 0.600 67.640 1199.000 69.000 ;
        RECT 0.600 66.320 1199.400 67.640 ;
        RECT 1.000 64.960 1199.400 66.320 ;
        RECT 1.000 64.920 1199.000 64.960 ;
        RECT 0.600 63.560 1199.000 64.920 ;
        RECT 0.600 62.240 1199.400 63.560 ;
        RECT 1.000 60.880 1199.400 62.240 ;
        RECT 1.000 60.840 1199.000 60.880 ;
        RECT 0.600 59.480 1199.000 60.840 ;
        RECT 0.600 56.800 1199.400 59.480 ;
        RECT 0.600 55.400 1199.000 56.800 ;
        RECT 0.600 52.720 1199.400 55.400 ;
        RECT 0.600 51.320 1199.000 52.720 ;
        RECT 0.600 48.640 1199.400 51.320 ;
        RECT 0.600 47.240 1199.000 48.640 ;
        RECT 0.600 44.560 1199.400 47.240 ;
        RECT 0.600 43.160 1199.000 44.560 ;
        RECT 0.600 40.480 1199.400 43.160 ;
        RECT 0.600 39.080 1199.000 40.480 ;
        RECT 0.600 9.695 1199.400 39.080 ;
  END
END soc_sys
END LIBRARY

